VERSION 5.8 ;
BUSBITCHARS "[]" ;
DIVIDERCHAR "/" ;
UNITS
    DATABASE MICRONS 1000 ;
END UNITS

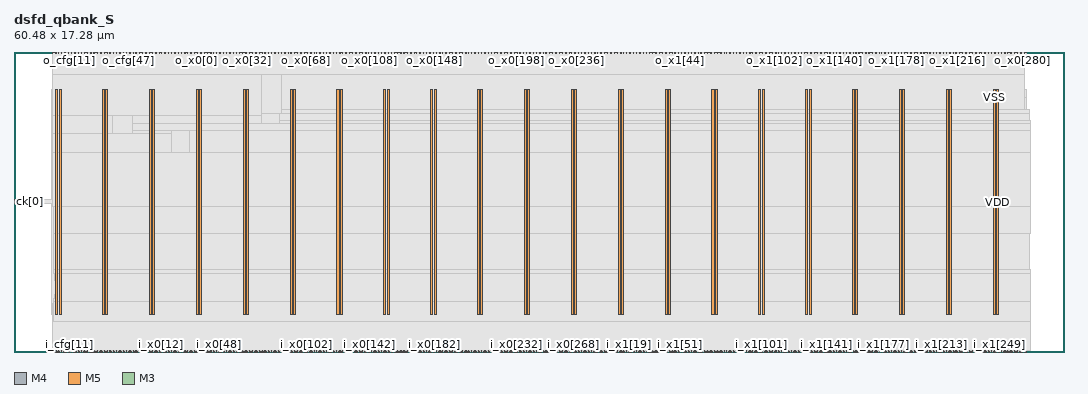
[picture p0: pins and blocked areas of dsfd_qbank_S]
MACRO dsfd_qbank_S
  FOREIGN dsfd_qbank_S 0 0 ;
  CLASS BLOCK ;
  SIZE 60.48 BY 17.28 ;
  PIN ck[0]
    DIRECTION INPUT ;
    USE SIGNAL ;
    PORT
      LAYER M4 ;
        RECT  0 8.64 0.084 8.664 ;
    END
  END ck[0]
  PIN i_cfg[0]
    DIRECTION INPUT ;
    USE SIGNAL ;
    PORT
      LAYER M5 ;
        RECT  2.208 0 2.232 0.084 ;
    END
  END i_cfg[0]
  PIN i_cfg[10]
    DIRECTION INPUT ;
    USE SIGNAL ;
    PORT
      LAYER M5 ;
        RECT  3.12 0 3.144 0.084 ;
    END
  END i_cfg[10]
  PIN i_cfg[11]
    DIRECTION INPUT ;
    USE SIGNAL ;
    PORT
      LAYER M3 ;
        RECT  3.204 0 3.222 0.038 ;
    END
  END i_cfg[11]
  PIN i_cfg[12]
    DIRECTION INPUT ;
    USE SIGNAL ;
    PORT
      LAYER M5 ;
        RECT  3.312 0 3.336 0.084 ;
    END
  END i_cfg[12]
  PIN i_cfg[13]
    DIRECTION INPUT ;
    USE SIGNAL ;
    PORT
      LAYER M3 ;
        RECT  3.42 0 3.438 0.038 ;
    END
  END i_cfg[13]
  PIN i_cfg[14]
    DIRECTION INPUT ;
    USE SIGNAL ;
    PORT
      LAYER M5 ;
        RECT  3.504 0 3.528 0.084 ;
    END
  END i_cfg[14]
  PIN i_cfg[15]
    DIRECTION INPUT ;
    USE SIGNAL ;
    PORT
      LAYER M3 ;
        RECT  3.6 0 3.618 0.038 ;
    END
  END i_cfg[15]
  PIN i_cfg[16]
    DIRECTION INPUT ;
    USE SIGNAL ;
    PORT
      LAYER M5 ;
        RECT  3.696 0 3.72 0.084 ;
    END
  END i_cfg[16]
  PIN i_cfg[17]
    DIRECTION INPUT ;
    USE SIGNAL ;
    PORT
      LAYER M3 ;
        RECT  3.78 0 3.798 0.038 ;
    END
  END i_cfg[17]
  PIN i_cfg[18]
    DIRECTION INPUT ;
    USE SIGNAL ;
    PORT
      LAYER M5 ;
        RECT  3.888 0 3.912 0.084 ;
    END
  END i_cfg[18]
  PIN i_cfg[19]
    DIRECTION INPUT ;
    USE SIGNAL ;
    PORT
      LAYER M3 ;
        RECT  3.996 0 4.014 0.038 ;
    END
  END i_cfg[19]
  PIN i_cfg[1]
    DIRECTION INPUT ;
    USE SIGNAL ;
    PORT
      LAYER M3 ;
        RECT  2.304 0 2.322 0.038 ;
    END
  END i_cfg[1]
  PIN i_cfg[20]
    DIRECTION INPUT ;
    USE SIGNAL ;
    PORT
      LAYER M5 ;
        RECT  4.032 0 4.056 0.084 ;
    END
  END i_cfg[20]
  PIN i_cfg[21]
    DIRECTION INPUT ;
    USE SIGNAL ;
    PORT
      LAYER M3 ;
        RECT  4.14 0 4.158 0.038 ;
    END
  END i_cfg[21]
  PIN i_cfg[22]
    DIRECTION INPUT ;
    USE SIGNAL ;
    PORT
      LAYER M5 ;
        RECT  4.224 0 4.248 0.084 ;
    END
  END i_cfg[22]
  PIN i_cfg[23]
    DIRECTION INPUT ;
    USE SIGNAL ;
    PORT
      LAYER M3 ;
        RECT  4.32 0 4.338 0.038 ;
    END
  END i_cfg[23]
  PIN i_cfg[24]
    DIRECTION INPUT ;
    USE SIGNAL ;
    PORT
      LAYER M5 ;
        RECT  4.416 0 4.44 0.084 ;
    END
  END i_cfg[24]
  PIN i_cfg[25]
    DIRECTION INPUT ;
    USE SIGNAL ;
    PORT
      LAYER M3 ;
        RECT  4.5 0 4.518 0.038 ;
    END
  END i_cfg[25]
  PIN i_cfg[26]
    DIRECTION INPUT ;
    USE SIGNAL ;
    PORT
      LAYER M5 ;
        RECT  4.608 0 4.632 0.084 ;
    END
  END i_cfg[26]
  PIN i_cfg[27]
    DIRECTION INPUT ;
    USE SIGNAL ;
    PORT
      LAYER M3 ;
        RECT  4.716 0 4.734 0.038 ;
    END
  END i_cfg[27]
  PIN i_cfg[28]
    DIRECTION INPUT ;
    USE SIGNAL ;
    PORT
      LAYER M5 ;
        RECT  4.8 0 4.824 0.084 ;
    END
  END i_cfg[28]
  PIN i_cfg[29]
    DIRECTION INPUT ;
    USE SIGNAL ;
    PORT
      LAYER M3 ;
        RECT  4.896 0 4.914 0.038 ;
    END
  END i_cfg[29]
  PIN i_cfg[2]
    DIRECTION INPUT ;
    USE SIGNAL ;
    PORT
      LAYER M5 ;
        RECT  2.4 0 2.424 0.084 ;
    END
  END i_cfg[2]
  PIN i_cfg[30]
    DIRECTION INPUT ;
    USE SIGNAL ;
    PORT
      LAYER M5 ;
        RECT  4.992 0 5.016 0.084 ;
    END
  END i_cfg[30]
  PIN i_cfg[31]
    DIRECTION INPUT ;
    USE SIGNAL ;
    PORT
      LAYER M3 ;
        RECT  5.076 0 5.094 0.038 ;
    END
  END i_cfg[31]
  PIN i_cfg[32]
    DIRECTION INPUT ;
    USE SIGNAL ;
    PORT
      LAYER M5 ;
        RECT  5.184 0 5.208 0.084 ;
    END
  END i_cfg[32]
  PIN i_cfg[33]
    DIRECTION INPUT ;
    USE SIGNAL ;
    PORT
      LAYER M3 ;
        RECT  5.292 0 5.31 0.038 ;
    END
  END i_cfg[33]
  PIN i_cfg[34]
    DIRECTION INPUT ;
    USE SIGNAL ;
    PORT
      LAYER M5 ;
        RECT  5.376 0 5.4 0.084 ;
    END
  END i_cfg[34]
  PIN i_cfg[35]
    DIRECTION INPUT ;
    USE SIGNAL ;
    PORT
      LAYER M3 ;
        RECT  5.472 0 5.49 0.038 ;
    END
  END i_cfg[35]
  PIN i_cfg[36]
    DIRECTION INPUT ;
    USE SIGNAL ;
    PORT
      LAYER M5 ;
        RECT  5.52 0 5.544 0.084 ;
    END
  END i_cfg[36]
  PIN i_cfg[37]
    DIRECTION INPUT ;
    USE SIGNAL ;
    PORT
      LAYER M3 ;
        RECT  5.616 0 5.634 0.038 ;
    END
  END i_cfg[37]
  PIN i_cfg[38]
    DIRECTION INPUT ;
    USE SIGNAL ;
    PORT
      LAYER M5 ;
        RECT  5.712 0 5.736 0.084 ;
    END
  END i_cfg[38]
  PIN i_cfg[39]
    DIRECTION INPUT ;
    USE SIGNAL ;
    PORT
      LAYER M3 ;
        RECT  5.796 0 5.814 0.038 ;
    END
  END i_cfg[39]
  PIN i_cfg[3]
    DIRECTION INPUT ;
    USE SIGNAL ;
    PORT
      LAYER M3 ;
        RECT  2.484 0 2.502 0.038 ;
    END
  END i_cfg[3]
  PIN i_cfg[40]
    DIRECTION INPUT ;
    USE SIGNAL ;
    PORT
      LAYER M5 ;
        RECT  5.904 0 5.928 0.084 ;
    END
  END i_cfg[40]
  PIN i_cfg[41]
    DIRECTION INPUT ;
    USE SIGNAL ;
    PORT
      LAYER M3 ;
        RECT  6.012 0 6.03 0.038 ;
    END
  END i_cfg[41]
  PIN i_cfg[42]
    DIRECTION INPUT ;
    USE SIGNAL ;
    PORT
      LAYER M5 ;
        RECT  6.096 0 6.12 0.084 ;
    END
  END i_cfg[42]
  PIN i_cfg[43]
    DIRECTION INPUT ;
    USE SIGNAL ;
    PORT
      LAYER M3 ;
        RECT  6.192 0 6.21 0.038 ;
    END
  END i_cfg[43]
  PIN i_cfg[44]
    DIRECTION INPUT ;
    USE SIGNAL ;
    PORT
      LAYER M5 ;
        RECT  6.288 0 6.312 0.084 ;
    END
  END i_cfg[44]
  PIN i_cfg[45]
    DIRECTION INPUT ;
    USE SIGNAL ;
    PORT
      LAYER M3 ;
        RECT  6.372 0 6.39 0.038 ;
    END
  END i_cfg[45]
  PIN i_cfg[46]
    DIRECTION INPUT ;
    USE SIGNAL ;
    PORT
      LAYER M5 ;
        RECT  6.48 0 6.504 0.084 ;
    END
  END i_cfg[46]
  PIN i_cfg[47]
    DIRECTION INPUT ;
    USE SIGNAL ;
    PORT
      LAYER M3 ;
        RECT  6.588 0 6.606 0.038 ;
    END
  END i_cfg[47]
  PIN i_cfg[48]
    DIRECTION INPUT ;
    USE SIGNAL ;
    PORT
      LAYER M5 ;
        RECT  6.672 0 6.696 0.084 ;
    END
  END i_cfg[48]
  PIN i_cfg[49]
    DIRECTION INPUT ;
    USE SIGNAL ;
    PORT
      LAYER M3 ;
        RECT  6.768 0 6.786 0.038 ;
    END
  END i_cfg[49]
  PIN i_cfg[4]
    DIRECTION INPUT ;
    USE SIGNAL ;
    PORT
      LAYER M5 ;
        RECT  2.544 0 2.568 0.084 ;
    END
  END i_cfg[4]
  PIN i_cfg[50]
    DIRECTION INPUT ;
    USE SIGNAL ;
    PORT
      LAYER M5 ;
        RECT  6.864 0 6.888 0.084 ;
    END
  END i_cfg[50]
  PIN i_cfg[51]
    DIRECTION INPUT ;
    USE SIGNAL ;
    PORT
      LAYER M3 ;
        RECT  6.948 0 6.966 0.038 ;
    END
  END i_cfg[51]
  PIN i_cfg[52]
    DIRECTION INPUT ;
    USE SIGNAL ;
    PORT
      LAYER M5 ;
        RECT  7.008 0 7.032 0.084 ;
    END
  END i_cfg[52]
  PIN i_cfg[53]
    DIRECTION INPUT ;
    USE SIGNAL ;
    PORT
      LAYER M3 ;
        RECT  7.092 0 7.11 0.038 ;
    END
  END i_cfg[53]
  PIN i_cfg[5]
    DIRECTION INPUT ;
    USE SIGNAL ;
    PORT
      LAYER M3 ;
        RECT  2.628 0 2.646 0.038 ;
    END
  END i_cfg[5]
  PIN i_cfg[6]
    DIRECTION INPUT ;
    USE SIGNAL ;
    PORT
      LAYER M5 ;
        RECT  2.736 0 2.76 0.084 ;
    END
  END i_cfg[6]
  PIN i_cfg[7]
    DIRECTION INPUT ;
    USE SIGNAL ;
    PORT
      LAYER M3 ;
        RECT  2.844 0 2.862 0.038 ;
    END
  END i_cfg[7]
  PIN i_cfg[8]
    DIRECTION INPUT ;
    USE SIGNAL ;
    PORT
      LAYER M5 ;
        RECT  2.928 0 2.952 0.084 ;
    END
  END i_cfg[8]
  PIN i_cfg[9]
    DIRECTION INPUT ;
    USE SIGNAL ;
    PORT
      LAYER M3 ;
        RECT  3.024 0 3.042 0.038 ;
    END
  END i_cfg[9]
  PIN i_go[0]
    DIRECTION INPUT ;
    USE SIGNAL ;
    PORT
      LAYER M5 ;
        RECT  7.2 0 7.224 0.084 ;
    END
  END i_go[0]
  PIN i_x0[0]
    DIRECTION INPUT ;
    USE SIGNAL ;
    PORT
      LAYER M3 ;
        RECT  7.308 0 7.326 0.038 ;
    END
  END i_x0[0]
  PIN i_x0[100]
    DIRECTION INPUT ;
    USE SIGNAL ;
    PORT
      LAYER M3 ;
        RECT  16.596 0 16.614 0.038 ;
    END
  END i_x0[100]
  PIN i_x0[101]
    DIRECTION INPUT ;
    USE SIGNAL ;
    PORT
      LAYER M5 ;
        RECT  16.704 0 16.728 0.084 ;
    END
  END i_x0[101]
  PIN i_x0[102]
    DIRECTION INPUT ;
    USE SIGNAL ;
    PORT
      LAYER M3 ;
        RECT  16.812 0 16.83 0.038 ;
    END
  END i_x0[102]
  PIN i_x0[103]
    DIRECTION INPUT ;
    USE SIGNAL ;
    PORT
      LAYER M5 ;
        RECT  16.896 0 16.92 0.084 ;
    END
  END i_x0[103]
  PIN i_x0[104]
    DIRECTION INPUT ;
    USE SIGNAL ;
    PORT
      LAYER M3 ;
        RECT  16.992 0 17.01 0.038 ;
    END
  END i_x0[104]
  PIN i_x0[105]
    DIRECTION INPUT ;
    USE SIGNAL ;
    PORT
      LAYER M5 ;
        RECT  17.088 0 17.112 0.084 ;
    END
  END i_x0[105]
  PIN i_x0[106]
    DIRECTION INPUT ;
    USE SIGNAL ;
    PORT
      LAYER M3 ;
        RECT  17.172 0 17.19 0.038 ;
    END
  END i_x0[106]
  PIN i_x0[107]
    DIRECTION INPUT ;
    USE SIGNAL ;
    PORT
      LAYER M5 ;
        RECT  17.28 0 17.304 0.084 ;
    END
  END i_x0[107]
  PIN i_x0[108]
    DIRECTION INPUT ;
    USE SIGNAL ;
    PORT
      LAYER M3 ;
        RECT  17.316 0 17.334 0.038 ;
    END
  END i_x0[108]
  PIN i_x0[109]
    DIRECTION INPUT ;
    USE SIGNAL ;
    PORT
      LAYER M5 ;
        RECT  17.424 0 17.448 0.084 ;
    END
  END i_x0[109]
  PIN i_x0[10]
    DIRECTION INPUT ;
    USE SIGNAL ;
    PORT
      LAYER M3 ;
        RECT  8.244 0 8.262 0.038 ;
    END
  END i_x0[10]
  PIN i_x0[110]
    DIRECTION INPUT ;
    USE SIGNAL ;
    PORT
      LAYER M3 ;
        RECT  17.532 0 17.55 0.038 ;
    END
  END i_x0[110]
  PIN i_x0[111]
    DIRECTION INPUT ;
    USE SIGNAL ;
    PORT
      LAYER M5 ;
        RECT  17.616 0 17.64 0.084 ;
    END
  END i_x0[111]
  PIN i_x0[112]
    DIRECTION INPUT ;
    USE SIGNAL ;
    PORT
      LAYER M3 ;
        RECT  17.712 0 17.73 0.038 ;
    END
  END i_x0[112]
  PIN i_x0[113]
    DIRECTION INPUT ;
    USE SIGNAL ;
    PORT
      LAYER M5 ;
        RECT  17.808 0 17.832 0.084 ;
    END
  END i_x0[113]
  PIN i_x0[114]
    DIRECTION INPUT ;
    USE SIGNAL ;
    PORT
      LAYER M3 ;
        RECT  17.892 0 17.91 0.038 ;
    END
  END i_x0[114]
  PIN i_x0[115]
    DIRECTION INPUT ;
    USE SIGNAL ;
    PORT
      LAYER M5 ;
        RECT  18 0 18.024 0.084 ;
    END
  END i_x0[115]
  PIN i_x0[116]
    DIRECTION INPUT ;
    USE SIGNAL ;
    PORT
      LAYER M3 ;
        RECT  18.108 0 18.126 0.038 ;
    END
  END i_x0[116]
  PIN i_x0[117]
    DIRECTION INPUT ;
    USE SIGNAL ;
    PORT
      LAYER M5 ;
        RECT  18.192 0 18.216 0.084 ;
    END
  END i_x0[117]
  PIN i_x0[118]
    DIRECTION INPUT ;
    USE SIGNAL ;
    PORT
      LAYER M3 ;
        RECT  18.288 0 18.306 0.038 ;
    END
  END i_x0[118]
  PIN i_x0[119]
    DIRECTION INPUT ;
    USE SIGNAL ;
    PORT
      LAYER M5 ;
        RECT  18.384 0 18.408 0.084 ;
    END
  END i_x0[119]
  PIN i_x0[11]
    DIRECTION INPUT ;
    USE SIGNAL ;
    PORT
      LAYER M5 ;
        RECT  8.352 0 8.376 0.084 ;
    END
  END i_x0[11]
  PIN i_x0[120]
    DIRECTION INPUT ;
    USE SIGNAL ;
    PORT
      LAYER M3 ;
        RECT  18.468 0 18.486 0.038 ;
    END
  END i_x0[120]
  PIN i_x0[121]
    DIRECTION INPUT ;
    USE SIGNAL ;
    PORT
      LAYER M5 ;
        RECT  18.576 0 18.6 0.084 ;
    END
  END i_x0[121]
  PIN i_x0[122]
    DIRECTION INPUT ;
    USE SIGNAL ;
    PORT
      LAYER M3 ;
        RECT  18.684 0 18.702 0.038 ;
    END
  END i_x0[122]
  PIN i_x0[123]
    DIRECTION INPUT ;
    USE SIGNAL ;
    PORT
      LAYER M5 ;
        RECT  18.768 0 18.792 0.084 ;
    END
  END i_x0[123]
  PIN i_x0[124]
    DIRECTION INPUT ;
    USE SIGNAL ;
    PORT
      LAYER M3 ;
        RECT  18.828 0 18.846 0.038 ;
    END
  END i_x0[124]
  PIN i_x0[125]
    DIRECTION INPUT ;
    USE SIGNAL ;
    PORT
      LAYER M5 ;
        RECT  18.912 0 18.936 0.084 ;
    END
  END i_x0[125]
  PIN i_x0[126]
    DIRECTION INPUT ;
    USE SIGNAL ;
    PORT
      LAYER M3 ;
        RECT  19.008 0 19.026 0.038 ;
    END
  END i_x0[126]
  PIN i_x0[127]
    DIRECTION INPUT ;
    USE SIGNAL ;
    PORT
      LAYER M5 ;
        RECT  19.104 0 19.128 0.084 ;
    END
  END i_x0[127]
  PIN i_x0[128]
    DIRECTION INPUT ;
    USE SIGNAL ;
    PORT
      LAYER M3 ;
        RECT  19.188 0 19.206 0.038 ;
    END
  END i_x0[128]
  PIN i_x0[129]
    DIRECTION INPUT ;
    USE SIGNAL ;
    PORT
      LAYER M5 ;
        RECT  19.296 0 19.32 0.084 ;
    END
  END i_x0[129]
  PIN i_x0[12]
    DIRECTION INPUT ;
    USE SIGNAL ;
    PORT
      LAYER M3 ;
        RECT  8.46 0 8.478 0.038 ;
    END
  END i_x0[12]
  PIN i_x0[130]
    DIRECTION INPUT ;
    USE SIGNAL ;
    PORT
      LAYER M3 ;
        RECT  19.404 0 19.422 0.038 ;
    END
  END i_x0[130]
  PIN i_x0[131]
    DIRECTION INPUT ;
    USE SIGNAL ;
    PORT
      LAYER M5 ;
        RECT  19.488 0 19.512 0.084 ;
    END
  END i_x0[131]
  PIN i_x0[132]
    DIRECTION INPUT ;
    USE SIGNAL ;
    PORT
      LAYER M3 ;
        RECT  19.584 0 19.602 0.038 ;
    END
  END i_x0[132]
  PIN i_x0[133]
    DIRECTION INPUT ;
    USE SIGNAL ;
    PORT
      LAYER M5 ;
        RECT  19.68 0 19.704 0.084 ;
    END
  END i_x0[133]
  PIN i_x0[134]
    DIRECTION INPUT ;
    USE SIGNAL ;
    PORT
      LAYER M3 ;
        RECT  19.764 0 19.782 0.038 ;
    END
  END i_x0[134]
  PIN i_x0[135]
    DIRECTION INPUT ;
    USE SIGNAL ;
    PORT
      LAYER M5 ;
        RECT  19.872 0 19.896 0.084 ;
    END
  END i_x0[135]
  PIN i_x0[136]
    DIRECTION INPUT ;
    USE SIGNAL ;
    PORT
      LAYER M3 ;
        RECT  19.98 0 19.998 0.038 ;
    END
  END i_x0[136]
  PIN i_x0[137]
    DIRECTION INPUT ;
    USE SIGNAL ;
    PORT
      LAYER M5 ;
        RECT  20.064 0 20.088 0.084 ;
    END
  END i_x0[137]
  PIN i_x0[138]
    DIRECTION INPUT ;
    USE SIGNAL ;
    PORT
      LAYER M3 ;
        RECT  20.16 0 20.178 0.038 ;
    END
  END i_x0[138]
  PIN i_x0[139]
    DIRECTION INPUT ;
    USE SIGNAL ;
    PORT
      LAYER M5 ;
        RECT  20.256 0 20.28 0.084 ;
    END
  END i_x0[139]
  PIN i_x0[13]
    DIRECTION INPUT ;
    USE SIGNAL ;
    PORT
      LAYER M5 ;
        RECT  8.496 0 8.52 0.084 ;
    END
  END i_x0[13]
  PIN i_x0[140]
    DIRECTION INPUT ;
    USE SIGNAL ;
    PORT
      LAYER M3 ;
        RECT  20.304 0 20.322 0.038 ;
    END
  END i_x0[140]
  PIN i_x0[141]
    DIRECTION INPUT ;
    USE SIGNAL ;
    PORT
      LAYER M5 ;
        RECT  20.4 0 20.424 0.084 ;
    END
  END i_x0[141]
  PIN i_x0[142]
    DIRECTION INPUT ;
    USE SIGNAL ;
    PORT
      LAYER M3 ;
        RECT  20.484 0 20.502 0.038 ;
    END
  END i_x0[142]
  PIN i_x0[143]
    DIRECTION INPUT ;
    USE SIGNAL ;
    PORT
      LAYER M5 ;
        RECT  20.592 0 20.616 0.084 ;
    END
  END i_x0[143]
  PIN i_x0[144]
    DIRECTION INPUT ;
    USE SIGNAL ;
    PORT
      LAYER M3 ;
        RECT  20.7 0 20.718 0.038 ;
    END
  END i_x0[144]
  PIN i_x0[145]
    DIRECTION INPUT ;
    USE SIGNAL ;
    PORT
      LAYER M5 ;
        RECT  20.784 0 20.808 0.084 ;
    END
  END i_x0[145]
  PIN i_x0[146]
    DIRECTION INPUT ;
    USE SIGNAL ;
    PORT
      LAYER M3 ;
        RECT  20.88 0 20.898 0.038 ;
    END
  END i_x0[146]
  PIN i_x0[147]
    DIRECTION INPUT ;
    USE SIGNAL ;
    PORT
      LAYER M5 ;
        RECT  20.976 0 21 0.084 ;
    END
  END i_x0[147]
  PIN i_x0[148]
    DIRECTION INPUT ;
    USE SIGNAL ;
    PORT
      LAYER M3 ;
        RECT  21.06 0 21.078 0.038 ;
    END
  END i_x0[148]
  PIN i_x0[149]
    DIRECTION INPUT ;
    USE SIGNAL ;
    PORT
      LAYER M5 ;
        RECT  21.168 0 21.192 0.084 ;
    END
  END i_x0[149]
  PIN i_x0[14]
    DIRECTION INPUT ;
    USE SIGNAL ;
    PORT
      LAYER M3 ;
        RECT  8.604 0 8.622 0.038 ;
    END
  END i_x0[14]
  PIN i_x0[150]
    DIRECTION INPUT ;
    USE SIGNAL ;
    PORT
      LAYER M3 ;
        RECT  21.276 0 21.294 0.038 ;
    END
  END i_x0[150]
  PIN i_x0[151]
    DIRECTION INPUT ;
    USE SIGNAL ;
    PORT
      LAYER M5 ;
        RECT  21.36 0 21.384 0.084 ;
    END
  END i_x0[151]
  PIN i_x0[152]
    DIRECTION INPUT ;
    USE SIGNAL ;
    PORT
      LAYER M3 ;
        RECT  21.456 0 21.474 0.038 ;
    END
  END i_x0[152]
  PIN i_x0[153]
    DIRECTION INPUT ;
    USE SIGNAL ;
    PORT
      LAYER M5 ;
        RECT  21.552 0 21.576 0.084 ;
    END
  END i_x0[153]
  PIN i_x0[154]
    DIRECTION INPUT ;
    USE SIGNAL ;
    PORT
      LAYER M3 ;
        RECT  21.636 0 21.654 0.038 ;
    END
  END i_x0[154]
  PIN i_x0[155]
    DIRECTION INPUT ;
    USE SIGNAL ;
    PORT
      LAYER M5 ;
        RECT  21.744 0 21.768 0.084 ;
    END
  END i_x0[155]
  PIN i_x0[156]
    DIRECTION INPUT ;
    USE SIGNAL ;
    PORT
      LAYER M3 ;
        RECT  21.78 0 21.798 0.038 ;
    END
  END i_x0[156]
  PIN i_x0[157]
    DIRECTION INPUT ;
    USE SIGNAL ;
    PORT
      LAYER M5 ;
        RECT  21.888 0 21.912 0.084 ;
    END
  END i_x0[157]
  PIN i_x0[158]
    DIRECTION INPUT ;
    USE SIGNAL ;
    PORT
      LAYER M3 ;
        RECT  21.996 0 22.014 0.038 ;
    END
  END i_x0[158]
  PIN i_x0[159]
    DIRECTION INPUT ;
    USE SIGNAL ;
    PORT
      LAYER M5 ;
        RECT  22.08 0 22.104 0.084 ;
    END
  END i_x0[159]
  PIN i_x0[15]
    DIRECTION INPUT ;
    USE SIGNAL ;
    PORT
      LAYER M5 ;
        RECT  8.688 0 8.712 0.084 ;
    END
  END i_x0[15]
  PIN i_x0[160]
    DIRECTION INPUT ;
    USE SIGNAL ;
    PORT
      LAYER M3 ;
        RECT  22.176 0 22.194 0.038 ;
    END
  END i_x0[160]
  PIN i_x0[161]
    DIRECTION INPUT ;
    USE SIGNAL ;
    PORT
      LAYER M5 ;
        RECT  22.272 0 22.296 0.084 ;
    END
  END i_x0[161]
  PIN i_x0[162]
    DIRECTION INPUT ;
    USE SIGNAL ;
    PORT
      LAYER M3 ;
        RECT  22.356 0 22.374 0.038 ;
    END
  END i_x0[162]
  PIN i_x0[163]
    DIRECTION INPUT ;
    USE SIGNAL ;
    PORT
      LAYER M5 ;
        RECT  22.464 0 22.488 0.084 ;
    END
  END i_x0[163]
  PIN i_x0[164]
    DIRECTION INPUT ;
    USE SIGNAL ;
    PORT
      LAYER M3 ;
        RECT  22.572 0 22.59 0.038 ;
    END
  END i_x0[164]
  PIN i_x0[165]
    DIRECTION INPUT ;
    USE SIGNAL ;
    PORT
      LAYER M5 ;
        RECT  22.656 0 22.68 0.084 ;
    END
  END i_x0[165]
  PIN i_x0[166]
    DIRECTION INPUT ;
    USE SIGNAL ;
    PORT
      LAYER M3 ;
        RECT  22.752 0 22.77 0.038 ;
    END
  END i_x0[166]
  PIN i_x0[167]
    DIRECTION INPUT ;
    USE SIGNAL ;
    PORT
      LAYER M5 ;
        RECT  22.848 0 22.872 0.084 ;
    END
  END i_x0[167]
  PIN i_x0[168]
    DIRECTION INPUT ;
    USE SIGNAL ;
    PORT
      LAYER M3 ;
        RECT  22.932 0 22.95 0.038 ;
    END
  END i_x0[168]
  PIN i_x0[169]
    DIRECTION INPUT ;
    USE SIGNAL ;
    PORT
      LAYER M5 ;
        RECT  23.04 0 23.064 0.084 ;
    END
  END i_x0[169]
  PIN i_x0[16]
    DIRECTION INPUT ;
    USE SIGNAL ;
    PORT
      LAYER M3 ;
        RECT  8.784 0 8.802 0.038 ;
    END
  END i_x0[16]
  PIN i_x0[170]
    DIRECTION INPUT ;
    USE SIGNAL ;
    PORT
      LAYER M3 ;
        RECT  23.148 0 23.166 0.038 ;
    END
  END i_x0[170]
  PIN i_x0[171]
    DIRECTION INPUT ;
    USE SIGNAL ;
    PORT
      LAYER M5 ;
        RECT  23.184 0 23.208 0.084 ;
    END
  END i_x0[171]
  PIN i_x0[172]
    DIRECTION INPUT ;
    USE SIGNAL ;
    PORT
      LAYER M3 ;
        RECT  23.292 0 23.31 0.038 ;
    END
  END i_x0[172]
  PIN i_x0[173]
    DIRECTION INPUT ;
    USE SIGNAL ;
    PORT
      LAYER M5 ;
        RECT  23.376 0 23.4 0.084 ;
    END
  END i_x0[173]
  PIN i_x0[174]
    DIRECTION INPUT ;
    USE SIGNAL ;
    PORT
      LAYER M3 ;
        RECT  23.472 0 23.49 0.038 ;
    END
  END i_x0[174]
  PIN i_x0[175]
    DIRECTION INPUT ;
    USE SIGNAL ;
    PORT
      LAYER M5 ;
        RECT  23.568 0 23.592 0.084 ;
    END
  END i_x0[175]
  PIN i_x0[176]
    DIRECTION INPUT ;
    USE SIGNAL ;
    PORT
      LAYER M3 ;
        RECT  23.652 0 23.67 0.038 ;
    END
  END i_x0[176]
  PIN i_x0[177]
    DIRECTION INPUT ;
    USE SIGNAL ;
    PORT
      LAYER M5 ;
        RECT  23.76 0 23.784 0.084 ;
    END
  END i_x0[177]
  PIN i_x0[178]
    DIRECTION INPUT ;
    USE SIGNAL ;
    PORT
      LAYER M3 ;
        RECT  23.868 0 23.886 0.038 ;
    END
  END i_x0[178]
  PIN i_x0[179]
    DIRECTION INPUT ;
    USE SIGNAL ;
    PORT
      LAYER M5 ;
        RECT  23.952 0 23.976 0.084 ;
    END
  END i_x0[179]
  PIN i_x0[17]
    DIRECTION INPUT ;
    USE SIGNAL ;
    PORT
      LAYER M5 ;
        RECT  8.88 0 8.904 0.084 ;
    END
  END i_x0[17]
  PIN i_x0[180]
    DIRECTION INPUT ;
    USE SIGNAL ;
    PORT
      LAYER M3 ;
        RECT  24.048 0 24.066 0.038 ;
    END
  END i_x0[180]
  PIN i_x0[181]
    DIRECTION INPUT ;
    USE SIGNAL ;
    PORT
      LAYER M5 ;
        RECT  24.144 0 24.168 0.084 ;
    END
  END i_x0[181]
  PIN i_x0[182]
    DIRECTION INPUT ;
    USE SIGNAL ;
    PORT
      LAYER M3 ;
        RECT  24.228 0 24.246 0.038 ;
    END
  END i_x0[182]
  PIN i_x0[183]
    DIRECTION INPUT ;
    USE SIGNAL ;
    PORT
      LAYER M5 ;
        RECT  24.336 0 24.36 0.084 ;
    END
  END i_x0[183]
  PIN i_x0[184]
    DIRECTION INPUT ;
    USE SIGNAL ;
    PORT
      LAYER M3 ;
        RECT  24.444 0 24.462 0.038 ;
    END
  END i_x0[184]
  PIN i_x0[185]
    DIRECTION INPUT ;
    USE SIGNAL ;
    PORT
      LAYER M5 ;
        RECT  24.528 0 24.552 0.084 ;
    END
  END i_x0[185]
  PIN i_x0[186]
    DIRECTION INPUT ;
    USE SIGNAL ;
    PORT
      LAYER M3 ;
        RECT  24.624 0 24.642 0.038 ;
    END
  END i_x0[186]
  PIN i_x0[187]
    DIRECTION INPUT ;
    USE SIGNAL ;
    PORT
      LAYER M5 ;
        RECT  24.672 0 24.696 0.084 ;
    END
  END i_x0[187]
  PIN i_x0[188]
    DIRECTION INPUT ;
    USE SIGNAL ;
    PORT
      LAYER M3 ;
        RECT  24.768 0 24.786 0.038 ;
    END
  END i_x0[188]
  PIN i_x0[189]
    DIRECTION INPUT ;
    USE SIGNAL ;
    PORT
      LAYER M5 ;
        RECT  24.864 0 24.888 0.084 ;
    END
  END i_x0[189]
  PIN i_x0[18]
    DIRECTION INPUT ;
    USE SIGNAL ;
    PORT
      LAYER M3 ;
        RECT  8.964 0 8.982 0.038 ;
    END
  END i_x0[18]
  PIN i_x0[190]
    DIRECTION INPUT ;
    USE SIGNAL ;
    PORT
      LAYER M3 ;
        RECT  24.948 0 24.966 0.038 ;
    END
  END i_x0[190]
  PIN i_x0[191]
    DIRECTION INPUT ;
    USE SIGNAL ;
    PORT
      LAYER M5 ;
        RECT  25.056 0 25.08 0.084 ;
    END
  END i_x0[191]
  PIN i_x0[192]
    DIRECTION INPUT ;
    USE SIGNAL ;
    PORT
      LAYER M3 ;
        RECT  25.164 0 25.182 0.038 ;
    END
  END i_x0[192]
  PIN i_x0[193]
    DIRECTION INPUT ;
    USE SIGNAL ;
    PORT
      LAYER M5 ;
        RECT  25.248 0 25.272 0.084 ;
    END
  END i_x0[193]
  PIN i_x0[194]
    DIRECTION INPUT ;
    USE SIGNAL ;
    PORT
      LAYER M3 ;
        RECT  25.344 0 25.362 0.038 ;
    END
  END i_x0[194]
  PIN i_x0[195]
    DIRECTION INPUT ;
    USE SIGNAL ;
    PORT
      LAYER M5 ;
        RECT  25.44 0 25.464 0.084 ;
    END
  END i_x0[195]
  PIN i_x0[196]
    DIRECTION INPUT ;
    USE SIGNAL ;
    PORT
      LAYER M3 ;
        RECT  25.524 0 25.542 0.038 ;
    END
  END i_x0[196]
  PIN i_x0[197]
    DIRECTION INPUT ;
    USE SIGNAL ;
    PORT
      LAYER M5 ;
        RECT  25.632 0 25.656 0.084 ;
    END
  END i_x0[197]
  PIN i_x0[198]
    DIRECTION INPUT ;
    USE SIGNAL ;
    PORT
      LAYER M3 ;
        RECT  25.74 0 25.758 0.038 ;
    END
  END i_x0[198]
  PIN i_x0[199]
    DIRECTION INPUT ;
    USE SIGNAL ;
    PORT
      LAYER M5 ;
        RECT  25.824 0 25.848 0.084 ;
    END
  END i_x0[199]
  PIN i_x0[19]
    DIRECTION INPUT ;
    USE SIGNAL ;
    PORT
      LAYER M5 ;
        RECT  9.072 0 9.096 0.084 ;
    END
  END i_x0[19]
  PIN i_x0[1]
    DIRECTION INPUT ;
    USE SIGNAL ;
    PORT
      LAYER M5 ;
        RECT  7.392 0 7.416 0.084 ;
    END
  END i_x0[1]
  PIN i_x0[200]
    DIRECTION INPUT ;
    USE SIGNAL ;
    PORT
      LAYER M3 ;
        RECT  25.92 0 25.938 0.038 ;
    END
  END i_x0[200]
  PIN i_x0[201]
    DIRECTION INPUT ;
    USE SIGNAL ;
    PORT
      LAYER M5 ;
        RECT  26.016 0 26.04 0.084 ;
    END
  END i_x0[201]
  PIN i_x0[202]
    DIRECTION INPUT ;
    USE SIGNAL ;
    PORT
      LAYER M3 ;
        RECT  26.1 0 26.118 0.038 ;
    END
  END i_x0[202]
  PIN i_x0[203]
    DIRECTION INPUT ;
    USE SIGNAL ;
    PORT
      LAYER M5 ;
        RECT  26.16 0 26.184 0.084 ;
    END
  END i_x0[203]
  PIN i_x0[204]
    DIRECTION INPUT ;
    USE SIGNAL ;
    PORT
      LAYER M3 ;
        RECT  26.244 0 26.262 0.038 ;
    END
  END i_x0[204]
  PIN i_x0[205]
    DIRECTION INPUT ;
    USE SIGNAL ;
    PORT
      LAYER M5 ;
        RECT  26.352 0 26.376 0.084 ;
    END
  END i_x0[205]
  PIN i_x0[206]
    DIRECTION INPUT ;
    USE SIGNAL ;
    PORT
      LAYER M3 ;
        RECT  26.46 0 26.478 0.038 ;
    END
  END i_x0[206]
  PIN i_x0[207]
    DIRECTION INPUT ;
    USE SIGNAL ;
    PORT
      LAYER M5 ;
        RECT  26.544 0 26.568 0.084 ;
    END
  END i_x0[207]
  PIN i_x0[208]
    DIRECTION INPUT ;
    USE SIGNAL ;
    PORT
      LAYER M3 ;
        RECT  26.64 0 26.658 0.038 ;
    END
  END i_x0[208]
  PIN i_x0[209]
    DIRECTION INPUT ;
    USE SIGNAL ;
    PORT
      LAYER M5 ;
        RECT  26.736 0 26.76 0.084 ;
    END
  END i_x0[209]
  PIN i_x0[20]
    DIRECTION INPUT ;
    USE SIGNAL ;
    PORT
      LAYER M3 ;
        RECT  9.18 0 9.198 0.038 ;
    END
  END i_x0[20]
  PIN i_x0[210]
    DIRECTION INPUT ;
    USE SIGNAL ;
    PORT
      LAYER M3 ;
        RECT  26.82 0 26.838 0.038 ;
    END
  END i_x0[210]
  PIN i_x0[211]
    DIRECTION INPUT ;
    USE SIGNAL ;
    PORT
      LAYER M5 ;
        RECT  26.928 0 26.952 0.084 ;
    END
  END i_x0[211]
  PIN i_x0[212]
    DIRECTION INPUT ;
    USE SIGNAL ;
    PORT
      LAYER M3 ;
        RECT  27.036 0 27.054 0.038 ;
    END
  END i_x0[212]
  PIN i_x0[213]
    DIRECTION INPUT ;
    USE SIGNAL ;
    PORT
      LAYER M5 ;
        RECT  27.12 0 27.144 0.084 ;
    END
  END i_x0[213]
  PIN i_x0[214]
    DIRECTION INPUT ;
    USE SIGNAL ;
    PORT
      LAYER M3 ;
        RECT  27.216 0 27.234 0.038 ;
    END
  END i_x0[214]
  PIN i_x0[215]
    DIRECTION INPUT ;
    USE SIGNAL ;
    PORT
      LAYER M5 ;
        RECT  27.312 0 27.336 0.084 ;
    END
  END i_x0[215]
  PIN i_x0[216]
    DIRECTION INPUT ;
    USE SIGNAL ;
    PORT
      LAYER M3 ;
        RECT  27.396 0 27.414 0.038 ;
    END
  END i_x0[216]
  PIN i_x0[217]
    DIRECTION INPUT ;
    USE SIGNAL ;
    PORT
      LAYER M5 ;
        RECT  27.504 0 27.528 0.084 ;
    END
  END i_x0[217]
  PIN i_x0[218]
    DIRECTION INPUT ;
    USE SIGNAL ;
    PORT
      LAYER M3 ;
        RECT  27.612 0 27.63 0.038 ;
    END
  END i_x0[218]
  PIN i_x0[219]
    DIRECTION INPUT ;
    USE SIGNAL ;
    PORT
      LAYER M5 ;
        RECT  27.648 0 27.672 0.084 ;
    END
  END i_x0[219]
  PIN i_x0[21]
    DIRECTION INPUT ;
    USE SIGNAL ;
    PORT
      LAYER M5 ;
        RECT  9.264 0 9.288 0.084 ;
    END
  END i_x0[21]
  PIN i_x0[220]
    DIRECTION INPUT ;
    USE SIGNAL ;
    PORT
      LAYER M3 ;
        RECT  27.756 0 27.774 0.038 ;
    END
  END i_x0[220]
  PIN i_x0[221]
    DIRECTION INPUT ;
    USE SIGNAL ;
    PORT
      LAYER M5 ;
        RECT  27.84 0 27.864 0.084 ;
    END
  END i_x0[221]
  PIN i_x0[222]
    DIRECTION INPUT ;
    USE SIGNAL ;
    PORT
      LAYER M3 ;
        RECT  27.936 0 27.954 0.038 ;
    END
  END i_x0[222]
  PIN i_x0[223]
    DIRECTION INPUT ;
    USE SIGNAL ;
    PORT
      LAYER M5 ;
        RECT  28.032 0 28.056 0.084 ;
    END
  END i_x0[223]
  PIN i_x0[224]
    DIRECTION INPUT ;
    USE SIGNAL ;
    PORT
      LAYER M3 ;
        RECT  28.116 0 28.134 0.038 ;
    END
  END i_x0[224]
  PIN i_x0[225]
    DIRECTION INPUT ;
    USE SIGNAL ;
    PORT
      LAYER M5 ;
        RECT  28.224 0 28.248 0.084 ;
    END
  END i_x0[225]
  PIN i_x0[226]
    DIRECTION INPUT ;
    USE SIGNAL ;
    PORT
      LAYER M3 ;
        RECT  28.332 0 28.35 0.038 ;
    END
  END i_x0[226]
  PIN i_x0[227]
    DIRECTION INPUT ;
    USE SIGNAL ;
    PORT
      LAYER M5 ;
        RECT  28.416 0 28.44 0.084 ;
    END
  END i_x0[227]
  PIN i_x0[228]
    DIRECTION INPUT ;
    USE SIGNAL ;
    PORT
      LAYER M3 ;
        RECT  28.512 0 28.53 0.038 ;
    END
  END i_x0[228]
  PIN i_x0[229]
    DIRECTION INPUT ;
    USE SIGNAL ;
    PORT
      LAYER M5 ;
        RECT  28.608 0 28.632 0.084 ;
    END
  END i_x0[229]
  PIN i_x0[22]
    DIRECTION INPUT ;
    USE SIGNAL ;
    PORT
      LAYER M3 ;
        RECT  9.36 0 9.378 0.038 ;
    END
  END i_x0[22]
  PIN i_x0[230]
    DIRECTION INPUT ;
    USE SIGNAL ;
    PORT
      LAYER M3 ;
        RECT  28.692 0 28.71 0.038 ;
    END
  END i_x0[230]
  PIN i_x0[231]
    DIRECTION INPUT ;
    USE SIGNAL ;
    PORT
      LAYER M5 ;
        RECT  28.8 0 28.824 0.084 ;
    END
  END i_x0[231]
  PIN i_x0[232]
    DIRECTION INPUT ;
    USE SIGNAL ;
    PORT
      LAYER M3 ;
        RECT  28.908 0 28.926 0.038 ;
    END
  END i_x0[232]
  PIN i_x0[233]
    DIRECTION INPUT ;
    USE SIGNAL ;
    PORT
      LAYER M5 ;
        RECT  28.992 0 29.016 0.084 ;
    END
  END i_x0[233]
  PIN i_x0[234]
    DIRECTION INPUT ;
    USE SIGNAL ;
    PORT
      LAYER M3 ;
        RECT  29.088 0 29.106 0.038 ;
    END
  END i_x0[234]
  PIN i_x0[235]
    DIRECTION INPUT ;
    USE SIGNAL ;
    PORT
      LAYER M5 ;
        RECT  29.136 0 29.16 0.084 ;
    END
  END i_x0[235]
  PIN i_x0[236]
    DIRECTION INPUT ;
    USE SIGNAL ;
    PORT
      LAYER M3 ;
        RECT  29.232 0 29.25 0.038 ;
    END
  END i_x0[236]
  PIN i_x0[237]
    DIRECTION INPUT ;
    USE SIGNAL ;
    PORT
      LAYER M5 ;
        RECT  29.328 0 29.352 0.084 ;
    END
  END i_x0[237]
  PIN i_x0[238]
    DIRECTION INPUT ;
    USE SIGNAL ;
    PORT
      LAYER M3 ;
        RECT  29.412 0 29.43 0.038 ;
    END
  END i_x0[238]
  PIN i_x0[239]
    DIRECTION INPUT ;
    USE SIGNAL ;
    PORT
      LAYER M5 ;
        RECT  29.52 0 29.544 0.084 ;
    END
  END i_x0[239]
  PIN i_x0[23]
    DIRECTION INPUT ;
    USE SIGNAL ;
    PORT
      LAYER M5 ;
        RECT  9.456 0 9.48 0.084 ;
    END
  END i_x0[23]
  PIN i_x0[240]
    DIRECTION INPUT ;
    USE SIGNAL ;
    PORT
      LAYER M3 ;
        RECT  29.628 0 29.646 0.038 ;
    END
  END i_x0[240]
  PIN i_x0[241]
    DIRECTION INPUT ;
    USE SIGNAL ;
    PORT
      LAYER M5 ;
        RECT  29.712 0 29.736 0.084 ;
    END
  END i_x0[241]
  PIN i_x0[242]
    DIRECTION INPUT ;
    USE SIGNAL ;
    PORT
      LAYER M3 ;
        RECT  29.808 0 29.826 0.038 ;
    END
  END i_x0[242]
  PIN i_x0[243]
    DIRECTION INPUT ;
    USE SIGNAL ;
    PORT
      LAYER M5 ;
        RECT  29.904 0 29.928 0.084 ;
    END
  END i_x0[243]
  PIN i_x0[244]
    DIRECTION INPUT ;
    USE SIGNAL ;
    PORT
      LAYER M3 ;
        RECT  29.988 0 30.006 0.038 ;
    END
  END i_x0[244]
  PIN i_x0[245]
    DIRECTION INPUT ;
    USE SIGNAL ;
    PORT
      LAYER M5 ;
        RECT  30.096 0 30.12 0.084 ;
    END
  END i_x0[245]
  PIN i_x0[246]
    DIRECTION INPUT ;
    USE SIGNAL ;
    PORT
      LAYER M3 ;
        RECT  30.204 0 30.222 0.038 ;
    END
  END i_x0[246]
  PIN i_x0[247]
    DIRECTION INPUT ;
    USE SIGNAL ;
    PORT
      LAYER M5 ;
        RECT  30.288 0 30.312 0.084 ;
    END
  END i_x0[247]
  PIN i_x0[248]
    DIRECTION INPUT ;
    USE SIGNAL ;
    PORT
      LAYER M3 ;
        RECT  30.384 0 30.402 0.038 ;
    END
  END i_x0[248]
  PIN i_x0[249]
    DIRECTION INPUT ;
    USE SIGNAL ;
    PORT
      LAYER M5 ;
        RECT  30.48 0 30.504 0.084 ;
    END
  END i_x0[249]
  PIN i_x0[24]
    DIRECTION INPUT ;
    USE SIGNAL ;
    PORT
      LAYER M3 ;
        RECT  9.54 0 9.558 0.038 ;
    END
  END i_x0[24]
  PIN i_x0[250]
    DIRECTION INPUT ;
    USE SIGNAL ;
    PORT
      LAYER M3 ;
        RECT  30.564 0 30.582 0.038 ;
    END
  END i_x0[250]
  PIN i_x0[251]
    DIRECTION INPUT ;
    USE SIGNAL ;
    PORT
      LAYER M5 ;
        RECT  30.624 0 30.648 0.084 ;
    END
  END i_x0[251]
  PIN i_x0[252]
    DIRECTION INPUT ;
    USE SIGNAL ;
    PORT
      LAYER M3 ;
        RECT  30.708 0 30.726 0.038 ;
    END
  END i_x0[252]
  PIN i_x0[253]
    DIRECTION INPUT ;
    USE SIGNAL ;
    PORT
      LAYER M5 ;
        RECT  30.816 0 30.84 0.084 ;
    END
  END i_x0[253]
  PIN i_x0[254]
    DIRECTION INPUT ;
    USE SIGNAL ;
    PORT
      LAYER M3 ;
        RECT  30.924 0 30.942 0.038 ;
    END
  END i_x0[254]
  PIN i_x0[255]
    DIRECTION INPUT ;
    USE SIGNAL ;
    PORT
      LAYER M5 ;
        RECT  31.008 0 31.032 0.084 ;
    END
  END i_x0[255]
  PIN i_x0[256]
    DIRECTION INPUT ;
    USE SIGNAL ;
    PORT
      LAYER M3 ;
        RECT  31.104 0 31.122 0.038 ;
    END
  END i_x0[256]
  PIN i_x0[257]
    DIRECTION INPUT ;
    USE SIGNAL ;
    PORT
      LAYER M5 ;
        RECT  31.2 0 31.224 0.084 ;
    END
  END i_x0[257]
  PIN i_x0[258]
    DIRECTION INPUT ;
    USE SIGNAL ;
    PORT
      LAYER M3 ;
        RECT  31.284 0 31.302 0.038 ;
    END
  END i_x0[258]
  PIN i_x0[259]
    DIRECTION INPUT ;
    USE SIGNAL ;
    PORT
      LAYER M5 ;
        RECT  31.392 0 31.416 0.084 ;
    END
  END i_x0[259]
  PIN i_x0[25]
    DIRECTION INPUT ;
    USE SIGNAL ;
    PORT
      LAYER M5 ;
        RECT  9.648 0 9.672 0.084 ;
    END
  END i_x0[25]
  PIN i_x0[260]
    DIRECTION INPUT ;
    USE SIGNAL ;
    PORT
      LAYER M3 ;
        RECT  31.5 0 31.518 0.038 ;
    END
  END i_x0[260]
  PIN i_x0[261]
    DIRECTION INPUT ;
    USE SIGNAL ;
    PORT
      LAYER M5 ;
        RECT  31.584 0 31.608 0.084 ;
    END
  END i_x0[261]
  PIN i_x0[262]
    DIRECTION INPUT ;
    USE SIGNAL ;
    PORT
      LAYER M3 ;
        RECT  31.68 0 31.698 0.038 ;
    END
  END i_x0[262]
  PIN i_x0[263]
    DIRECTION INPUT ;
    USE SIGNAL ;
    PORT
      LAYER M5 ;
        RECT  31.776 0 31.8 0.084 ;
    END
  END i_x0[263]
  PIN i_x0[264]
    DIRECTION INPUT ;
    USE SIGNAL ;
    PORT
      LAYER M3 ;
        RECT  31.86 0 31.878 0.038 ;
    END
  END i_x0[264]
  PIN i_x0[265]
    DIRECTION INPUT ;
    USE SIGNAL ;
    PORT
      LAYER M5 ;
        RECT  31.968 0 31.992 0.084 ;
    END
  END i_x0[265]
  PIN i_x0[266]
    DIRECTION INPUT ;
    USE SIGNAL ;
    PORT
      LAYER M3 ;
        RECT  32.076 0 32.094 0.038 ;
    END
  END i_x0[266]
  PIN i_x0[267]
    DIRECTION INPUT ;
    USE SIGNAL ;
    PORT
      LAYER M5 ;
        RECT  32.112 0 32.136 0.084 ;
    END
  END i_x0[267]
  PIN i_x0[268]
    DIRECTION INPUT ;
    USE SIGNAL ;
    PORT
      LAYER M3 ;
        RECT  32.22 0 32.238 0.038 ;
    END
  END i_x0[268]
  PIN i_x0[269]
    DIRECTION INPUT ;
    USE SIGNAL ;
    PORT
      LAYER M5 ;
        RECT  32.304 0 32.328 0.084 ;
    END
  END i_x0[269]
  PIN i_x0[26]
    DIRECTION INPUT ;
    USE SIGNAL ;
    PORT
      LAYER M3 ;
        RECT  9.756 0 9.774 0.038 ;
    END
  END i_x0[26]
  PIN i_x0[270]
    DIRECTION INPUT ;
    USE SIGNAL ;
    PORT
      LAYER M3 ;
        RECT  32.4 0 32.418 0.038 ;
    END
  END i_x0[270]
  PIN i_x0[271]
    DIRECTION INPUT ;
    USE SIGNAL ;
    PORT
      LAYER M5 ;
        RECT  32.496 0 32.52 0.084 ;
    END
  END i_x0[271]
  PIN i_x0[272]
    DIRECTION INPUT ;
    USE SIGNAL ;
    PORT
      LAYER M3 ;
        RECT  32.58 0 32.598 0.038 ;
    END
  END i_x0[272]
  PIN i_x0[273]
    DIRECTION INPUT ;
    USE SIGNAL ;
    PORT
      LAYER M5 ;
        RECT  32.688 0 32.712 0.084 ;
    END
  END i_x0[273]
  PIN i_x0[274]
    DIRECTION INPUT ;
    USE SIGNAL ;
    PORT
      LAYER M3 ;
        RECT  32.796 0 32.814 0.038 ;
    END
  END i_x0[274]
  PIN i_x0[275]
    DIRECTION INPUT ;
    USE SIGNAL ;
    PORT
      LAYER M5 ;
        RECT  32.88 0 32.904 0.084 ;
    END
  END i_x0[275]
  PIN i_x0[276]
    DIRECTION INPUT ;
    USE SIGNAL ;
    PORT
      LAYER M3 ;
        RECT  32.976 0 32.994 0.038 ;
    END
  END i_x0[276]
  PIN i_x0[277]
    DIRECTION INPUT ;
    USE SIGNAL ;
    PORT
      LAYER M5 ;
        RECT  33.072 0 33.096 0.084 ;
    END
  END i_x0[277]
  PIN i_x0[278]
    DIRECTION INPUT ;
    USE SIGNAL ;
    PORT
      LAYER M3 ;
        RECT  33.156 0 33.174 0.038 ;
    END
  END i_x0[278]
  PIN i_x0[279]
    DIRECTION INPUT ;
    USE SIGNAL ;
    PORT
      LAYER M5 ;
        RECT  33.264 0 33.288 0.084 ;
    END
  END i_x0[279]
  PIN i_x0[27]
    DIRECTION INPUT ;
    USE SIGNAL ;
    PORT
      LAYER M5 ;
        RECT  9.84 0 9.864 0.084 ;
    END
  END i_x0[27]
  PIN i_x0[280]
    DIRECTION INPUT ;
    USE SIGNAL ;
    PORT
      LAYER M3 ;
        RECT  33.372 0 33.39 0.038 ;
    END
  END i_x0[280]
  PIN i_x0[281]
    DIRECTION INPUT ;
    USE SIGNAL ;
    PORT
      LAYER M5 ;
        RECT  33.456 0 33.48 0.084 ;
    END
  END i_x0[281]
  PIN i_x0[282]
    DIRECTION INPUT ;
    USE SIGNAL ;
    PORT
      LAYER M3 ;
        RECT  33.552 0 33.57 0.038 ;
    END
  END i_x0[282]
  PIN i_x0[28]
    DIRECTION INPUT ;
    USE SIGNAL ;
    PORT
      LAYER M3 ;
        RECT  9.9 0 9.918 0.038 ;
    END
  END i_x0[28]
  PIN i_x0[29]
    DIRECTION INPUT ;
    USE SIGNAL ;
    PORT
      LAYER M5 ;
        RECT  9.984 0 10.008 0.084 ;
    END
  END i_x0[29]
  PIN i_x0[2]
    DIRECTION INPUT ;
    USE SIGNAL ;
    PORT
      LAYER M3 ;
        RECT  7.488 0 7.506 0.038 ;
    END
  END i_x0[2]
  PIN i_x0[30]
    DIRECTION INPUT ;
    USE SIGNAL ;
    PORT
      LAYER M3 ;
        RECT  10.08 0 10.098 0.038 ;
    END
  END i_x0[30]
  PIN i_x0[31]
    DIRECTION INPUT ;
    USE SIGNAL ;
    PORT
      LAYER M5 ;
        RECT  10.176 0 10.2 0.084 ;
    END
  END i_x0[31]
  PIN i_x0[32]
    DIRECTION INPUT ;
    USE SIGNAL ;
    PORT
      LAYER M3 ;
        RECT  10.26 0 10.278 0.038 ;
    END
  END i_x0[32]
  PIN i_x0[33]
    DIRECTION INPUT ;
    USE SIGNAL ;
    PORT
      LAYER M5 ;
        RECT  10.368 0 10.392 0.084 ;
    END
  END i_x0[33]
  PIN i_x0[34]
    DIRECTION INPUT ;
    USE SIGNAL ;
    PORT
      LAYER M3 ;
        RECT  10.476 0 10.494 0.038 ;
    END
  END i_x0[34]
  PIN i_x0[35]
    DIRECTION INPUT ;
    USE SIGNAL ;
    PORT
      LAYER M5 ;
        RECT  10.56 0 10.584 0.084 ;
    END
  END i_x0[35]
  PIN i_x0[36]
    DIRECTION INPUT ;
    USE SIGNAL ;
    PORT
      LAYER M3 ;
        RECT  10.656 0 10.674 0.038 ;
    END
  END i_x0[36]
  PIN i_x0[37]
    DIRECTION INPUT ;
    USE SIGNAL ;
    PORT
      LAYER M5 ;
        RECT  10.752 0 10.776 0.084 ;
    END
  END i_x0[37]
  PIN i_x0[38]
    DIRECTION INPUT ;
    USE SIGNAL ;
    PORT
      LAYER M3 ;
        RECT  10.836 0 10.854 0.038 ;
    END
  END i_x0[38]
  PIN i_x0[39]
    DIRECTION INPUT ;
    USE SIGNAL ;
    PORT
      LAYER M5 ;
        RECT  10.944 0 10.968 0.084 ;
    END
  END i_x0[39]
  PIN i_x0[3]
    DIRECTION INPUT ;
    USE SIGNAL ;
    PORT
      LAYER M5 ;
        RECT  7.584 0 7.608 0.084 ;
    END
  END i_x0[3]
  PIN i_x0[40]
    DIRECTION INPUT ;
    USE SIGNAL ;
    PORT
      LAYER M3 ;
        RECT  11.052 0 11.07 0.038 ;
    END
  END i_x0[40]
  PIN i_x0[41]
    DIRECTION INPUT ;
    USE SIGNAL ;
    PORT
      LAYER M5 ;
        RECT  11.136 0 11.16 0.084 ;
    END
  END i_x0[41]
  PIN i_x0[42]
    DIRECTION INPUT ;
    USE SIGNAL ;
    PORT
      LAYER M3 ;
        RECT  11.232 0 11.25 0.038 ;
    END
  END i_x0[42]
  PIN i_x0[43]
    DIRECTION INPUT ;
    USE SIGNAL ;
    PORT
      LAYER M5 ;
        RECT  11.328 0 11.352 0.084 ;
    END
  END i_x0[43]
  PIN i_x0[44]
    DIRECTION INPUT ;
    USE SIGNAL ;
    PORT
      LAYER M3 ;
        RECT  11.376 0 11.394 0.038 ;
    END
  END i_x0[44]
  PIN i_x0[45]
    DIRECTION INPUT ;
    USE SIGNAL ;
    PORT
      LAYER M5 ;
        RECT  11.472 0 11.496 0.084 ;
    END
  END i_x0[45]
  PIN i_x0[46]
    DIRECTION INPUT ;
    USE SIGNAL ;
    PORT
      LAYER M3 ;
        RECT  11.556 0 11.574 0.038 ;
    END
  END i_x0[46]
  PIN i_x0[47]
    DIRECTION INPUT ;
    USE SIGNAL ;
    PORT
      LAYER M5 ;
        RECT  11.664 0 11.688 0.084 ;
    END
  END i_x0[47]
  PIN i_x0[48]
    DIRECTION INPUT ;
    USE SIGNAL ;
    PORT
      LAYER M3 ;
        RECT  11.772 0 11.79 0.038 ;
    END
  END i_x0[48]
  PIN i_x0[49]
    DIRECTION INPUT ;
    USE SIGNAL ;
    PORT
      LAYER M5 ;
        RECT  11.856 0 11.88 0.084 ;
    END
  END i_x0[49]
  PIN i_x0[4]
    DIRECTION INPUT ;
    USE SIGNAL ;
    PORT
      LAYER M3 ;
        RECT  7.668 0 7.686 0.038 ;
    END
  END i_x0[4]
  PIN i_x0[50]
    DIRECTION INPUT ;
    USE SIGNAL ;
    PORT
      LAYER M3 ;
        RECT  11.952 0 11.97 0.038 ;
    END
  END i_x0[50]
  PIN i_x0[51]
    DIRECTION INPUT ;
    USE SIGNAL ;
    PORT
      LAYER M5 ;
        RECT  12.048 0 12.072 0.084 ;
    END
  END i_x0[51]
  PIN i_x0[52]
    DIRECTION INPUT ;
    USE SIGNAL ;
    PORT
      LAYER M3 ;
        RECT  12.132 0 12.15 0.038 ;
    END
  END i_x0[52]
  PIN i_x0[53]
    DIRECTION INPUT ;
    USE SIGNAL ;
    PORT
      LAYER M5 ;
        RECT  12.24 0 12.264 0.084 ;
    END
  END i_x0[53]
  PIN i_x0[54]
    DIRECTION INPUT ;
    USE SIGNAL ;
    PORT
      LAYER M3 ;
        RECT  12.348 0 12.366 0.038 ;
    END
  END i_x0[54]
  PIN i_x0[55]
    DIRECTION INPUT ;
    USE SIGNAL ;
    PORT
      LAYER M5 ;
        RECT  12.432 0 12.456 0.084 ;
    END
  END i_x0[55]
  PIN i_x0[56]
    DIRECTION INPUT ;
    USE SIGNAL ;
    PORT
      LAYER M3 ;
        RECT  12.528 0 12.546 0.038 ;
    END
  END i_x0[56]
  PIN i_x0[57]
    DIRECTION INPUT ;
    USE SIGNAL ;
    PORT
      LAYER M5 ;
        RECT  12.624 0 12.648 0.084 ;
    END
  END i_x0[57]
  PIN i_x0[58]
    DIRECTION INPUT ;
    USE SIGNAL ;
    PORT
      LAYER M3 ;
        RECT  12.708 0 12.726 0.038 ;
    END
  END i_x0[58]
  PIN i_x0[59]
    DIRECTION INPUT ;
    USE SIGNAL ;
    PORT
      LAYER M5 ;
        RECT  12.816 0 12.84 0.084 ;
    END
  END i_x0[59]
  PIN i_x0[5]
    DIRECTION INPUT ;
    USE SIGNAL ;
    PORT
      LAYER M5 ;
        RECT  7.776 0 7.8 0.084 ;
    END
  END i_x0[5]
  PIN i_x0[60]
    DIRECTION INPUT ;
    USE SIGNAL ;
    PORT
      LAYER M3 ;
        RECT  12.852 0 12.87 0.038 ;
    END
  END i_x0[60]
  PIN i_x0[61]
    DIRECTION INPUT ;
    USE SIGNAL ;
    PORT
      LAYER M5 ;
        RECT  12.96 0 12.984 0.084 ;
    END
  END i_x0[61]
  PIN i_x0[62]
    DIRECTION INPUT ;
    USE SIGNAL ;
    PORT
      LAYER M3 ;
        RECT  13.068 0 13.086 0.038 ;
    END
  END i_x0[62]
  PIN i_x0[63]
    DIRECTION INPUT ;
    USE SIGNAL ;
    PORT
      LAYER M5 ;
        RECT  13.152 0 13.176 0.084 ;
    END
  END i_x0[63]
  PIN i_x0[64]
    DIRECTION INPUT ;
    USE SIGNAL ;
    PORT
      LAYER M3 ;
        RECT  13.248 0 13.266 0.038 ;
    END
  END i_x0[64]
  PIN i_x0[65]
    DIRECTION INPUT ;
    USE SIGNAL ;
    PORT
      LAYER M5 ;
        RECT  13.344 0 13.368 0.084 ;
    END
  END i_x0[65]
  PIN i_x0[66]
    DIRECTION INPUT ;
    USE SIGNAL ;
    PORT
      LAYER M3 ;
        RECT  13.428 0 13.446 0.038 ;
    END
  END i_x0[66]
  PIN i_x0[67]
    DIRECTION INPUT ;
    USE SIGNAL ;
    PORT
      LAYER M5 ;
        RECT  13.536 0 13.56 0.084 ;
    END
  END i_x0[67]
  PIN i_x0[68]
    DIRECTION INPUT ;
    USE SIGNAL ;
    PORT
      LAYER M3 ;
        RECT  13.644 0 13.662 0.038 ;
    END
  END i_x0[68]
  PIN i_x0[69]
    DIRECTION INPUT ;
    USE SIGNAL ;
    PORT
      LAYER M5 ;
        RECT  13.728 0 13.752 0.084 ;
    END
  END i_x0[69]
  PIN i_x0[6]
    DIRECTION INPUT ;
    USE SIGNAL ;
    PORT
      LAYER M3 ;
        RECT  7.884 0 7.902 0.038 ;
    END
  END i_x0[6]
  PIN i_x0[70]
    DIRECTION INPUT ;
    USE SIGNAL ;
    PORT
      LAYER M3 ;
        RECT  13.824 0 13.842 0.038 ;
    END
  END i_x0[70]
  PIN i_x0[71]
    DIRECTION INPUT ;
    USE SIGNAL ;
    PORT
      LAYER M5 ;
        RECT  13.92 0 13.944 0.084 ;
    END
  END i_x0[71]
  PIN i_x0[72]
    DIRECTION INPUT ;
    USE SIGNAL ;
    PORT
      LAYER M3 ;
        RECT  14.004 0 14.022 0.038 ;
    END
  END i_x0[72]
  PIN i_x0[73]
    DIRECTION INPUT ;
    USE SIGNAL ;
    PORT
      LAYER M5 ;
        RECT  14.112 0 14.136 0.084 ;
    END
  END i_x0[73]
  PIN i_x0[74]
    DIRECTION INPUT ;
    USE SIGNAL ;
    PORT
      LAYER M3 ;
        RECT  14.22 0 14.238 0.038 ;
    END
  END i_x0[74]
  PIN i_x0[75]
    DIRECTION INPUT ;
    USE SIGNAL ;
    PORT
      LAYER M5 ;
        RECT  14.304 0 14.328 0.084 ;
    END
  END i_x0[75]
  PIN i_x0[76]
    DIRECTION INPUT ;
    USE SIGNAL ;
    PORT
      LAYER M3 ;
        RECT  14.364 0 14.382 0.038 ;
    END
  END i_x0[76]
  PIN i_x0[77]
    DIRECTION INPUT ;
    USE SIGNAL ;
    PORT
      LAYER M5 ;
        RECT  14.448 0 14.472 0.084 ;
    END
  END i_x0[77]
  PIN i_x0[78]
    DIRECTION INPUT ;
    USE SIGNAL ;
    PORT
      LAYER M3 ;
        RECT  14.544 0 14.562 0.038 ;
    END
  END i_x0[78]
  PIN i_x0[79]
    DIRECTION INPUT ;
    USE SIGNAL ;
    PORT
      LAYER M5 ;
        RECT  14.64 0 14.664 0.084 ;
    END
  END i_x0[79]
  PIN i_x0[7]
    DIRECTION INPUT ;
    USE SIGNAL ;
    PORT
      LAYER M5 ;
        RECT  7.968 0 7.992 0.084 ;
    END
  END i_x0[7]
  PIN i_x0[80]
    DIRECTION INPUT ;
    USE SIGNAL ;
    PORT
      LAYER M3 ;
        RECT  14.724 0 14.742 0.038 ;
    END
  END i_x0[80]
  PIN i_x0[81]
    DIRECTION INPUT ;
    USE SIGNAL ;
    PORT
      LAYER M5 ;
        RECT  14.832 0 14.856 0.084 ;
    END
  END i_x0[81]
  PIN i_x0[82]
    DIRECTION INPUT ;
    USE SIGNAL ;
    PORT
      LAYER M3 ;
        RECT  14.94 0 14.958 0.038 ;
    END
  END i_x0[82]
  PIN i_x0[83]
    DIRECTION INPUT ;
    USE SIGNAL ;
    PORT
      LAYER M5 ;
        RECT  15.024 0 15.048 0.084 ;
    END
  END i_x0[83]
  PIN i_x0[84]
    DIRECTION INPUT ;
    USE SIGNAL ;
    PORT
      LAYER M3 ;
        RECT  15.12 0 15.138 0.038 ;
    END
  END i_x0[84]
  PIN i_x0[85]
    DIRECTION INPUT ;
    USE SIGNAL ;
    PORT
      LAYER M5 ;
        RECT  15.216 0 15.24 0.084 ;
    END
  END i_x0[85]
  PIN i_x0[86]
    DIRECTION INPUT ;
    USE SIGNAL ;
    PORT
      LAYER M3 ;
        RECT  15.3 0 15.318 0.038 ;
    END
  END i_x0[86]
  PIN i_x0[87]
    DIRECTION INPUT ;
    USE SIGNAL ;
    PORT
      LAYER M5 ;
        RECT  15.408 0 15.432 0.084 ;
    END
  END i_x0[87]
  PIN i_x0[88]
    DIRECTION INPUT ;
    USE SIGNAL ;
    PORT
      LAYER M3 ;
        RECT  15.516 0 15.534 0.038 ;
    END
  END i_x0[88]
  PIN i_x0[89]
    DIRECTION INPUT ;
    USE SIGNAL ;
    PORT
      LAYER M5 ;
        RECT  15.6 0 15.624 0.084 ;
    END
  END i_x0[89]
  PIN i_x0[8]
    DIRECTION INPUT ;
    USE SIGNAL ;
    PORT
      LAYER M3 ;
        RECT  8.064 0 8.082 0.038 ;
    END
  END i_x0[8]
  PIN i_x0[90]
    DIRECTION INPUT ;
    USE SIGNAL ;
    PORT
      LAYER M3 ;
        RECT  15.696 0 15.714 0.038 ;
    END
  END i_x0[90]
  PIN i_x0[91]
    DIRECTION INPUT ;
    USE SIGNAL ;
    PORT
      LAYER M5 ;
        RECT  15.792 0 15.816 0.084 ;
    END
  END i_x0[91]
  PIN i_x0[92]
    DIRECTION INPUT ;
    USE SIGNAL ;
    PORT
      LAYER M3 ;
        RECT  15.84 0 15.858 0.038 ;
    END
  END i_x0[92]
  PIN i_x0[93]
    DIRECTION INPUT ;
    USE SIGNAL ;
    PORT
      LAYER M5 ;
        RECT  15.936 0 15.96 0.084 ;
    END
  END i_x0[93]
  PIN i_x0[94]
    DIRECTION INPUT ;
    USE SIGNAL ;
    PORT
      LAYER M3 ;
        RECT  16.02 0 16.038 0.038 ;
    END
  END i_x0[94]
  PIN i_x0[95]
    DIRECTION INPUT ;
    USE SIGNAL ;
    PORT
      LAYER M5 ;
        RECT  16.128 0 16.152 0.084 ;
    END
  END i_x0[95]
  PIN i_x0[96]
    DIRECTION INPUT ;
    USE SIGNAL ;
    PORT
      LAYER M3 ;
        RECT  16.236 0 16.254 0.038 ;
    END
  END i_x0[96]
  PIN i_x0[97]
    DIRECTION INPUT ;
    USE SIGNAL ;
    PORT
      LAYER M5 ;
        RECT  16.32 0 16.344 0.084 ;
    END
  END i_x0[97]
  PIN i_x0[98]
    DIRECTION INPUT ;
    USE SIGNAL ;
    PORT
      LAYER M3 ;
        RECT  16.416 0 16.434 0.038 ;
    END
  END i_x0[98]
  PIN i_x0[99]
    DIRECTION INPUT ;
    USE SIGNAL ;
    PORT
      LAYER M5 ;
        RECT  16.512 0 16.536 0.084 ;
    END
  END i_x0[99]
  PIN i_x0[9]
    DIRECTION INPUT ;
    USE SIGNAL ;
    PORT
      LAYER M5 ;
        RECT  8.16 0 8.184 0.084 ;
    END
  END i_x0[9]
  PIN i_x1[0]
    DIRECTION INPUT ;
    USE SIGNAL ;
    PORT
      LAYER M5 ;
        RECT  33.6 0 33.624 0.084 ;
    END
  END i_x1[0]
  PIN i_x1[100]
    DIRECTION INPUT ;
    USE SIGNAL ;
    PORT
      LAYER M5 ;
        RECT  42.912 0 42.936 0.084 ;
    END
  END i_x1[100]
  PIN i_x1[101]
    DIRECTION INPUT ;
    USE SIGNAL ;
    PORT
      LAYER M3 ;
        RECT  43.02 0 43.038 0.038 ;
    END
  END i_x1[101]
  PIN i_x1[102]
    DIRECTION INPUT ;
    USE SIGNAL ;
    PORT
      LAYER M5 ;
        RECT  43.104 0 43.128 0.084 ;
    END
  END i_x1[102]
  PIN i_x1[103]
    DIRECTION INPUT ;
    USE SIGNAL ;
    PORT
      LAYER M3 ;
        RECT  43.2 0 43.218 0.038 ;
    END
  END i_x1[103]
  PIN i_x1[104]
    DIRECTION INPUT ;
    USE SIGNAL ;
    PORT
      LAYER M5 ;
        RECT  43.296 0 43.32 0.084 ;
    END
  END i_x1[104]
  PIN i_x1[105]
    DIRECTION INPUT ;
    USE SIGNAL ;
    PORT
      LAYER M3 ;
        RECT  43.38 0 43.398 0.038 ;
    END
  END i_x1[105]
  PIN i_x1[106]
    DIRECTION INPUT ;
    USE SIGNAL ;
    PORT
      LAYER M5 ;
        RECT  43.488 0 43.512 0.084 ;
    END
  END i_x1[106]
  PIN i_x1[107]
    DIRECTION INPUT ;
    USE SIGNAL ;
    PORT
      LAYER M3 ;
        RECT  43.596 0 43.614 0.038 ;
    END
  END i_x1[107]
  PIN i_x1[108]
    DIRECTION INPUT ;
    USE SIGNAL ;
    PORT
      LAYER M5 ;
        RECT  43.68 0 43.704 0.084 ;
    END
  END i_x1[108]
  PIN i_x1[109]
    DIRECTION INPUT ;
    USE SIGNAL ;
    PORT
      LAYER M3 ;
        RECT  43.776 0 43.794 0.038 ;
    END
  END i_x1[109]
  PIN i_x1[10]
    DIRECTION INPUT ;
    USE SIGNAL ;
    PORT
      LAYER M5 ;
        RECT  34.56 0 34.584 0.084 ;
    END
  END i_x1[10]
  PIN i_x1[110]
    DIRECTION INPUT ;
    USE SIGNAL ;
    PORT
      LAYER M5 ;
        RECT  43.872 0 43.896 0.084 ;
    END
  END i_x1[110]
  PIN i_x1[111]
    DIRECTION INPUT ;
    USE SIGNAL ;
    PORT
      LAYER M3 ;
        RECT  43.92 0 43.938 0.038 ;
    END
  END i_x1[111]
  PIN i_x1[112]
    DIRECTION INPUT ;
    USE SIGNAL ;
    PORT
      LAYER M5 ;
        RECT  44.016 0 44.04 0.084 ;
    END
  END i_x1[112]
  PIN i_x1[113]
    DIRECTION INPUT ;
    USE SIGNAL ;
    PORT
      LAYER M3 ;
        RECT  44.1 0 44.118 0.038 ;
    END
  END i_x1[113]
  PIN i_x1[114]
    DIRECTION INPUT ;
    USE SIGNAL ;
    PORT
      LAYER M5 ;
        RECT  44.208 0 44.232 0.084 ;
    END
  END i_x1[114]
  PIN i_x1[115]
    DIRECTION INPUT ;
    USE SIGNAL ;
    PORT
      LAYER M3 ;
        RECT  44.316 0 44.334 0.038 ;
    END
  END i_x1[115]
  PIN i_x1[116]
    DIRECTION INPUT ;
    USE SIGNAL ;
    PORT
      LAYER M5 ;
        RECT  44.4 0 44.424 0.084 ;
    END
  END i_x1[116]
  PIN i_x1[117]
    DIRECTION INPUT ;
    USE SIGNAL ;
    PORT
      LAYER M3 ;
        RECT  44.496 0 44.514 0.038 ;
    END
  END i_x1[117]
  PIN i_x1[118]
    DIRECTION INPUT ;
    USE SIGNAL ;
    PORT
      LAYER M5 ;
        RECT  44.592 0 44.616 0.084 ;
    END
  END i_x1[118]
  PIN i_x1[119]
    DIRECTION INPUT ;
    USE SIGNAL ;
    PORT
      LAYER M3 ;
        RECT  44.676 0 44.694 0.038 ;
    END
  END i_x1[119]
  PIN i_x1[11]
    DIRECTION INPUT ;
    USE SIGNAL ;
    PORT
      LAYER M3 ;
        RECT  34.668 0 34.686 0.038 ;
    END
  END i_x1[11]
  PIN i_x1[120]
    DIRECTION INPUT ;
    USE SIGNAL ;
    PORT
      LAYER M5 ;
        RECT  44.784 0 44.808 0.084 ;
    END
  END i_x1[120]
  PIN i_x1[121]
    DIRECTION INPUT ;
    USE SIGNAL ;
    PORT
      LAYER M3 ;
        RECT  44.892 0 44.91 0.038 ;
    END
  END i_x1[121]
  PIN i_x1[122]
    DIRECTION INPUT ;
    USE SIGNAL ;
    PORT
      LAYER M5 ;
        RECT  44.976 0 45 0.084 ;
    END
  END i_x1[122]
  PIN i_x1[123]
    DIRECTION INPUT ;
    USE SIGNAL ;
    PORT
      LAYER M3 ;
        RECT  45.072 0 45.09 0.038 ;
    END
  END i_x1[123]
  PIN i_x1[124]
    DIRECTION INPUT ;
    USE SIGNAL ;
    PORT
      LAYER M5 ;
        RECT  45.168 0 45.192 0.084 ;
    END
  END i_x1[124]
  PIN i_x1[125]
    DIRECTION INPUT ;
    USE SIGNAL ;
    PORT
      LAYER M3 ;
        RECT  45.252 0 45.27 0.038 ;
    END
  END i_x1[125]
  PIN i_x1[126]
    DIRECTION INPUT ;
    USE SIGNAL ;
    PORT
      LAYER M5 ;
        RECT  45.36 0 45.384 0.084 ;
    END
  END i_x1[126]
  PIN i_x1[127]
    DIRECTION INPUT ;
    USE SIGNAL ;
    PORT
      LAYER M3 ;
        RECT  45.396 0 45.414 0.038 ;
    END
  END i_x1[127]
  PIN i_x1[128]
    DIRECTION INPUT ;
    USE SIGNAL ;
    PORT
      LAYER M5 ;
        RECT  45.504 0 45.528 0.084 ;
    END
  END i_x1[128]
  PIN i_x1[129]
    DIRECTION INPUT ;
    USE SIGNAL ;
    PORT
      LAYER M3 ;
        RECT  45.612 0 45.63 0.038 ;
    END
  END i_x1[129]
  PIN i_x1[12]
    DIRECTION INPUT ;
    USE SIGNAL ;
    PORT
      LAYER M5 ;
        RECT  34.752 0 34.776 0.084 ;
    END
  END i_x1[12]
  PIN i_x1[130]
    DIRECTION INPUT ;
    USE SIGNAL ;
    PORT
      LAYER M5 ;
        RECT  45.696 0 45.72 0.084 ;
    END
  END i_x1[130]
  PIN i_x1[131]
    DIRECTION INPUT ;
    USE SIGNAL ;
    PORT
      LAYER M3 ;
        RECT  45.792 0 45.81 0.038 ;
    END
  END i_x1[131]
  PIN i_x1[132]
    DIRECTION INPUT ;
    USE SIGNAL ;
    PORT
      LAYER M5 ;
        RECT  45.888 0 45.912 0.084 ;
    END
  END i_x1[132]
  PIN i_x1[133]
    DIRECTION INPUT ;
    USE SIGNAL ;
    PORT
      LAYER M3 ;
        RECT  45.972 0 45.99 0.038 ;
    END
  END i_x1[133]
  PIN i_x1[134]
    DIRECTION INPUT ;
    USE SIGNAL ;
    PORT
      LAYER M5 ;
        RECT  46.08 0 46.104 0.084 ;
    END
  END i_x1[134]
  PIN i_x1[135]
    DIRECTION INPUT ;
    USE SIGNAL ;
    PORT
      LAYER M3 ;
        RECT  46.188 0 46.206 0.038 ;
    END
  END i_x1[135]
  PIN i_x1[136]
    DIRECTION INPUT ;
    USE SIGNAL ;
    PORT
      LAYER M5 ;
        RECT  46.272 0 46.296 0.084 ;
    END
  END i_x1[136]
  PIN i_x1[137]
    DIRECTION INPUT ;
    USE SIGNAL ;
    PORT
      LAYER M3 ;
        RECT  46.368 0 46.386 0.038 ;
    END
  END i_x1[137]
  PIN i_x1[138]
    DIRECTION INPUT ;
    USE SIGNAL ;
    PORT
      LAYER M5 ;
        RECT  46.464 0 46.488 0.084 ;
    END
  END i_x1[138]
  PIN i_x1[139]
    DIRECTION INPUT ;
    USE SIGNAL ;
    PORT
      LAYER M3 ;
        RECT  46.548 0 46.566 0.038 ;
    END
  END i_x1[139]
  PIN i_x1[13]
    DIRECTION INPUT ;
    USE SIGNAL ;
    PORT
      LAYER M3 ;
        RECT  34.848 0 34.866 0.038 ;
    END
  END i_x1[13]
  PIN i_x1[140]
    DIRECTION INPUT ;
    USE SIGNAL ;
    PORT
      LAYER M5 ;
        RECT  46.656 0 46.68 0.084 ;
    END
  END i_x1[140]
  PIN i_x1[141]
    DIRECTION INPUT ;
    USE SIGNAL ;
    PORT
      LAYER M3 ;
        RECT  46.764 0 46.782 0.038 ;
    END
  END i_x1[141]
  PIN i_x1[142]
    DIRECTION INPUT ;
    USE SIGNAL ;
    PORT
      LAYER M5 ;
        RECT  46.848 0 46.872 0.084 ;
    END
  END i_x1[142]
  PIN i_x1[143]
    DIRECTION INPUT ;
    USE SIGNAL ;
    PORT
      LAYER M3 ;
        RECT  46.908 0 46.926 0.038 ;
    END
  END i_x1[143]
  PIN i_x1[144]
    DIRECTION INPUT ;
    USE SIGNAL ;
    PORT
      LAYER M5 ;
        RECT  46.992 0 47.016 0.084 ;
    END
  END i_x1[144]
  PIN i_x1[145]
    DIRECTION INPUT ;
    USE SIGNAL ;
    PORT
      LAYER M3 ;
        RECT  47.088 0 47.106 0.038 ;
    END
  END i_x1[145]
  PIN i_x1[146]
    DIRECTION INPUT ;
    USE SIGNAL ;
    PORT
      LAYER M5 ;
        RECT  47.184 0 47.208 0.084 ;
    END
  END i_x1[146]
  PIN i_x1[147]
    DIRECTION INPUT ;
    USE SIGNAL ;
    PORT
      LAYER M3 ;
        RECT  47.268 0 47.286 0.038 ;
    END
  END i_x1[147]
  PIN i_x1[148]
    DIRECTION INPUT ;
    USE SIGNAL ;
    PORT
      LAYER M5 ;
        RECT  47.376 0 47.4 0.084 ;
    END
  END i_x1[148]
  PIN i_x1[149]
    DIRECTION INPUT ;
    USE SIGNAL ;
    PORT
      LAYER M3 ;
        RECT  47.484 0 47.502 0.038 ;
    END
  END i_x1[149]
  PIN i_x1[14]
    DIRECTION INPUT ;
    USE SIGNAL ;
    PORT
      LAYER M5 ;
        RECT  34.944 0 34.968 0.084 ;
    END
  END i_x1[14]
  PIN i_x1[150]
    DIRECTION INPUT ;
    USE SIGNAL ;
    PORT
      LAYER M5 ;
        RECT  47.568 0 47.592 0.084 ;
    END
  END i_x1[150]
  PIN i_x1[151]
    DIRECTION INPUT ;
    USE SIGNAL ;
    PORT
      LAYER M3 ;
        RECT  47.664 0 47.682 0.038 ;
    END
  END i_x1[151]
  PIN i_x1[152]
    DIRECTION INPUT ;
    USE SIGNAL ;
    PORT
      LAYER M5 ;
        RECT  47.76 0 47.784 0.084 ;
    END
  END i_x1[152]
  PIN i_x1[153]
    DIRECTION INPUT ;
    USE SIGNAL ;
    PORT
      LAYER M3 ;
        RECT  47.844 0 47.862 0.038 ;
    END
  END i_x1[153]
  PIN i_x1[154]
    DIRECTION INPUT ;
    USE SIGNAL ;
    PORT
      LAYER M5 ;
        RECT  47.952 0 47.976 0.084 ;
    END
  END i_x1[154]
  PIN i_x1[155]
    DIRECTION INPUT ;
    USE SIGNAL ;
    PORT
      LAYER M3 ;
        RECT  48.06 0 48.078 0.038 ;
    END
  END i_x1[155]
  PIN i_x1[156]
    DIRECTION INPUT ;
    USE SIGNAL ;
    PORT
      LAYER M5 ;
        RECT  48.144 0 48.168 0.084 ;
    END
  END i_x1[156]
  PIN i_x1[157]
    DIRECTION INPUT ;
    USE SIGNAL ;
    PORT
      LAYER M3 ;
        RECT  48.24 0 48.258 0.038 ;
    END
  END i_x1[157]
  PIN i_x1[158]
    DIRECTION INPUT ;
    USE SIGNAL ;
    PORT
      LAYER M5 ;
        RECT  48.336 0 48.36 0.084 ;
    END
  END i_x1[158]
  PIN i_x1[159]
    DIRECTION INPUT ;
    USE SIGNAL ;
    PORT
      LAYER M3 ;
        RECT  48.384 0 48.402 0.038 ;
    END
  END i_x1[159]
  PIN i_x1[15]
    DIRECTION INPUT ;
    USE SIGNAL ;
    PORT
      LAYER M3 ;
        RECT  35.028 0 35.046 0.038 ;
    END
  END i_x1[15]
  PIN i_x1[160]
    DIRECTION INPUT ;
    USE SIGNAL ;
    PORT
      LAYER M5 ;
        RECT  48.48 0 48.504 0.084 ;
    END
  END i_x1[160]
  PIN i_x1[161]
    DIRECTION INPUT ;
    USE SIGNAL ;
    PORT
      LAYER M3 ;
        RECT  48.564 0 48.582 0.038 ;
    END
  END i_x1[161]
  PIN i_x1[162]
    DIRECTION INPUT ;
    USE SIGNAL ;
    PORT
      LAYER M5 ;
        RECT  48.672 0 48.696 0.084 ;
    END
  END i_x1[162]
  PIN i_x1[163]
    DIRECTION INPUT ;
    USE SIGNAL ;
    PORT
      LAYER M3 ;
        RECT  48.78 0 48.798 0.038 ;
    END
  END i_x1[163]
  PIN i_x1[164]
    DIRECTION INPUT ;
    USE SIGNAL ;
    PORT
      LAYER M5 ;
        RECT  48.864 0 48.888 0.084 ;
    END
  END i_x1[164]
  PIN i_x1[165]
    DIRECTION INPUT ;
    USE SIGNAL ;
    PORT
      LAYER M3 ;
        RECT  48.96 0 48.978 0.038 ;
    END
  END i_x1[165]
  PIN i_x1[166]
    DIRECTION INPUT ;
    USE SIGNAL ;
    PORT
      LAYER M5 ;
        RECT  49.056 0 49.08 0.084 ;
    END
  END i_x1[166]
  PIN i_x1[167]
    DIRECTION INPUT ;
    USE SIGNAL ;
    PORT
      LAYER M3 ;
        RECT  49.14 0 49.158 0.038 ;
    END
  END i_x1[167]
  PIN i_x1[168]
    DIRECTION INPUT ;
    USE SIGNAL ;
    PORT
      LAYER M5 ;
        RECT  49.248 0 49.272 0.084 ;
    END
  END i_x1[168]
  PIN i_x1[169]
    DIRECTION INPUT ;
    USE SIGNAL ;
    PORT
      LAYER M3 ;
        RECT  49.356 0 49.374 0.038 ;
    END
  END i_x1[169]
  PIN i_x1[16]
    DIRECTION INPUT ;
    USE SIGNAL ;
    PORT
      LAYER M5 ;
        RECT  35.088 0 35.112 0.084 ;
    END
  END i_x1[16]
  PIN i_x1[170]
    DIRECTION INPUT ;
    USE SIGNAL ;
    PORT
      LAYER M5 ;
        RECT  49.44 0 49.464 0.084 ;
    END
  END i_x1[170]
  PIN i_x1[171]
    DIRECTION INPUT ;
    USE SIGNAL ;
    PORT
      LAYER M3 ;
        RECT  49.536 0 49.554 0.038 ;
    END
  END i_x1[171]
  PIN i_x1[172]
    DIRECTION INPUT ;
    USE SIGNAL ;
    PORT
      LAYER M5 ;
        RECT  49.632 0 49.656 0.084 ;
    END
  END i_x1[172]
  PIN i_x1[173]
    DIRECTION INPUT ;
    USE SIGNAL ;
    PORT
      LAYER M3 ;
        RECT  49.716 0 49.734 0.038 ;
    END
  END i_x1[173]
  PIN i_x1[174]
    DIRECTION INPUT ;
    USE SIGNAL ;
    PORT
      LAYER M5 ;
        RECT  49.824 0 49.848 0.084 ;
    END
  END i_x1[174]
  PIN i_x1[175]
    DIRECTION INPUT ;
    USE SIGNAL ;
    PORT
      LAYER M3 ;
        RECT  49.86 0 49.878 0.038 ;
    END
  END i_x1[175]
  PIN i_x1[176]
    DIRECTION INPUT ;
    USE SIGNAL ;
    PORT
      LAYER M5 ;
        RECT  49.968 0 49.992 0.084 ;
    END
  END i_x1[176]
  PIN i_x1[177]
    DIRECTION INPUT ;
    USE SIGNAL ;
    PORT
      LAYER M3 ;
        RECT  50.076 0 50.094 0.038 ;
    END
  END i_x1[177]
  PIN i_x1[178]
    DIRECTION INPUT ;
    USE SIGNAL ;
    PORT
      LAYER M5 ;
        RECT  50.16 0 50.184 0.084 ;
    END
  END i_x1[178]
  PIN i_x1[179]
    DIRECTION INPUT ;
    USE SIGNAL ;
    PORT
      LAYER M3 ;
        RECT  50.256 0 50.274 0.038 ;
    END
  END i_x1[179]
  PIN i_x1[17]
    DIRECTION INPUT ;
    USE SIGNAL ;
    PORT
      LAYER M3 ;
        RECT  35.172 0 35.19 0.038 ;
    END
  END i_x1[17]
  PIN i_x1[180]
    DIRECTION INPUT ;
    USE SIGNAL ;
    PORT
      LAYER M5 ;
        RECT  50.352 0 50.376 0.084 ;
    END
  END i_x1[180]
  PIN i_x1[181]
    DIRECTION INPUT ;
    USE SIGNAL ;
    PORT
      LAYER M3 ;
        RECT  50.436 0 50.454 0.038 ;
    END
  END i_x1[181]
  PIN i_x1[182]
    DIRECTION INPUT ;
    USE SIGNAL ;
    PORT
      LAYER M5 ;
        RECT  50.544 0 50.568 0.084 ;
    END
  END i_x1[182]
  PIN i_x1[183]
    DIRECTION INPUT ;
    USE SIGNAL ;
    PORT
      LAYER M3 ;
        RECT  50.652 0 50.67 0.038 ;
    END
  END i_x1[183]
  PIN i_x1[184]
    DIRECTION INPUT ;
    USE SIGNAL ;
    PORT
      LAYER M5 ;
        RECT  50.736 0 50.76 0.084 ;
    END
  END i_x1[184]
  PIN i_x1[185]
    DIRECTION INPUT ;
    USE SIGNAL ;
    PORT
      LAYER M3 ;
        RECT  50.832 0 50.85 0.038 ;
    END
  END i_x1[185]
  PIN i_x1[186]
    DIRECTION INPUT ;
    USE SIGNAL ;
    PORT
      LAYER M5 ;
        RECT  50.928 0 50.952 0.084 ;
    END
  END i_x1[186]
  PIN i_x1[187]
    DIRECTION INPUT ;
    USE SIGNAL ;
    PORT
      LAYER M3 ;
        RECT  51.012 0 51.03 0.038 ;
    END
  END i_x1[187]
  PIN i_x1[188]
    DIRECTION INPUT ;
    USE SIGNAL ;
    PORT
      LAYER M5 ;
        RECT  51.12 0 51.144 0.084 ;
    END
  END i_x1[188]
  PIN i_x1[189]
    DIRECTION INPUT ;
    USE SIGNAL ;
    PORT
      LAYER M3 ;
        RECT  51.228 0 51.246 0.038 ;
    END
  END i_x1[189]
  PIN i_x1[18]
    DIRECTION INPUT ;
    USE SIGNAL ;
    PORT
      LAYER M5 ;
        RECT  35.28 0 35.304 0.084 ;
    END
  END i_x1[18]
  PIN i_x1[190]
    DIRECTION INPUT ;
    USE SIGNAL ;
    PORT
      LAYER M5 ;
        RECT  51.264 0 51.288 0.084 ;
    END
  END i_x1[190]
  PIN i_x1[191]
    DIRECTION INPUT ;
    USE SIGNAL ;
    PORT
      LAYER M3 ;
        RECT  51.372 0 51.39 0.038 ;
    END
  END i_x1[191]
  PIN i_x1[192]
    DIRECTION INPUT ;
    USE SIGNAL ;
    PORT
      LAYER M5 ;
        RECT  51.456 0 51.48 0.084 ;
    END
  END i_x1[192]
  PIN i_x1[193]
    DIRECTION INPUT ;
    USE SIGNAL ;
    PORT
      LAYER M3 ;
        RECT  51.552 0 51.57 0.038 ;
    END
  END i_x1[193]
  PIN i_x1[194]
    DIRECTION INPUT ;
    USE SIGNAL ;
    PORT
      LAYER M5 ;
        RECT  51.648 0 51.672 0.084 ;
    END
  END i_x1[194]
  PIN i_x1[195]
    DIRECTION INPUT ;
    USE SIGNAL ;
    PORT
      LAYER M3 ;
        RECT  51.732 0 51.75 0.038 ;
    END
  END i_x1[195]
  PIN i_x1[196]
    DIRECTION INPUT ;
    USE SIGNAL ;
    PORT
      LAYER M5 ;
        RECT  51.84 0 51.864 0.084 ;
    END
  END i_x1[196]
  PIN i_x1[197]
    DIRECTION INPUT ;
    USE SIGNAL ;
    PORT
      LAYER M3 ;
        RECT  51.948 0 51.966 0.038 ;
    END
  END i_x1[197]
  PIN i_x1[198]
    DIRECTION INPUT ;
    USE SIGNAL ;
    PORT
      LAYER M5 ;
        RECT  52.032 0 52.056 0.084 ;
    END
  END i_x1[198]
  PIN i_x1[199]
    DIRECTION INPUT ;
    USE SIGNAL ;
    PORT
      LAYER M3 ;
        RECT  52.128 0 52.146 0.038 ;
    END
  END i_x1[199]
  PIN i_x1[19]
    DIRECTION INPUT ;
    USE SIGNAL ;
    PORT
      LAYER M3 ;
        RECT  35.388 0 35.406 0.038 ;
    END
  END i_x1[19]
  PIN i_x1[1]
    DIRECTION INPUT ;
    USE SIGNAL ;
    PORT
      LAYER M3 ;
        RECT  33.696 0 33.714 0.038 ;
    END
  END i_x1[1]
  PIN i_x1[200]
    DIRECTION INPUT ;
    USE SIGNAL ;
    PORT
      LAYER M5 ;
        RECT  52.224 0 52.248 0.084 ;
    END
  END i_x1[200]
  PIN i_x1[201]
    DIRECTION INPUT ;
    USE SIGNAL ;
    PORT
      LAYER M3 ;
        RECT  52.308 0 52.326 0.038 ;
    END
  END i_x1[201]
  PIN i_x1[202]
    DIRECTION INPUT ;
    USE SIGNAL ;
    PORT
      LAYER M5 ;
        RECT  52.416 0 52.44 0.084 ;
    END
  END i_x1[202]
  PIN i_x1[203]
    DIRECTION INPUT ;
    USE SIGNAL ;
    PORT
      LAYER M3 ;
        RECT  52.524 0 52.542 0.038 ;
    END
  END i_x1[203]
  PIN i_x1[204]
    DIRECTION INPUT ;
    USE SIGNAL ;
    PORT
      LAYER M5 ;
        RECT  52.608 0 52.632 0.084 ;
    END
  END i_x1[204]
  PIN i_x1[205]
    DIRECTION INPUT ;
    USE SIGNAL ;
    PORT
      LAYER M3 ;
        RECT  52.704 0 52.722 0.038 ;
    END
  END i_x1[205]
  PIN i_x1[206]
    DIRECTION INPUT ;
    USE SIGNAL ;
    PORT
      LAYER M5 ;
        RECT  52.752 0 52.776 0.084 ;
    END
  END i_x1[206]
  PIN i_x1[207]
    DIRECTION INPUT ;
    USE SIGNAL ;
    PORT
      LAYER M3 ;
        RECT  52.848 0 52.866 0.038 ;
    END
  END i_x1[207]
  PIN i_x1[208]
    DIRECTION INPUT ;
    USE SIGNAL ;
    PORT
      LAYER M5 ;
        RECT  52.944 0 52.968 0.084 ;
    END
  END i_x1[208]
  PIN i_x1[209]
    DIRECTION INPUT ;
    USE SIGNAL ;
    PORT
      LAYER M3 ;
        RECT  53.028 0 53.046 0.038 ;
    END
  END i_x1[209]
  PIN i_x1[20]
    DIRECTION INPUT ;
    USE SIGNAL ;
    PORT
      LAYER M5 ;
        RECT  35.472 0 35.496 0.084 ;
    END
  END i_x1[20]
  PIN i_x1[210]
    DIRECTION INPUT ;
    USE SIGNAL ;
    PORT
      LAYER M5 ;
        RECT  53.136 0 53.16 0.084 ;
    END
  END i_x1[210]
  PIN i_x1[211]
    DIRECTION INPUT ;
    USE SIGNAL ;
    PORT
      LAYER M3 ;
        RECT  53.244 0 53.262 0.038 ;
    END
  END i_x1[211]
  PIN i_x1[212]
    DIRECTION INPUT ;
    USE SIGNAL ;
    PORT
      LAYER M5 ;
        RECT  53.328 0 53.352 0.084 ;
    END
  END i_x1[212]
  PIN i_x1[213]
    DIRECTION INPUT ;
    USE SIGNAL ;
    PORT
      LAYER M3 ;
        RECT  53.424 0 53.442 0.038 ;
    END
  END i_x1[213]
  PIN i_x1[214]
    DIRECTION INPUT ;
    USE SIGNAL ;
    PORT
      LAYER M5 ;
        RECT  53.52 0 53.544 0.084 ;
    END
  END i_x1[214]
  PIN i_x1[215]
    DIRECTION INPUT ;
    USE SIGNAL ;
    PORT
      LAYER M3 ;
        RECT  53.604 0 53.622 0.038 ;
    END
  END i_x1[215]
  PIN i_x1[216]
    DIRECTION INPUT ;
    USE SIGNAL ;
    PORT
      LAYER M5 ;
        RECT  53.712 0 53.736 0.084 ;
    END
  END i_x1[216]
  PIN i_x1[217]
    DIRECTION INPUT ;
    USE SIGNAL ;
    PORT
      LAYER M3 ;
        RECT  53.82 0 53.838 0.038 ;
    END
  END i_x1[217]
  PIN i_x1[218]
    DIRECTION INPUT ;
    USE SIGNAL ;
    PORT
      LAYER M5 ;
        RECT  53.904 0 53.928 0.084 ;
    END
  END i_x1[218]
  PIN i_x1[219]
    DIRECTION INPUT ;
    USE SIGNAL ;
    PORT
      LAYER M3 ;
        RECT  54 0 54.018 0.038 ;
    END
  END i_x1[219]
  PIN i_x1[21]
    DIRECTION INPUT ;
    USE SIGNAL ;
    PORT
      LAYER M3 ;
        RECT  35.568 0 35.586 0.038 ;
    END
  END i_x1[21]
  PIN i_x1[220]
    DIRECTION INPUT ;
    USE SIGNAL ;
    PORT
      LAYER M5 ;
        RECT  54.096 0 54.12 0.084 ;
    END
  END i_x1[220]
  PIN i_x1[221]
    DIRECTION INPUT ;
    USE SIGNAL ;
    PORT
      LAYER M3 ;
        RECT  54.18 0 54.198 0.038 ;
    END
  END i_x1[221]
  PIN i_x1[222]
    DIRECTION INPUT ;
    USE SIGNAL ;
    PORT
      LAYER M5 ;
        RECT  54.24 0 54.264 0.084 ;
    END
  END i_x1[222]
  PIN i_x1[223]
    DIRECTION INPUT ;
    USE SIGNAL ;
    PORT
      LAYER M3 ;
        RECT  54.324 0 54.342 0.038 ;
    END
  END i_x1[223]
  PIN i_x1[224]
    DIRECTION INPUT ;
    USE SIGNAL ;
    PORT
      LAYER M5 ;
        RECT  54.432 0 54.456 0.084 ;
    END
  END i_x1[224]
  PIN i_x1[225]
    DIRECTION INPUT ;
    USE SIGNAL ;
    PORT
      LAYER M3 ;
        RECT  54.54 0 54.558 0.038 ;
    END
  END i_x1[225]
  PIN i_x1[226]
    DIRECTION INPUT ;
    USE SIGNAL ;
    PORT
      LAYER M5 ;
        RECT  54.624 0 54.648 0.084 ;
    END
  END i_x1[226]
  PIN i_x1[227]
    DIRECTION INPUT ;
    USE SIGNAL ;
    PORT
      LAYER M3 ;
        RECT  54.72 0 54.738 0.038 ;
    END
  END i_x1[227]
  PIN i_x1[228]
    DIRECTION INPUT ;
    USE SIGNAL ;
    PORT
      LAYER M5 ;
        RECT  54.816 0 54.84 0.084 ;
    END
  END i_x1[228]
  PIN i_x1[229]
    DIRECTION INPUT ;
    USE SIGNAL ;
    PORT
      LAYER M3 ;
        RECT  54.9 0 54.918 0.038 ;
    END
  END i_x1[229]
  PIN i_x1[22]
    DIRECTION INPUT ;
    USE SIGNAL ;
    PORT
      LAYER M5 ;
        RECT  35.664 0 35.688 0.084 ;
    END
  END i_x1[22]
  PIN i_x1[230]
    DIRECTION INPUT ;
    USE SIGNAL ;
    PORT
      LAYER M5 ;
        RECT  55.008 0 55.032 0.084 ;
    END
  END i_x1[230]
  PIN i_x1[231]
    DIRECTION INPUT ;
    USE SIGNAL ;
    PORT
      LAYER M3 ;
        RECT  55.116 0 55.134 0.038 ;
    END
  END i_x1[231]
  PIN i_x1[232]
    DIRECTION INPUT ;
    USE SIGNAL ;
    PORT
      LAYER M5 ;
        RECT  55.2 0 55.224 0.084 ;
    END
  END i_x1[232]
  PIN i_x1[233]
    DIRECTION INPUT ;
    USE SIGNAL ;
    PORT
      LAYER M3 ;
        RECT  55.296 0 55.314 0.038 ;
    END
  END i_x1[233]
  PIN i_x1[234]
    DIRECTION INPUT ;
    USE SIGNAL ;
    PORT
      LAYER M5 ;
        RECT  55.392 0 55.416 0.084 ;
    END
  END i_x1[234]
  PIN i_x1[235]
    DIRECTION INPUT ;
    USE SIGNAL ;
    PORT
      LAYER M3 ;
        RECT  55.476 0 55.494 0.038 ;
    END
  END i_x1[235]
  PIN i_x1[236]
    DIRECTION INPUT ;
    USE SIGNAL ;
    PORT
      LAYER M5 ;
        RECT  55.584 0 55.608 0.084 ;
    END
  END i_x1[236]
  PIN i_x1[237]
    DIRECTION INPUT ;
    USE SIGNAL ;
    PORT
      LAYER M3 ;
        RECT  55.692 0 55.71 0.038 ;
    END
  END i_x1[237]
  PIN i_x1[238]
    DIRECTION INPUT ;
    USE SIGNAL ;
    PORT
      LAYER M5 ;
        RECT  55.728 0 55.752 0.084 ;
    END
  END i_x1[238]
  PIN i_x1[239]
    DIRECTION INPUT ;
    USE SIGNAL ;
    PORT
      LAYER M3 ;
        RECT  55.836 0 55.854 0.038 ;
    END
  END i_x1[239]
  PIN i_x1[23]
    DIRECTION INPUT ;
    USE SIGNAL ;
    PORT
      LAYER M3 ;
        RECT  35.748 0 35.766 0.038 ;
    END
  END i_x1[23]
  PIN i_x1[240]
    DIRECTION INPUT ;
    USE SIGNAL ;
    PORT
      LAYER M5 ;
        RECT  55.92 0 55.944 0.084 ;
    END
  END i_x1[240]
  PIN i_x1[241]
    DIRECTION INPUT ;
    USE SIGNAL ;
    PORT
      LAYER M3 ;
        RECT  56.016 0 56.034 0.038 ;
    END
  END i_x1[241]
  PIN i_x1[242]
    DIRECTION INPUT ;
    USE SIGNAL ;
    PORT
      LAYER M5 ;
        RECT  56.112 0 56.136 0.084 ;
    END
  END i_x1[242]
  PIN i_x1[243]
    DIRECTION INPUT ;
    USE SIGNAL ;
    PORT
      LAYER M3 ;
        RECT  56.196 0 56.214 0.038 ;
    END
  END i_x1[243]
  PIN i_x1[244]
    DIRECTION INPUT ;
    USE SIGNAL ;
    PORT
      LAYER M5 ;
        RECT  56.304 0 56.328 0.084 ;
    END
  END i_x1[244]
  PIN i_x1[245]
    DIRECTION INPUT ;
    USE SIGNAL ;
    PORT
      LAYER M3 ;
        RECT  56.412 0 56.43 0.038 ;
    END
  END i_x1[245]
  PIN i_x1[246]
    DIRECTION INPUT ;
    USE SIGNAL ;
    PORT
      LAYER M5 ;
        RECT  56.496 0 56.52 0.084 ;
    END
  END i_x1[246]
  PIN i_x1[247]
    DIRECTION INPUT ;
    USE SIGNAL ;
    PORT
      LAYER M3 ;
        RECT  56.592 0 56.61 0.038 ;
    END
  END i_x1[247]
  PIN i_x1[248]
    DIRECTION INPUT ;
    USE SIGNAL ;
    PORT
      LAYER M5 ;
        RECT  56.688 0 56.712 0.084 ;
    END
  END i_x1[248]
  PIN i_x1[249]
    DIRECTION INPUT ;
    USE SIGNAL ;
    PORT
      LAYER M3 ;
        RECT  56.772 0 56.79 0.038 ;
    END
  END i_x1[249]
  PIN i_x1[24]
    DIRECTION INPUT ;
    USE SIGNAL ;
    PORT
      LAYER M5 ;
        RECT  35.856 0 35.88 0.084 ;
    END
  END i_x1[24]
  PIN i_x1[250]
    DIRECTION INPUT ;
    USE SIGNAL ;
    PORT
      LAYER M5 ;
        RECT  56.88 0 56.904 0.084 ;
    END
  END i_x1[250]
  PIN i_x1[251]
    DIRECTION INPUT ;
    USE SIGNAL ;
    PORT
      LAYER M3 ;
        RECT  56.988 0 57.006 0.038 ;
    END
  END i_x1[251]
  PIN i_x1[252]
    DIRECTION INPUT ;
    USE SIGNAL ;
    PORT
      LAYER M5 ;
        RECT  57.072 0 57.096 0.084 ;
    END
  END i_x1[252]
  PIN i_x1[253]
    DIRECTION INPUT ;
    USE SIGNAL ;
    PORT
      LAYER M3 ;
        RECT  57.168 0 57.186 0.038 ;
    END
  END i_x1[253]
  PIN i_x1[254]
    DIRECTION INPUT ;
    USE SIGNAL ;
    PORT
      LAYER M5 ;
        RECT  57.216 0 57.24 0.084 ;
    END
  END i_x1[254]
  PIN i_x1[255]
    DIRECTION INPUT ;
    USE SIGNAL ;
    PORT
      LAYER M3 ;
        RECT  57.312 0 57.33 0.038 ;
    END
  END i_x1[255]
  PIN i_x1[256]
    DIRECTION INPUT ;
    USE SIGNAL ;
    PORT
      LAYER M5 ;
        RECT  57.408 0 57.432 0.084 ;
    END
  END i_x1[256]
  PIN i_x1[257]
    DIRECTION INPUT ;
    USE SIGNAL ;
    PORT
      LAYER M3 ;
        RECT  57.492 0 57.51 0.038 ;
    END
  END i_x1[257]
  PIN i_x1[258]
    DIRECTION INPUT ;
    USE SIGNAL ;
    PORT
      LAYER M5 ;
        RECT  57.6 0 57.624 0.084 ;
    END
  END i_x1[258]
  PIN i_x1[259]
    DIRECTION INPUT ;
    USE SIGNAL ;
    PORT
      LAYER M3 ;
        RECT  57.708 0 57.726 0.038 ;
    END
  END i_x1[259]
  PIN i_x1[25]
    DIRECTION INPUT ;
    USE SIGNAL ;
    PORT
      LAYER M3 ;
        RECT  35.964 0 35.982 0.038 ;
    END
  END i_x1[25]
  PIN i_x1[260]
    DIRECTION INPUT ;
    USE SIGNAL ;
    PORT
      LAYER M5 ;
        RECT  57.792 0 57.816 0.084 ;
    END
  END i_x1[260]
  PIN i_x1[261]
    DIRECTION INPUT ;
    USE SIGNAL ;
    PORT
      LAYER M3 ;
        RECT  57.888 0 57.906 0.038 ;
    END
  END i_x1[261]
  PIN i_x1[262]
    DIRECTION INPUT ;
    USE SIGNAL ;
    PORT
      LAYER M5 ;
        RECT  57.984 0 58.008 0.084 ;
    END
  END i_x1[262]
  PIN i_x1[263]
    DIRECTION INPUT ;
    USE SIGNAL ;
    PORT
      LAYER M3 ;
        RECT  58.068 0 58.086 0.038 ;
    END
  END i_x1[263]
  PIN i_x1[264]
    DIRECTION INPUT ;
    USE SIGNAL ;
    PORT
      LAYER M5 ;
        RECT  58.176 0 58.2 0.084 ;
    END
  END i_x1[264]
  PIN i_x1[265]
    DIRECTION INPUT ;
    USE SIGNAL ;
    PORT
      LAYER M3 ;
        RECT  58.284 0 58.302 0.038 ;
    END
  END i_x1[265]
  PIN i_x1[26]
    DIRECTION INPUT ;
    USE SIGNAL ;
    PORT
      LAYER M5 ;
        RECT  36.048 0 36.072 0.084 ;
    END
  END i_x1[26]
  PIN i_x1[27]
    DIRECTION INPUT ;
    USE SIGNAL ;
    PORT
      LAYER M3 ;
        RECT  36.144 0 36.162 0.038 ;
    END
  END i_x1[27]
  PIN i_x1[28]
    DIRECTION INPUT ;
    USE SIGNAL ;
    PORT
      LAYER M5 ;
        RECT  36.24 0 36.264 0.084 ;
    END
  END i_x1[28]
  PIN i_x1[29]
    DIRECTION INPUT ;
    USE SIGNAL ;
    PORT
      LAYER M3 ;
        RECT  36.324 0 36.342 0.038 ;
    END
  END i_x1[29]
  PIN i_x1[2]
    DIRECTION INPUT ;
    USE SIGNAL ;
    PORT
      LAYER M5 ;
        RECT  33.792 0 33.816 0.084 ;
    END
  END i_x1[2]
  PIN i_x1[30]
    DIRECTION INPUT ;
    USE SIGNAL ;
    PORT
      LAYER M5 ;
        RECT  36.432 0 36.456 0.084 ;
    END
  END i_x1[30]
  PIN i_x1[31]
    DIRECTION INPUT ;
    USE SIGNAL ;
    PORT
      LAYER M3 ;
        RECT  36.54 0 36.558 0.038 ;
    END
  END i_x1[31]
  PIN i_x1[32]
    DIRECTION INPUT ;
    USE SIGNAL ;
    PORT
      LAYER M5 ;
        RECT  36.576 0 36.6 0.084 ;
    END
  END i_x1[32]
  PIN i_x1[33]
    DIRECTION INPUT ;
    USE SIGNAL ;
    PORT
      LAYER M3 ;
        RECT  36.684 0 36.702 0.038 ;
    END
  END i_x1[33]
  PIN i_x1[34]
    DIRECTION INPUT ;
    USE SIGNAL ;
    PORT
      LAYER M5 ;
        RECT  36.768 0 36.792 0.084 ;
    END
  END i_x1[34]
  PIN i_x1[35]
    DIRECTION INPUT ;
    USE SIGNAL ;
    PORT
      LAYER M3 ;
        RECT  36.864 0 36.882 0.038 ;
    END
  END i_x1[35]
  PIN i_x1[36]
    DIRECTION INPUT ;
    USE SIGNAL ;
    PORT
      LAYER M5 ;
        RECT  36.96 0 36.984 0.084 ;
    END
  END i_x1[36]
  PIN i_x1[37]
    DIRECTION INPUT ;
    USE SIGNAL ;
    PORT
      LAYER M3 ;
        RECT  37.044 0 37.062 0.038 ;
    END
  END i_x1[37]
  PIN i_x1[38]
    DIRECTION INPUT ;
    USE SIGNAL ;
    PORT
      LAYER M5 ;
        RECT  37.152 0 37.176 0.084 ;
    END
  END i_x1[38]
  PIN i_x1[39]
    DIRECTION INPUT ;
    USE SIGNAL ;
    PORT
      LAYER M3 ;
        RECT  37.26 0 37.278 0.038 ;
    END
  END i_x1[39]
  PIN i_x1[3]
    DIRECTION INPUT ;
    USE SIGNAL ;
    PORT
      LAYER M3 ;
        RECT  33.876 0 33.894 0.038 ;
    END
  END i_x1[3]
  PIN i_x1[40]
    DIRECTION INPUT ;
    USE SIGNAL ;
    PORT
      LAYER M5 ;
        RECT  37.344 0 37.368 0.084 ;
    END
  END i_x1[40]
  PIN i_x1[41]
    DIRECTION INPUT ;
    USE SIGNAL ;
    PORT
      LAYER M3 ;
        RECT  37.44 0 37.458 0.038 ;
    END
  END i_x1[41]
  PIN i_x1[42]
    DIRECTION INPUT ;
    USE SIGNAL ;
    PORT
      LAYER M5 ;
        RECT  37.536 0 37.56 0.084 ;
    END
  END i_x1[42]
  PIN i_x1[43]
    DIRECTION INPUT ;
    USE SIGNAL ;
    PORT
      LAYER M3 ;
        RECT  37.62 0 37.638 0.038 ;
    END
  END i_x1[43]
  PIN i_x1[44]
    DIRECTION INPUT ;
    USE SIGNAL ;
    PORT
      LAYER M5 ;
        RECT  37.728 0 37.752 0.084 ;
    END
  END i_x1[44]
  PIN i_x1[45]
    DIRECTION INPUT ;
    USE SIGNAL ;
    PORT
      LAYER M3 ;
        RECT  37.836 0 37.854 0.038 ;
    END
  END i_x1[45]
  PIN i_x1[46]
    DIRECTION INPUT ;
    USE SIGNAL ;
    PORT
      LAYER M5 ;
        RECT  37.92 0 37.944 0.084 ;
    END
  END i_x1[46]
  PIN i_x1[47]
    DIRECTION INPUT ;
    USE SIGNAL ;
    PORT
      LAYER M3 ;
        RECT  37.98 0 37.998 0.038 ;
    END
  END i_x1[47]
  PIN i_x1[48]
    DIRECTION INPUT ;
    USE SIGNAL ;
    PORT
      LAYER M5 ;
        RECT  38.064 0 38.088 0.084 ;
    END
  END i_x1[48]
  PIN i_x1[49]
    DIRECTION INPUT ;
    USE SIGNAL ;
    PORT
      LAYER M3 ;
        RECT  38.16 0 38.178 0.038 ;
    END
  END i_x1[49]
  PIN i_x1[4]
    DIRECTION INPUT ;
    USE SIGNAL ;
    PORT
      LAYER M5 ;
        RECT  33.984 0 34.008 0.084 ;
    END
  END i_x1[4]
  PIN i_x1[50]
    DIRECTION INPUT ;
    USE SIGNAL ;
    PORT
      LAYER M5 ;
        RECT  38.256 0 38.28 0.084 ;
    END
  END i_x1[50]
  PIN i_x1[51]
    DIRECTION INPUT ;
    USE SIGNAL ;
    PORT
      LAYER M3 ;
        RECT  38.34 0 38.358 0.038 ;
    END
  END i_x1[51]
  PIN i_x1[52]
    DIRECTION INPUT ;
    USE SIGNAL ;
    PORT
      LAYER M5 ;
        RECT  38.448 0 38.472 0.084 ;
    END
  END i_x1[52]
  PIN i_x1[53]
    DIRECTION INPUT ;
    USE SIGNAL ;
    PORT
      LAYER M3 ;
        RECT  38.556 0 38.574 0.038 ;
    END
  END i_x1[53]
  PIN i_x1[54]
    DIRECTION INPUT ;
    USE SIGNAL ;
    PORT
      LAYER M5 ;
        RECT  38.64 0 38.664 0.084 ;
    END
  END i_x1[54]
  PIN i_x1[55]
    DIRECTION INPUT ;
    USE SIGNAL ;
    PORT
      LAYER M3 ;
        RECT  38.736 0 38.754 0.038 ;
    END
  END i_x1[55]
  PIN i_x1[56]
    DIRECTION INPUT ;
    USE SIGNAL ;
    PORT
      LAYER M5 ;
        RECT  38.832 0 38.856 0.084 ;
    END
  END i_x1[56]
  PIN i_x1[57]
    DIRECTION INPUT ;
    USE SIGNAL ;
    PORT
      LAYER M3 ;
        RECT  38.916 0 38.934 0.038 ;
    END
  END i_x1[57]
  PIN i_x1[58]
    DIRECTION INPUT ;
    USE SIGNAL ;
    PORT
      LAYER M5 ;
        RECT  39.024 0 39.048 0.084 ;
    END
  END i_x1[58]
  PIN i_x1[59]
    DIRECTION INPUT ;
    USE SIGNAL ;
    PORT
      LAYER M3 ;
        RECT  39.132 0 39.15 0.038 ;
    END
  END i_x1[59]
  PIN i_x1[5]
    DIRECTION INPUT ;
    USE SIGNAL ;
    PORT
      LAYER M3 ;
        RECT  34.092 0 34.11 0.038 ;
    END
  END i_x1[5]
  PIN i_x1[60]
    DIRECTION INPUT ;
    USE SIGNAL ;
    PORT
      LAYER M5 ;
        RECT  39.216 0 39.24 0.084 ;
    END
  END i_x1[60]
  PIN i_x1[61]
    DIRECTION INPUT ;
    USE SIGNAL ;
    PORT
      LAYER M3 ;
        RECT  39.312 0 39.33 0.038 ;
    END
  END i_x1[61]
  PIN i_x1[62]
    DIRECTION INPUT ;
    USE SIGNAL ;
    PORT
      LAYER M5 ;
        RECT  39.408 0 39.432 0.084 ;
    END
  END i_x1[62]
  PIN i_x1[63]
    DIRECTION INPUT ;
    USE SIGNAL ;
    PORT
      LAYER M3 ;
        RECT  39.456 0 39.474 0.038 ;
    END
  END i_x1[63]
  PIN i_x1[64]
    DIRECTION INPUT ;
    USE SIGNAL ;
    PORT
      LAYER M5 ;
        RECT  39.552 0 39.576 0.084 ;
    END
  END i_x1[64]
  PIN i_x1[65]
    DIRECTION INPUT ;
    USE SIGNAL ;
    PORT
      LAYER M3 ;
        RECT  39.636 0 39.654 0.038 ;
    END
  END i_x1[65]
  PIN i_x1[66]
    DIRECTION INPUT ;
    USE SIGNAL ;
    PORT
      LAYER M5 ;
        RECT  39.744 0 39.768 0.084 ;
    END
  END i_x1[66]
  PIN i_x1[67]
    DIRECTION INPUT ;
    USE SIGNAL ;
    PORT
      LAYER M3 ;
        RECT  39.852 0 39.87 0.038 ;
    END
  END i_x1[67]
  PIN i_x1[68]
    DIRECTION INPUT ;
    USE SIGNAL ;
    PORT
      LAYER M5 ;
        RECT  39.936 0 39.96 0.084 ;
    END
  END i_x1[68]
  PIN i_x1[69]
    DIRECTION INPUT ;
    USE SIGNAL ;
    PORT
      LAYER M3 ;
        RECT  40.032 0 40.05 0.038 ;
    END
  END i_x1[69]
  PIN i_x1[6]
    DIRECTION INPUT ;
    USE SIGNAL ;
    PORT
      LAYER M5 ;
        RECT  34.176 0 34.2 0.084 ;
    END
  END i_x1[6]
  PIN i_x1[70]
    DIRECTION INPUT ;
    USE SIGNAL ;
    PORT
      LAYER M5 ;
        RECT  40.128 0 40.152 0.084 ;
    END
  END i_x1[70]
  PIN i_x1[71]
    DIRECTION INPUT ;
    USE SIGNAL ;
    PORT
      LAYER M3 ;
        RECT  40.212 0 40.23 0.038 ;
    END
  END i_x1[71]
  PIN i_x1[72]
    DIRECTION INPUT ;
    USE SIGNAL ;
    PORT
      LAYER M5 ;
        RECT  40.32 0 40.344 0.084 ;
    END
  END i_x1[72]
  PIN i_x1[73]
    DIRECTION INPUT ;
    USE SIGNAL ;
    PORT
      LAYER M3 ;
        RECT  40.428 0 40.446 0.038 ;
    END
  END i_x1[73]
  PIN i_x1[74]
    DIRECTION INPUT ;
    USE SIGNAL ;
    PORT
      LAYER M5 ;
        RECT  40.512 0 40.536 0.084 ;
    END
  END i_x1[74]
  PIN i_x1[75]
    DIRECTION INPUT ;
    USE SIGNAL ;
    PORT
      LAYER M3 ;
        RECT  40.608 0 40.626 0.038 ;
    END
  END i_x1[75]
  PIN i_x1[76]
    DIRECTION INPUT ;
    USE SIGNAL ;
    PORT
      LAYER M5 ;
        RECT  40.704 0 40.728 0.084 ;
    END
  END i_x1[76]
  PIN i_x1[77]
    DIRECTION INPUT ;
    USE SIGNAL ;
    PORT
      LAYER M3 ;
        RECT  40.788 0 40.806 0.038 ;
    END
  END i_x1[77]
  PIN i_x1[78]
    DIRECTION INPUT ;
    USE SIGNAL ;
    PORT
      LAYER M5 ;
        RECT  40.896 0 40.92 0.084 ;
    END
  END i_x1[78]
  PIN i_x1[79]
    DIRECTION INPUT ;
    USE SIGNAL ;
    PORT
      LAYER M3 ;
        RECT  40.932 0 40.95 0.038 ;
    END
  END i_x1[79]
  PIN i_x1[7]
    DIRECTION INPUT ;
    USE SIGNAL ;
    PORT
      LAYER M3 ;
        RECT  34.272 0 34.29 0.038 ;
    END
  END i_x1[7]
  PIN i_x1[80]
    DIRECTION INPUT ;
    USE SIGNAL ;
    PORT
      LAYER M5 ;
        RECT  41.04 0 41.064 0.084 ;
    END
  END i_x1[80]
  PIN i_x1[81]
    DIRECTION INPUT ;
    USE SIGNAL ;
    PORT
      LAYER M3 ;
        RECT  41.148 0 41.166 0.038 ;
    END
  END i_x1[81]
  PIN i_x1[82]
    DIRECTION INPUT ;
    USE SIGNAL ;
    PORT
      LAYER M5 ;
        RECT  41.232 0 41.256 0.084 ;
    END
  END i_x1[82]
  PIN i_x1[83]
    DIRECTION INPUT ;
    USE SIGNAL ;
    PORT
      LAYER M3 ;
        RECT  41.328 0 41.346 0.038 ;
    END
  END i_x1[83]
  PIN i_x1[84]
    DIRECTION INPUT ;
    USE SIGNAL ;
    PORT
      LAYER M5 ;
        RECT  41.424 0 41.448 0.084 ;
    END
  END i_x1[84]
  PIN i_x1[85]
    DIRECTION INPUT ;
    USE SIGNAL ;
    PORT
      LAYER M3 ;
        RECT  41.508 0 41.526 0.038 ;
    END
  END i_x1[85]
  PIN i_x1[86]
    DIRECTION INPUT ;
    USE SIGNAL ;
    PORT
      LAYER M5 ;
        RECT  41.616 0 41.64 0.084 ;
    END
  END i_x1[86]
  PIN i_x1[87]
    DIRECTION INPUT ;
    USE SIGNAL ;
    PORT
      LAYER M3 ;
        RECT  41.724 0 41.742 0.038 ;
    END
  END i_x1[87]
  PIN i_x1[88]
    DIRECTION INPUT ;
    USE SIGNAL ;
    PORT
      LAYER M5 ;
        RECT  41.808 0 41.832 0.084 ;
    END
  END i_x1[88]
  PIN i_x1[89]
    DIRECTION INPUT ;
    USE SIGNAL ;
    PORT
      LAYER M3 ;
        RECT  41.904 0 41.922 0.038 ;
    END
  END i_x1[89]
  PIN i_x1[8]
    DIRECTION INPUT ;
    USE SIGNAL ;
    PORT
      LAYER M5 ;
        RECT  34.368 0 34.392 0.084 ;
    END
  END i_x1[8]
  PIN i_x1[90]
    DIRECTION INPUT ;
    USE SIGNAL ;
    PORT
      LAYER M5 ;
        RECT  42 0 42.024 0.084 ;
    END
  END i_x1[90]
  PIN i_x1[91]
    DIRECTION INPUT ;
    USE SIGNAL ;
    PORT
      LAYER M3 ;
        RECT  42.084 0 42.102 0.038 ;
    END
  END i_x1[91]
  PIN i_x1[92]
    DIRECTION INPUT ;
    USE SIGNAL ;
    PORT
      LAYER M5 ;
        RECT  42.192 0 42.216 0.084 ;
    END
  END i_x1[92]
  PIN i_x1[93]
    DIRECTION INPUT ;
    USE SIGNAL ;
    PORT
      LAYER M3 ;
        RECT  42.3 0 42.318 0.038 ;
    END
  END i_x1[93]
  PIN i_x1[94]
    DIRECTION INPUT ;
    USE SIGNAL ;
    PORT
      LAYER M5 ;
        RECT  42.384 0 42.408 0.084 ;
    END
  END i_x1[94]
  PIN i_x1[95]
    DIRECTION INPUT ;
    USE SIGNAL ;
    PORT
      LAYER M3 ;
        RECT  42.444 0 42.462 0.038 ;
    END
  END i_x1[95]
  PIN i_x1[96]
    DIRECTION INPUT ;
    USE SIGNAL ;
    PORT
      LAYER M5 ;
        RECT  42.528 0 42.552 0.084 ;
    END
  END i_x1[96]
  PIN i_x1[97]
    DIRECTION INPUT ;
    USE SIGNAL ;
    PORT
      LAYER M3 ;
        RECT  42.624 0 42.642 0.038 ;
    END
  END i_x1[97]
  PIN i_x1[98]
    DIRECTION INPUT ;
    USE SIGNAL ;
    PORT
      LAYER M5 ;
        RECT  42.72 0 42.744 0.084 ;
    END
  END i_x1[98]
  PIN i_x1[99]
    DIRECTION INPUT ;
    USE SIGNAL ;
    PORT
      LAYER M3 ;
        RECT  42.804 0 42.822 0.038 ;
    END
  END i_x1[99]
  PIN i_x1[9]
    DIRECTION INPUT ;
    USE SIGNAL ;
    PORT
      LAYER M3 ;
        RECT  34.452 0 34.47 0.038 ;
    END
  END i_x1[9]
  PIN o_cfg[0]
    DIRECTION OUTPUT ;
    USE SIGNAL ;
    PORT
      LAYER M5 ;
        RECT  2.208 17.196 2.232 17.28 ;
    END
  END o_cfg[0]
  PIN o_cfg[10]
    DIRECTION OUTPUT ;
    USE SIGNAL ;
    PORT
      LAYER M5 ;
        RECT  3.12 17.196 3.144 17.28 ;
    END
  END o_cfg[10]
  PIN o_cfg[11]
    DIRECTION OUTPUT ;
    USE SIGNAL ;
    PORT
      LAYER M3 ;
        RECT  3.204 17.242 3.222 17.28 ;
    END
  END o_cfg[11]
  PIN o_cfg[12]
    DIRECTION OUTPUT ;
    USE SIGNAL ;
    PORT
      LAYER M5 ;
        RECT  3.312 17.196 3.336 17.28 ;
    END
  END o_cfg[12]
  PIN o_cfg[13]
    DIRECTION OUTPUT ;
    USE SIGNAL ;
    PORT
      LAYER M3 ;
        RECT  3.42 17.242 3.438 17.28 ;
    END
  END o_cfg[13]
  PIN o_cfg[14]
    DIRECTION OUTPUT ;
    USE SIGNAL ;
    PORT
      LAYER M5 ;
        RECT  3.504 17.196 3.528 17.28 ;
    END
  END o_cfg[14]
  PIN o_cfg[15]
    DIRECTION OUTPUT ;
    USE SIGNAL ;
    PORT
      LAYER M3 ;
        RECT  3.6 17.242 3.618 17.28 ;
    END
  END o_cfg[15]
  PIN o_cfg[16]
    DIRECTION OUTPUT ;
    USE SIGNAL ;
    PORT
      LAYER M5 ;
        RECT  3.696 17.196 3.72 17.28 ;
    END
  END o_cfg[16]
  PIN o_cfg[17]
    DIRECTION OUTPUT ;
    USE SIGNAL ;
    PORT
      LAYER M3 ;
        RECT  3.78 17.242 3.798 17.28 ;
    END
  END o_cfg[17]
  PIN o_cfg[18]
    DIRECTION OUTPUT ;
    USE SIGNAL ;
    PORT
      LAYER M5 ;
        RECT  3.888 17.196 3.912 17.28 ;
    END
  END o_cfg[18]
  PIN o_cfg[19]
    DIRECTION OUTPUT ;
    USE SIGNAL ;
    PORT
      LAYER M3 ;
        RECT  3.996 17.242 4.014 17.28 ;
    END
  END o_cfg[19]
  PIN o_cfg[1]
    DIRECTION OUTPUT ;
    USE SIGNAL ;
    PORT
      LAYER M3 ;
        RECT  2.304 17.242 2.322 17.28 ;
    END
  END o_cfg[1]
  PIN o_cfg[20]
    DIRECTION OUTPUT ;
    USE SIGNAL ;
    PORT
      LAYER M5 ;
        RECT  4.032 17.196 4.056 17.28 ;
    END
  END o_cfg[20]
  PIN o_cfg[21]
    DIRECTION OUTPUT ;
    USE SIGNAL ;
    PORT
      LAYER M3 ;
        RECT  4.14 17.242 4.158 17.28 ;
    END
  END o_cfg[21]
  PIN o_cfg[22]
    DIRECTION OUTPUT ;
    USE SIGNAL ;
    PORT
      LAYER M5 ;
        RECT  4.224 17.196 4.248 17.28 ;
    END
  END o_cfg[22]
  PIN o_cfg[23]
    DIRECTION OUTPUT ;
    USE SIGNAL ;
    PORT
      LAYER M3 ;
        RECT  4.32 17.242 4.338 17.28 ;
    END
  END o_cfg[23]
  PIN o_cfg[24]
    DIRECTION OUTPUT ;
    USE SIGNAL ;
    PORT
      LAYER M5 ;
        RECT  4.416 17.196 4.44 17.28 ;
    END
  END o_cfg[24]
  PIN o_cfg[25]
    DIRECTION OUTPUT ;
    USE SIGNAL ;
    PORT
      LAYER M3 ;
        RECT  4.5 17.242 4.518 17.28 ;
    END
  END o_cfg[25]
  PIN o_cfg[26]
    DIRECTION OUTPUT ;
    USE SIGNAL ;
    PORT
      LAYER M5 ;
        RECT  4.608 17.196 4.632 17.28 ;
    END
  END o_cfg[26]
  PIN o_cfg[27]
    DIRECTION OUTPUT ;
    USE SIGNAL ;
    PORT
      LAYER M3 ;
        RECT  4.716 17.242 4.734 17.28 ;
    END
  END o_cfg[27]
  PIN o_cfg[28]
    DIRECTION OUTPUT ;
    USE SIGNAL ;
    PORT
      LAYER M5 ;
        RECT  4.8 17.196 4.824 17.28 ;
    END
  END o_cfg[28]
  PIN o_cfg[29]
    DIRECTION OUTPUT ;
    USE SIGNAL ;
    PORT
      LAYER M3 ;
        RECT  4.896 17.242 4.914 17.28 ;
    END
  END o_cfg[29]
  PIN o_cfg[2]
    DIRECTION OUTPUT ;
    USE SIGNAL ;
    PORT
      LAYER M5 ;
        RECT  2.4 17.196 2.424 17.28 ;
    END
  END o_cfg[2]
  PIN o_cfg[30]
    DIRECTION OUTPUT ;
    USE SIGNAL ;
    PORT
      LAYER M5 ;
        RECT  4.992 17.196 5.016 17.28 ;
    END
  END o_cfg[30]
  PIN o_cfg[31]
    DIRECTION OUTPUT ;
    USE SIGNAL ;
    PORT
      LAYER M3 ;
        RECT  5.076 17.242 5.094 17.28 ;
    END
  END o_cfg[31]
  PIN o_cfg[32]
    DIRECTION OUTPUT ;
    USE SIGNAL ;
    PORT
      LAYER M5 ;
        RECT  5.184 17.196 5.208 17.28 ;
    END
  END o_cfg[32]
  PIN o_cfg[33]
    DIRECTION OUTPUT ;
    USE SIGNAL ;
    PORT
      LAYER M3 ;
        RECT  5.292 17.242 5.31 17.28 ;
    END
  END o_cfg[33]
  PIN o_cfg[34]
    DIRECTION OUTPUT ;
    USE SIGNAL ;
    PORT
      LAYER M5 ;
        RECT  5.376 17.196 5.4 17.28 ;
    END
  END o_cfg[34]
  PIN o_cfg[35]
    DIRECTION OUTPUT ;
    USE SIGNAL ;
    PORT
      LAYER M3 ;
        RECT  5.472 17.242 5.49 17.28 ;
    END
  END o_cfg[35]
  PIN o_cfg[36]
    DIRECTION OUTPUT ;
    USE SIGNAL ;
    PORT
      LAYER M5 ;
        RECT  5.52 17.196 5.544 17.28 ;
    END
  END o_cfg[36]
  PIN o_cfg[37]
    DIRECTION OUTPUT ;
    USE SIGNAL ;
    PORT
      LAYER M3 ;
        RECT  5.616 17.242 5.634 17.28 ;
    END
  END o_cfg[37]
  PIN o_cfg[38]
    DIRECTION OUTPUT ;
    USE SIGNAL ;
    PORT
      LAYER M5 ;
        RECT  5.712 17.196 5.736 17.28 ;
    END
  END o_cfg[38]
  PIN o_cfg[39]
    DIRECTION OUTPUT ;
    USE SIGNAL ;
    PORT
      LAYER M3 ;
        RECT  5.796 17.242 5.814 17.28 ;
    END
  END o_cfg[39]
  PIN o_cfg[3]
    DIRECTION OUTPUT ;
    USE SIGNAL ;
    PORT
      LAYER M3 ;
        RECT  2.484 17.242 2.502 17.28 ;
    END
  END o_cfg[3]
  PIN o_cfg[40]
    DIRECTION OUTPUT ;
    USE SIGNAL ;
    PORT
      LAYER M5 ;
        RECT  5.904 17.196 5.928 17.28 ;
    END
  END o_cfg[40]
  PIN o_cfg[41]
    DIRECTION OUTPUT ;
    USE SIGNAL ;
    PORT
      LAYER M3 ;
        RECT  6.012 17.242 6.03 17.28 ;
    END
  END o_cfg[41]
  PIN o_cfg[42]
    DIRECTION OUTPUT ;
    USE SIGNAL ;
    PORT
      LAYER M5 ;
        RECT  6.096 17.196 6.12 17.28 ;
    END
  END o_cfg[42]
  PIN o_cfg[43]
    DIRECTION OUTPUT ;
    USE SIGNAL ;
    PORT
      LAYER M3 ;
        RECT  6.192 17.242 6.21 17.28 ;
    END
  END o_cfg[43]
  PIN o_cfg[44]
    DIRECTION OUTPUT ;
    USE SIGNAL ;
    PORT
      LAYER M5 ;
        RECT  6.288 17.196 6.312 17.28 ;
    END
  END o_cfg[44]
  PIN o_cfg[45]
    DIRECTION OUTPUT ;
    USE SIGNAL ;
    PORT
      LAYER M3 ;
        RECT  6.372 17.242 6.39 17.28 ;
    END
  END o_cfg[45]
  PIN o_cfg[46]
    DIRECTION OUTPUT ;
    USE SIGNAL ;
    PORT
      LAYER M5 ;
        RECT  6.48 17.196 6.504 17.28 ;
    END
  END o_cfg[46]
  PIN o_cfg[47]
    DIRECTION OUTPUT ;
    USE SIGNAL ;
    PORT
      LAYER M3 ;
        RECT  6.588 17.242 6.606 17.28 ;
    END
  END o_cfg[47]
  PIN o_cfg[48]
    DIRECTION OUTPUT ;
    USE SIGNAL ;
    PORT
      LAYER M5 ;
        RECT  6.672 17.196 6.696 17.28 ;
    END
  END o_cfg[48]
  PIN o_cfg[49]
    DIRECTION OUTPUT ;
    USE SIGNAL ;
    PORT
      LAYER M3 ;
        RECT  6.768 17.242 6.786 17.28 ;
    END
  END o_cfg[49]
  PIN o_cfg[4]
    DIRECTION OUTPUT ;
    USE SIGNAL ;
    PORT
      LAYER M5 ;
        RECT  2.544 17.196 2.568 17.28 ;
    END
  END o_cfg[4]
  PIN o_cfg[50]
    DIRECTION OUTPUT ;
    USE SIGNAL ;
    PORT
      LAYER M5 ;
        RECT  6.864 17.196 6.888 17.28 ;
    END
  END o_cfg[50]
  PIN o_cfg[51]
    DIRECTION OUTPUT ;
    USE SIGNAL ;
    PORT
      LAYER M3 ;
        RECT  6.948 17.242 6.966 17.28 ;
    END
  END o_cfg[51]
  PIN o_cfg[52]
    DIRECTION OUTPUT ;
    USE SIGNAL ;
    PORT
      LAYER M5 ;
        RECT  7.008 17.196 7.032 17.28 ;
    END
  END o_cfg[52]
  PIN o_cfg[53]
    DIRECTION OUTPUT ;
    USE SIGNAL ;
    PORT
      LAYER M3 ;
        RECT  7.092 17.242 7.11 17.28 ;
    END
  END o_cfg[53]
  PIN o_cfg[5]
    DIRECTION OUTPUT ;
    USE SIGNAL ;
    PORT
      LAYER M3 ;
        RECT  2.628 17.242 2.646 17.28 ;
    END
  END o_cfg[5]
  PIN o_cfg[6]
    DIRECTION OUTPUT ;
    USE SIGNAL ;
    PORT
      LAYER M5 ;
        RECT  2.736 17.196 2.76 17.28 ;
    END
  END o_cfg[6]
  PIN o_cfg[7]
    DIRECTION OUTPUT ;
    USE SIGNAL ;
    PORT
      LAYER M3 ;
        RECT  2.844 17.242 2.862 17.28 ;
    END
  END o_cfg[7]
  PIN o_cfg[8]
    DIRECTION OUTPUT ;
    USE SIGNAL ;
    PORT
      LAYER M5 ;
        RECT  2.928 17.196 2.952 17.28 ;
    END
  END o_cfg[8]
  PIN o_cfg[9]
    DIRECTION OUTPUT ;
    USE SIGNAL ;
    PORT
      LAYER M3 ;
        RECT  3.024 17.242 3.042 17.28 ;
    END
  END o_cfg[9]
  PIN o_go[0]
    DIRECTION OUTPUT ;
    USE SIGNAL ;
    PORT
      LAYER M5 ;
        RECT  7.2 17.196 7.224 17.28 ;
    END
  END o_go[0]
  PIN o_x0[0]
    DIRECTION OUTPUT ;
    USE SIGNAL ;
    PORT
      LAYER M3 ;
        RECT  10.476 17.242 10.494 17.28 ;
    END
  END o_x0[0]
  PIN o_x0[100]
    DIRECTION OUTPUT ;
    USE SIGNAL ;
    PORT
      LAYER M3 ;
        RECT  19.764 17.242 19.782 17.28 ;
    END
  END o_x0[100]
  PIN o_x0[101]
    DIRECTION OUTPUT ;
    USE SIGNAL ;
    PORT
      LAYER M5 ;
        RECT  19.872 17.196 19.896 17.28 ;
    END
  END o_x0[101]
  PIN o_x0[102]
    DIRECTION OUTPUT ;
    USE SIGNAL ;
    PORT
      LAYER M3 ;
        RECT  19.98 17.242 19.998 17.28 ;
    END
  END o_x0[102]
  PIN o_x0[103]
    DIRECTION OUTPUT ;
    USE SIGNAL ;
    PORT
      LAYER M5 ;
        RECT  20.064 17.196 20.088 17.28 ;
    END
  END o_x0[103]
  PIN o_x0[104]
    DIRECTION OUTPUT ;
    USE SIGNAL ;
    PORT
      LAYER M3 ;
        RECT  20.16 17.242 20.178 17.28 ;
    END
  END o_x0[104]
  PIN o_x0[105]
    DIRECTION OUTPUT ;
    USE SIGNAL ;
    PORT
      LAYER M5 ;
        RECT  20.256 17.196 20.28 17.28 ;
    END
  END o_x0[105]
  PIN o_x0[106]
    DIRECTION OUTPUT ;
    USE SIGNAL ;
    PORT
      LAYER M3 ;
        RECT  20.304 17.242 20.322 17.28 ;
    END
  END o_x0[106]
  PIN o_x0[107]
    DIRECTION OUTPUT ;
    USE SIGNAL ;
    PORT
      LAYER M5 ;
        RECT  20.4 17.196 20.424 17.28 ;
    END
  END o_x0[107]
  PIN o_x0[108]
    DIRECTION OUTPUT ;
    USE SIGNAL ;
    PORT
      LAYER M3 ;
        RECT  20.484 17.242 20.502 17.28 ;
    END
  END o_x0[108]
  PIN o_x0[109]
    DIRECTION OUTPUT ;
    USE SIGNAL ;
    PORT
      LAYER M5 ;
        RECT  20.592 17.196 20.616 17.28 ;
    END
  END o_x0[109]
  PIN o_x0[10]
    DIRECTION OUTPUT ;
    USE SIGNAL ;
    PORT
      LAYER M3 ;
        RECT  11.376 17.242 11.394 17.28 ;
    END
  END o_x0[10]
  PIN o_x0[110]
    DIRECTION OUTPUT ;
    USE SIGNAL ;
    PORT
      LAYER M3 ;
        RECT  20.7 17.242 20.718 17.28 ;
    END
  END o_x0[110]
  PIN o_x0[111]
    DIRECTION OUTPUT ;
    USE SIGNAL ;
    PORT
      LAYER M5 ;
        RECT  20.784 17.196 20.808 17.28 ;
    END
  END o_x0[111]
  PIN o_x0[112]
    DIRECTION OUTPUT ;
    USE SIGNAL ;
    PORT
      LAYER M3 ;
        RECT  20.88 17.242 20.898 17.28 ;
    END
  END o_x0[112]
  PIN o_x0[113]
    DIRECTION OUTPUT ;
    USE SIGNAL ;
    PORT
      LAYER M5 ;
        RECT  20.976 17.196 21 17.28 ;
    END
  END o_x0[113]
  PIN o_x0[114]
    DIRECTION OUTPUT ;
    USE SIGNAL ;
    PORT
      LAYER M3 ;
        RECT  21.06 17.242 21.078 17.28 ;
    END
  END o_x0[114]
  PIN o_x0[115]
    DIRECTION OUTPUT ;
    USE SIGNAL ;
    PORT
      LAYER M5 ;
        RECT  21.168 17.196 21.192 17.28 ;
    END
  END o_x0[115]
  PIN o_x0[116]
    DIRECTION OUTPUT ;
    USE SIGNAL ;
    PORT
      LAYER M3 ;
        RECT  21.276 17.242 21.294 17.28 ;
    END
  END o_x0[116]
  PIN o_x0[117]
    DIRECTION OUTPUT ;
    USE SIGNAL ;
    PORT
      LAYER M5 ;
        RECT  21.36 17.196 21.384 17.28 ;
    END
  END o_x0[117]
  PIN o_x0[118]
    DIRECTION OUTPUT ;
    USE SIGNAL ;
    PORT
      LAYER M3 ;
        RECT  21.456 17.242 21.474 17.28 ;
    END
  END o_x0[118]
  PIN o_x0[119]
    DIRECTION OUTPUT ;
    USE SIGNAL ;
    PORT
      LAYER M5 ;
        RECT  21.552 17.196 21.576 17.28 ;
    END
  END o_x0[119]
  PIN o_x0[11]
    DIRECTION OUTPUT ;
    USE SIGNAL ;
    PORT
      LAYER M5 ;
        RECT  11.472 17.196 11.496 17.28 ;
    END
  END o_x0[11]
  PIN o_x0[120]
    DIRECTION OUTPUT ;
    USE SIGNAL ;
    PORT
      LAYER M3 ;
        RECT  21.636 17.242 21.654 17.28 ;
    END
  END o_x0[120]
  PIN o_x0[121]
    DIRECTION OUTPUT ;
    USE SIGNAL ;
    PORT
      LAYER M5 ;
        RECT  21.744 17.196 21.768 17.28 ;
    END
  END o_x0[121]
  PIN o_x0[122]
    DIRECTION OUTPUT ;
    USE SIGNAL ;
    PORT
      LAYER M3 ;
        RECT  21.78 17.242 21.798 17.28 ;
    END
  END o_x0[122]
  PIN o_x0[123]
    DIRECTION OUTPUT ;
    USE SIGNAL ;
    PORT
      LAYER M5 ;
        RECT  21.888 17.196 21.912 17.28 ;
    END
  END o_x0[123]
  PIN o_x0[124]
    DIRECTION OUTPUT ;
    USE SIGNAL ;
    PORT
      LAYER M3 ;
        RECT  21.996 17.242 22.014 17.28 ;
    END
  END o_x0[124]
  PIN o_x0[125]
    DIRECTION OUTPUT ;
    USE SIGNAL ;
    PORT
      LAYER M5 ;
        RECT  22.08 17.196 22.104 17.28 ;
    END
  END o_x0[125]
  PIN o_x0[126]
    DIRECTION OUTPUT ;
    USE SIGNAL ;
    PORT
      LAYER M3 ;
        RECT  22.176 17.242 22.194 17.28 ;
    END
  END o_x0[126]
  PIN o_x0[127]
    DIRECTION OUTPUT ;
    USE SIGNAL ;
    PORT
      LAYER M5 ;
        RECT  22.272 17.196 22.296 17.28 ;
    END
  END o_x0[127]
  PIN o_x0[128]
    DIRECTION OUTPUT ;
    USE SIGNAL ;
    PORT
      LAYER M3 ;
        RECT  22.356 17.242 22.374 17.28 ;
    END
  END o_x0[128]
  PIN o_x0[129]
    DIRECTION OUTPUT ;
    USE SIGNAL ;
    PORT
      LAYER M5 ;
        RECT  22.464 17.196 22.488 17.28 ;
    END
  END o_x0[129]
  PIN o_x0[12]
    DIRECTION OUTPUT ;
    USE SIGNAL ;
    PORT
      LAYER M3 ;
        RECT  11.556 17.242 11.574 17.28 ;
    END
  END o_x0[12]
  PIN o_x0[130]
    DIRECTION OUTPUT ;
    USE SIGNAL ;
    PORT
      LAYER M3 ;
        RECT  22.572 17.242 22.59 17.28 ;
    END
  END o_x0[130]
  PIN o_x0[131]
    DIRECTION OUTPUT ;
    USE SIGNAL ;
    PORT
      LAYER M5 ;
        RECT  22.656 17.196 22.68 17.28 ;
    END
  END o_x0[131]
  PIN o_x0[132]
    DIRECTION OUTPUT ;
    USE SIGNAL ;
    PORT
      LAYER M3 ;
        RECT  22.752 17.242 22.77 17.28 ;
    END
  END o_x0[132]
  PIN o_x0[133]
    DIRECTION OUTPUT ;
    USE SIGNAL ;
    PORT
      LAYER M5 ;
        RECT  22.848 17.196 22.872 17.28 ;
    END
  END o_x0[133]
  PIN o_x0[134]
    DIRECTION OUTPUT ;
    USE SIGNAL ;
    PORT
      LAYER M3 ;
        RECT  22.932 17.242 22.95 17.28 ;
    END
  END o_x0[134]
  PIN o_x0[135]
    DIRECTION OUTPUT ;
    USE SIGNAL ;
    PORT
      LAYER M5 ;
        RECT  23.04 17.196 23.064 17.28 ;
    END
  END o_x0[135]
  PIN o_x0[136]
    DIRECTION OUTPUT ;
    USE SIGNAL ;
    PORT
      LAYER M3 ;
        RECT  23.148 17.242 23.166 17.28 ;
    END
  END o_x0[136]
  PIN o_x0[137]
    DIRECTION OUTPUT ;
    USE SIGNAL ;
    PORT
      LAYER M5 ;
        RECT  23.184 17.196 23.208 17.28 ;
    END
  END o_x0[137]
  PIN o_x0[138]
    DIRECTION OUTPUT ;
    USE SIGNAL ;
    PORT
      LAYER M3 ;
        RECT  23.292 17.242 23.31 17.28 ;
    END
  END o_x0[138]
  PIN o_x0[139]
    DIRECTION OUTPUT ;
    USE SIGNAL ;
    PORT
      LAYER M5 ;
        RECT  23.376 17.196 23.4 17.28 ;
    END
  END o_x0[139]
  PIN o_x0[13]
    DIRECTION OUTPUT ;
    USE SIGNAL ;
    PORT
      LAYER M5 ;
        RECT  11.664 17.196 11.688 17.28 ;
    END
  END o_x0[13]
  PIN o_x0[140]
    DIRECTION OUTPUT ;
    USE SIGNAL ;
    PORT
      LAYER M3 ;
        RECT  23.472 17.242 23.49 17.28 ;
    END
  END o_x0[140]
  PIN o_x0[141]
    DIRECTION OUTPUT ;
    USE SIGNAL ;
    PORT
      LAYER M5 ;
        RECT  23.568 17.196 23.592 17.28 ;
    END
  END o_x0[141]
  PIN o_x0[142]
    DIRECTION OUTPUT ;
    USE SIGNAL ;
    PORT
      LAYER M3 ;
        RECT  23.652 17.242 23.67 17.28 ;
    END
  END o_x0[142]
  PIN o_x0[143]
    DIRECTION OUTPUT ;
    USE SIGNAL ;
    PORT
      LAYER M5 ;
        RECT  23.76 17.196 23.784 17.28 ;
    END
  END o_x0[143]
  PIN o_x0[144]
    DIRECTION OUTPUT ;
    USE SIGNAL ;
    PORT
      LAYER M3 ;
        RECT  23.868 17.242 23.886 17.28 ;
    END
  END o_x0[144]
  PIN o_x0[145]
    DIRECTION OUTPUT ;
    USE SIGNAL ;
    PORT
      LAYER M5 ;
        RECT  23.952 17.196 23.976 17.28 ;
    END
  END o_x0[145]
  PIN o_x0[146]
    DIRECTION OUTPUT ;
    USE SIGNAL ;
    PORT
      LAYER M3 ;
        RECT  24.048 17.242 24.066 17.28 ;
    END
  END o_x0[146]
  PIN o_x0[147]
    DIRECTION OUTPUT ;
    USE SIGNAL ;
    PORT
      LAYER M5 ;
        RECT  24.144 17.196 24.168 17.28 ;
    END
  END o_x0[147]
  PIN o_x0[148]
    DIRECTION OUTPUT ;
    USE SIGNAL ;
    PORT
      LAYER M3 ;
        RECT  24.228 17.242 24.246 17.28 ;
    END
  END o_x0[148]
  PIN o_x0[149]
    DIRECTION OUTPUT ;
    USE SIGNAL ;
    PORT
      LAYER M5 ;
        RECT  24.336 17.196 24.36 17.28 ;
    END
  END o_x0[149]
  PIN o_x0[14]
    DIRECTION OUTPUT ;
    USE SIGNAL ;
    PORT
      LAYER M3 ;
        RECT  11.772 17.242 11.79 17.28 ;
    END
  END o_x0[14]
  PIN o_x0[150]
    DIRECTION OUTPUT ;
    USE SIGNAL ;
    PORT
      LAYER M3 ;
        RECT  24.444 17.242 24.462 17.28 ;
    END
  END o_x0[150]
  PIN o_x0[151]
    DIRECTION OUTPUT ;
    USE SIGNAL ;
    PORT
      LAYER M5 ;
        RECT  24.528 17.196 24.552 17.28 ;
    END
  END o_x0[151]
  PIN o_x0[152]
    DIRECTION OUTPUT ;
    USE SIGNAL ;
    PORT
      LAYER M3 ;
        RECT  24.624 17.242 24.642 17.28 ;
    END
  END o_x0[152]
  PIN o_x0[153]
    DIRECTION OUTPUT ;
    USE SIGNAL ;
    PORT
      LAYER M5 ;
        RECT  24.672 17.196 24.696 17.28 ;
    END
  END o_x0[153]
  PIN o_x0[154]
    DIRECTION OUTPUT ;
    USE SIGNAL ;
    PORT
      LAYER M3 ;
        RECT  24.768 17.242 24.786 17.28 ;
    END
  END o_x0[154]
  PIN o_x0[155]
    DIRECTION OUTPUT ;
    USE SIGNAL ;
    PORT
      LAYER M5 ;
        RECT  24.864 17.196 24.888 17.28 ;
    END
  END o_x0[155]
  PIN o_x0[156]
    DIRECTION OUTPUT ;
    USE SIGNAL ;
    PORT
      LAYER M3 ;
        RECT  24.948 17.242 24.966 17.28 ;
    END
  END o_x0[156]
  PIN o_x0[157]
    DIRECTION OUTPUT ;
    USE SIGNAL ;
    PORT
      LAYER M5 ;
        RECT  25.056 17.196 25.08 17.28 ;
    END
  END o_x0[157]
  PIN o_x0[158]
    DIRECTION OUTPUT ;
    USE SIGNAL ;
    PORT
      LAYER M3 ;
        RECT  25.164 17.242 25.182 17.28 ;
    END
  END o_x0[158]
  PIN o_x0[159]
    DIRECTION OUTPUT ;
    USE SIGNAL ;
    PORT
      LAYER M5 ;
        RECT  25.248 17.196 25.272 17.28 ;
    END
  END o_x0[159]
  PIN o_x0[15]
    DIRECTION OUTPUT ;
    USE SIGNAL ;
    PORT
      LAYER M5 ;
        RECT  11.856 17.196 11.88 17.28 ;
    END
  END o_x0[15]
  PIN o_x0[160]
    DIRECTION OUTPUT ;
    USE SIGNAL ;
    PORT
      LAYER M3 ;
        RECT  25.344 17.242 25.362 17.28 ;
    END
  END o_x0[160]
  PIN o_x0[161]
    DIRECTION OUTPUT ;
    USE SIGNAL ;
    PORT
      LAYER M5 ;
        RECT  25.44 17.196 25.464 17.28 ;
    END
  END o_x0[161]
  PIN o_x0[162]
    DIRECTION OUTPUT ;
    USE SIGNAL ;
    PORT
      LAYER M3 ;
        RECT  25.524 17.242 25.542 17.28 ;
    END
  END o_x0[162]
  PIN o_x0[163]
    DIRECTION OUTPUT ;
    USE SIGNAL ;
    PORT
      LAYER M5 ;
        RECT  25.632 17.196 25.656 17.28 ;
    END
  END o_x0[163]
  PIN o_x0[164]
    DIRECTION OUTPUT ;
    USE SIGNAL ;
    PORT
      LAYER M3 ;
        RECT  25.74 17.242 25.758 17.28 ;
    END
  END o_x0[164]
  PIN o_x0[165]
    DIRECTION OUTPUT ;
    USE SIGNAL ;
    PORT
      LAYER M5 ;
        RECT  25.824 17.196 25.848 17.28 ;
    END
  END o_x0[165]
  PIN o_x0[166]
    DIRECTION OUTPUT ;
    USE SIGNAL ;
    PORT
      LAYER M3 ;
        RECT  25.92 17.242 25.938 17.28 ;
    END
  END o_x0[166]
  PIN o_x0[167]
    DIRECTION OUTPUT ;
    USE SIGNAL ;
    PORT
      LAYER M5 ;
        RECT  26.016 17.196 26.04 17.28 ;
    END
  END o_x0[167]
  PIN o_x0[168]
    DIRECTION OUTPUT ;
    USE SIGNAL ;
    PORT
      LAYER M3 ;
        RECT  26.1 17.242 26.118 17.28 ;
    END
  END o_x0[168]
  PIN o_x0[169]
    DIRECTION OUTPUT ;
    USE SIGNAL ;
    PORT
      LAYER M5 ;
        RECT  26.16 17.196 26.184 17.28 ;
    END
  END o_x0[169]
  PIN o_x0[16]
    DIRECTION OUTPUT ;
    USE SIGNAL ;
    PORT
      LAYER M3 ;
        RECT  11.952 17.242 11.97 17.28 ;
    END
  END o_x0[16]
  PIN o_x0[170]
    DIRECTION OUTPUT ;
    USE SIGNAL ;
    PORT
      LAYER M3 ;
        RECT  26.244 17.242 26.262 17.28 ;
    END
  END o_x0[170]
  PIN o_x0[171]
    DIRECTION OUTPUT ;
    USE SIGNAL ;
    PORT
      LAYER M5 ;
        RECT  26.352 17.196 26.376 17.28 ;
    END
  END o_x0[171]
  PIN o_x0[172]
    DIRECTION OUTPUT ;
    USE SIGNAL ;
    PORT
      LAYER M3 ;
        RECT  26.46 17.242 26.478 17.28 ;
    END
  END o_x0[172]
  PIN o_x0[173]
    DIRECTION OUTPUT ;
    USE SIGNAL ;
    PORT
      LAYER M5 ;
        RECT  26.544 17.196 26.568 17.28 ;
    END
  END o_x0[173]
  PIN o_x0[174]
    DIRECTION OUTPUT ;
    USE SIGNAL ;
    PORT
      LAYER M3 ;
        RECT  26.64 17.242 26.658 17.28 ;
    END
  END o_x0[174]
  PIN o_x0[175]
    DIRECTION OUTPUT ;
    USE SIGNAL ;
    PORT
      LAYER M5 ;
        RECT  26.736 17.196 26.76 17.28 ;
    END
  END o_x0[175]
  PIN o_x0[176]
    DIRECTION OUTPUT ;
    USE SIGNAL ;
    PORT
      LAYER M3 ;
        RECT  26.82 17.242 26.838 17.28 ;
    END
  END o_x0[176]
  PIN o_x0[177]
    DIRECTION OUTPUT ;
    USE SIGNAL ;
    PORT
      LAYER M5 ;
        RECT  26.928 17.196 26.952 17.28 ;
    END
  END o_x0[177]
  PIN o_x0[178]
    DIRECTION OUTPUT ;
    USE SIGNAL ;
    PORT
      LAYER M3 ;
        RECT  27.036 17.242 27.054 17.28 ;
    END
  END o_x0[178]
  PIN o_x0[179]
    DIRECTION OUTPUT ;
    USE SIGNAL ;
    PORT
      LAYER M5 ;
        RECT  27.12 17.196 27.144 17.28 ;
    END
  END o_x0[179]
  PIN o_x0[17]
    DIRECTION OUTPUT ;
    USE SIGNAL ;
    PORT
      LAYER M5 ;
        RECT  12.048 17.196 12.072 17.28 ;
    END
  END o_x0[17]
  PIN o_x0[180]
    DIRECTION OUTPUT ;
    USE SIGNAL ;
    PORT
      LAYER M3 ;
        RECT  27.216 17.242 27.234 17.28 ;
    END
  END o_x0[180]
  PIN o_x0[181]
    DIRECTION OUTPUT ;
    USE SIGNAL ;
    PORT
      LAYER M5 ;
        RECT  27.312 17.196 27.336 17.28 ;
    END
  END o_x0[181]
  PIN o_x0[182]
    DIRECTION OUTPUT ;
    USE SIGNAL ;
    PORT
      LAYER M3 ;
        RECT  27.396 17.242 27.414 17.28 ;
    END
  END o_x0[182]
  PIN o_x0[183]
    DIRECTION OUTPUT ;
    USE SIGNAL ;
    PORT
      LAYER M5 ;
        RECT  27.504 17.196 27.528 17.28 ;
    END
  END o_x0[183]
  PIN o_x0[184]
    DIRECTION OUTPUT ;
    USE SIGNAL ;
    PORT
      LAYER M3 ;
        RECT  27.612 17.242 27.63 17.28 ;
    END
  END o_x0[184]
  PIN o_x0[185]
    DIRECTION OUTPUT ;
    USE SIGNAL ;
    PORT
      LAYER M5 ;
        RECT  27.648 17.196 27.672 17.28 ;
    END
  END o_x0[185]
  PIN o_x0[186]
    DIRECTION OUTPUT ;
    USE SIGNAL ;
    PORT
      LAYER M3 ;
        RECT  27.756 17.242 27.774 17.28 ;
    END
  END o_x0[186]
  PIN o_x0[187]
    DIRECTION OUTPUT ;
    USE SIGNAL ;
    PORT
      LAYER M5 ;
        RECT  27.84 17.196 27.864 17.28 ;
    END
  END o_x0[187]
  PIN o_x0[188]
    DIRECTION OUTPUT ;
    USE SIGNAL ;
    PORT
      LAYER M3 ;
        RECT  27.936 17.242 27.954 17.28 ;
    END
  END o_x0[188]
  PIN o_x0[189]
    DIRECTION OUTPUT ;
    USE SIGNAL ;
    PORT
      LAYER M5 ;
        RECT  28.032 17.196 28.056 17.28 ;
    END
  END o_x0[189]
  PIN o_x0[18]
    DIRECTION OUTPUT ;
    USE SIGNAL ;
    PORT
      LAYER M3 ;
        RECT  12.132 17.242 12.15 17.28 ;
    END
  END o_x0[18]
  PIN o_x0[190]
    DIRECTION OUTPUT ;
    USE SIGNAL ;
    PORT
      LAYER M3 ;
        RECT  28.116 17.242 28.134 17.28 ;
    END
  END o_x0[190]
  PIN o_x0[191]
    DIRECTION OUTPUT ;
    USE SIGNAL ;
    PORT
      LAYER M5 ;
        RECT  28.224 17.196 28.248 17.28 ;
    END
  END o_x0[191]
  PIN o_x0[192]
    DIRECTION OUTPUT ;
    USE SIGNAL ;
    PORT
      LAYER M3 ;
        RECT  28.332 17.242 28.35 17.28 ;
    END
  END o_x0[192]
  PIN o_x0[193]
    DIRECTION OUTPUT ;
    USE SIGNAL ;
    PORT
      LAYER M5 ;
        RECT  28.416 17.196 28.44 17.28 ;
    END
  END o_x0[193]
  PIN o_x0[194]
    DIRECTION OUTPUT ;
    USE SIGNAL ;
    PORT
      LAYER M3 ;
        RECT  28.512 17.242 28.53 17.28 ;
    END
  END o_x0[194]
  PIN o_x0[195]
    DIRECTION OUTPUT ;
    USE SIGNAL ;
    PORT
      LAYER M5 ;
        RECT  28.608 17.196 28.632 17.28 ;
    END
  END o_x0[195]
  PIN o_x0[196]
    DIRECTION OUTPUT ;
    USE SIGNAL ;
    PORT
      LAYER M3 ;
        RECT  28.692 17.242 28.71 17.28 ;
    END
  END o_x0[196]
  PIN o_x0[197]
    DIRECTION OUTPUT ;
    USE SIGNAL ;
    PORT
      LAYER M5 ;
        RECT  28.8 17.196 28.824 17.28 ;
    END
  END o_x0[197]
  PIN o_x0[198]
    DIRECTION OUTPUT ;
    USE SIGNAL ;
    PORT
      LAYER M3 ;
        RECT  28.908 17.242 28.926 17.28 ;
    END
  END o_x0[198]
  PIN o_x0[199]
    DIRECTION OUTPUT ;
    USE SIGNAL ;
    PORT
      LAYER M5 ;
        RECT  28.992 17.196 29.016 17.28 ;
    END
  END o_x0[199]
  PIN o_x0[19]
    DIRECTION OUTPUT ;
    USE SIGNAL ;
    PORT
      LAYER M5 ;
        RECT  12.24 17.196 12.264 17.28 ;
    END
  END o_x0[19]
  PIN o_x0[1]
    DIRECTION OUTPUT ;
    USE SIGNAL ;
    PORT
      LAYER M5 ;
        RECT  10.56 17.196 10.584 17.28 ;
    END
  END o_x0[1]
  PIN o_x0[200]
    DIRECTION OUTPUT ;
    USE SIGNAL ;
    PORT
      LAYER M3 ;
        RECT  29.088 17.242 29.106 17.28 ;
    END
  END o_x0[200]
  PIN o_x0[201]
    DIRECTION OUTPUT ;
    USE SIGNAL ;
    PORT
      LAYER M5 ;
        RECT  29.136 17.196 29.16 17.28 ;
    END
  END o_x0[201]
  PIN o_x0[202]
    DIRECTION OUTPUT ;
    USE SIGNAL ;
    PORT
      LAYER M3 ;
        RECT  29.232 17.242 29.25 17.28 ;
    END
  END o_x0[202]
  PIN o_x0[203]
    DIRECTION OUTPUT ;
    USE SIGNAL ;
    PORT
      LAYER M5 ;
        RECT  29.328 17.196 29.352 17.28 ;
    END
  END o_x0[203]
  PIN o_x0[204]
    DIRECTION OUTPUT ;
    USE SIGNAL ;
    PORT
      LAYER M3 ;
        RECT  29.412 17.242 29.43 17.28 ;
    END
  END o_x0[204]
  PIN o_x0[205]
    DIRECTION OUTPUT ;
    USE SIGNAL ;
    PORT
      LAYER M5 ;
        RECT  29.52 17.196 29.544 17.28 ;
    END
  END o_x0[205]
  PIN o_x0[206]
    DIRECTION OUTPUT ;
    USE SIGNAL ;
    PORT
      LAYER M3 ;
        RECT  29.628 17.242 29.646 17.28 ;
    END
  END o_x0[206]
  PIN o_x0[207]
    DIRECTION OUTPUT ;
    USE SIGNAL ;
    PORT
      LAYER M5 ;
        RECT  29.712 17.196 29.736 17.28 ;
    END
  END o_x0[207]
  PIN o_x0[208]
    DIRECTION OUTPUT ;
    USE SIGNAL ;
    PORT
      LAYER M3 ;
        RECT  29.808 17.242 29.826 17.28 ;
    END
  END o_x0[208]
  PIN o_x0[209]
    DIRECTION OUTPUT ;
    USE SIGNAL ;
    PORT
      LAYER M5 ;
        RECT  29.904 17.196 29.928 17.28 ;
    END
  END o_x0[209]
  PIN o_x0[20]
    DIRECTION OUTPUT ;
    USE SIGNAL ;
    PORT
      LAYER M3 ;
        RECT  12.348 17.242 12.366 17.28 ;
    END
  END o_x0[20]
  PIN o_x0[210]
    DIRECTION OUTPUT ;
    USE SIGNAL ;
    PORT
      LAYER M3 ;
        RECT  29.988 17.242 30.006 17.28 ;
    END
  END o_x0[210]
  PIN o_x0[211]
    DIRECTION OUTPUT ;
    USE SIGNAL ;
    PORT
      LAYER M5 ;
        RECT  30.096 17.196 30.12 17.28 ;
    END
  END o_x0[211]
  PIN o_x0[212]
    DIRECTION OUTPUT ;
    USE SIGNAL ;
    PORT
      LAYER M3 ;
        RECT  30.204 17.242 30.222 17.28 ;
    END
  END o_x0[212]
  PIN o_x0[213]
    DIRECTION OUTPUT ;
    USE SIGNAL ;
    PORT
      LAYER M5 ;
        RECT  30.288 17.196 30.312 17.28 ;
    END
  END o_x0[213]
  PIN o_x0[214]
    DIRECTION OUTPUT ;
    USE SIGNAL ;
    PORT
      LAYER M3 ;
        RECT  30.384 17.242 30.402 17.28 ;
    END
  END o_x0[214]
  PIN o_x0[215]
    DIRECTION OUTPUT ;
    USE SIGNAL ;
    PORT
      LAYER M5 ;
        RECT  30.48 17.196 30.504 17.28 ;
    END
  END o_x0[215]
  PIN o_x0[216]
    DIRECTION OUTPUT ;
    USE SIGNAL ;
    PORT
      LAYER M3 ;
        RECT  30.564 17.242 30.582 17.28 ;
    END
  END o_x0[216]
  PIN o_x0[217]
    DIRECTION OUTPUT ;
    USE SIGNAL ;
    PORT
      LAYER M5 ;
        RECT  30.624 17.196 30.648 17.28 ;
    END
  END o_x0[217]
  PIN o_x0[218]
    DIRECTION OUTPUT ;
    USE SIGNAL ;
    PORT
      LAYER M3 ;
        RECT  30.708 17.242 30.726 17.28 ;
    END
  END o_x0[218]
  PIN o_x0[219]
    DIRECTION OUTPUT ;
    USE SIGNAL ;
    PORT
      LAYER M5 ;
        RECT  30.816 17.196 30.84 17.28 ;
    END
  END o_x0[219]
  PIN o_x0[21]
    DIRECTION OUTPUT ;
    USE SIGNAL ;
    PORT
      LAYER M5 ;
        RECT  12.432 17.196 12.456 17.28 ;
    END
  END o_x0[21]
  PIN o_x0[220]
    DIRECTION OUTPUT ;
    USE SIGNAL ;
    PORT
      LAYER M3 ;
        RECT  30.924 17.242 30.942 17.28 ;
    END
  END o_x0[220]
  PIN o_x0[221]
    DIRECTION OUTPUT ;
    USE SIGNAL ;
    PORT
      LAYER M5 ;
        RECT  31.008 17.196 31.032 17.28 ;
    END
  END o_x0[221]
  PIN o_x0[222]
    DIRECTION OUTPUT ;
    USE SIGNAL ;
    PORT
      LAYER M3 ;
        RECT  31.104 17.242 31.122 17.28 ;
    END
  END o_x0[222]
  PIN o_x0[223]
    DIRECTION OUTPUT ;
    USE SIGNAL ;
    PORT
      LAYER M5 ;
        RECT  31.2 17.196 31.224 17.28 ;
    END
  END o_x0[223]
  PIN o_x0[224]
    DIRECTION OUTPUT ;
    USE SIGNAL ;
    PORT
      LAYER M3 ;
        RECT  31.284 17.242 31.302 17.28 ;
    END
  END o_x0[224]
  PIN o_x0[225]
    DIRECTION OUTPUT ;
    USE SIGNAL ;
    PORT
      LAYER M5 ;
        RECT  31.392 17.196 31.416 17.28 ;
    END
  END o_x0[225]
  PIN o_x0[226]
    DIRECTION OUTPUT ;
    USE SIGNAL ;
    PORT
      LAYER M3 ;
        RECT  31.5 17.242 31.518 17.28 ;
    END
  END o_x0[226]
  PIN o_x0[227]
    DIRECTION OUTPUT ;
    USE SIGNAL ;
    PORT
      LAYER M5 ;
        RECT  31.584 17.196 31.608 17.28 ;
    END
  END o_x0[227]
  PIN o_x0[228]
    DIRECTION OUTPUT ;
    USE SIGNAL ;
    PORT
      LAYER M3 ;
        RECT  31.68 17.242 31.698 17.28 ;
    END
  END o_x0[228]
  PIN o_x0[229]
    DIRECTION OUTPUT ;
    USE SIGNAL ;
    PORT
      LAYER M5 ;
        RECT  31.776 17.196 31.8 17.28 ;
    END
  END o_x0[229]
  PIN o_x0[22]
    DIRECTION OUTPUT ;
    USE SIGNAL ;
    PORT
      LAYER M3 ;
        RECT  12.528 17.242 12.546 17.28 ;
    END
  END o_x0[22]
  PIN o_x0[230]
    DIRECTION OUTPUT ;
    USE SIGNAL ;
    PORT
      LAYER M3 ;
        RECT  31.86 17.242 31.878 17.28 ;
    END
  END o_x0[230]
  PIN o_x0[231]
    DIRECTION OUTPUT ;
    USE SIGNAL ;
    PORT
      LAYER M5 ;
        RECT  31.968 17.196 31.992 17.28 ;
    END
  END o_x0[231]
  PIN o_x0[232]
    DIRECTION OUTPUT ;
    USE SIGNAL ;
    PORT
      LAYER M3 ;
        RECT  32.076 17.242 32.094 17.28 ;
    END
  END o_x0[232]
  PIN o_x0[233]
    DIRECTION OUTPUT ;
    USE SIGNAL ;
    PORT
      LAYER M5 ;
        RECT  32.112 17.196 32.136 17.28 ;
    END
  END o_x0[233]
  PIN o_x0[234]
    DIRECTION OUTPUT ;
    USE SIGNAL ;
    PORT
      LAYER M3 ;
        RECT  32.22 17.242 32.238 17.28 ;
    END
  END o_x0[234]
  PIN o_x0[235]
    DIRECTION OUTPUT ;
    USE SIGNAL ;
    PORT
      LAYER M5 ;
        RECT  32.304 17.196 32.328 17.28 ;
    END
  END o_x0[235]
  PIN o_x0[236]
    DIRECTION OUTPUT ;
    USE SIGNAL ;
    PORT
      LAYER M3 ;
        RECT  32.4 17.242 32.418 17.28 ;
    END
  END o_x0[236]
  PIN o_x0[237]
    DIRECTION OUTPUT ;
    USE SIGNAL ;
    PORT
      LAYER M5 ;
        RECT  32.496 17.196 32.52 17.28 ;
    END
  END o_x0[237]
  PIN o_x0[238]
    DIRECTION OUTPUT ;
    USE SIGNAL ;
    PORT
      LAYER M3 ;
        RECT  32.58 17.242 32.598 17.28 ;
    END
  END o_x0[238]
  PIN o_x0[239]
    DIRECTION OUTPUT ;
    USE SIGNAL ;
    PORT
      LAYER M5 ;
        RECT  32.688 17.196 32.712 17.28 ;
    END
  END o_x0[239]
  PIN o_x0[23]
    DIRECTION OUTPUT ;
    USE SIGNAL ;
    PORT
      LAYER M5 ;
        RECT  12.624 17.196 12.648 17.28 ;
    END
  END o_x0[23]
  PIN o_x0[240]
    DIRECTION OUTPUT ;
    USE SIGNAL ;
    PORT
      LAYER M3 ;
        RECT  32.796 17.242 32.814 17.28 ;
    END
  END o_x0[240]
  PIN o_x0[241]
    DIRECTION OUTPUT ;
    USE SIGNAL ;
    PORT
      LAYER M5 ;
        RECT  32.88 17.196 32.904 17.28 ;
    END
  END o_x0[241]
  PIN o_x0[242]
    DIRECTION OUTPUT ;
    USE SIGNAL ;
    PORT
      LAYER M3 ;
        RECT  32.976 17.242 32.994 17.28 ;
    END
  END o_x0[242]
  PIN o_x0[243]
    DIRECTION OUTPUT ;
    USE SIGNAL ;
    PORT
      LAYER M5 ;
        RECT  33.072 17.196 33.096 17.28 ;
    END
  END o_x0[243]
  PIN o_x0[244]
    DIRECTION OUTPUT ;
    USE SIGNAL ;
    PORT
      LAYER M3 ;
        RECT  33.156 17.242 33.174 17.28 ;
    END
  END o_x0[244]
  PIN o_x0[245]
    DIRECTION OUTPUT ;
    USE SIGNAL ;
    PORT
      LAYER M5 ;
        RECT  33.264 17.196 33.288 17.28 ;
    END
  END o_x0[245]
  PIN o_x0[246]
    DIRECTION OUTPUT ;
    USE SIGNAL ;
    PORT
      LAYER M3 ;
        RECT  33.372 17.242 33.39 17.28 ;
    END
  END o_x0[246]
  PIN o_x0[247]
    DIRECTION OUTPUT ;
    USE SIGNAL ;
    PORT
      LAYER M5 ;
        RECT  33.456 17.196 33.48 17.28 ;
    END
  END o_x0[247]
  PIN o_x0[248]
    DIRECTION OUTPUT ;
    USE SIGNAL ;
    PORT
      LAYER M3 ;
        RECT  33.552 17.242 33.57 17.28 ;
    END
  END o_x0[248]
  PIN o_x0[249]
    DIRECTION OUTPUT ;
    USE SIGNAL ;
    PORT
      LAYER M5 ;
        RECT  33.6 17.196 33.624 17.28 ;
    END
  END o_x0[249]
  PIN o_x0[24]
    DIRECTION OUTPUT ;
    USE SIGNAL ;
    PORT
      LAYER M3 ;
        RECT  12.708 17.242 12.726 17.28 ;
    END
  END o_x0[24]
  PIN o_x0[250]
    DIRECTION OUTPUT ;
    USE SIGNAL ;
    PORT
      LAYER M3 ;
        RECT  33.696 17.242 33.714 17.28 ;
    END
  END o_x0[250]
  PIN o_x0[251]
    DIRECTION OUTPUT ;
    USE SIGNAL ;
    PORT
      LAYER M5 ;
        RECT  33.792 17.196 33.816 17.28 ;
    END
  END o_x0[251]
  PIN o_x0[252]
    DIRECTION OUTPUT ;
    USE SIGNAL ;
    PORT
      LAYER M3 ;
        RECT  33.876 17.242 33.894 17.28 ;
    END
  END o_x0[252]
  PIN o_x0[253]
    DIRECTION OUTPUT ;
    USE SIGNAL ;
    PORT
      LAYER M5 ;
        RECT  33.984 17.196 34.008 17.28 ;
    END
  END o_x0[253]
  PIN o_x0[254]
    DIRECTION OUTPUT ;
    USE SIGNAL ;
    PORT
      LAYER M3 ;
        RECT  34.092 17.242 34.11 17.28 ;
    END
  END o_x0[254]
  PIN o_x0[255]
    DIRECTION OUTPUT ;
    USE SIGNAL ;
    PORT
      LAYER M5 ;
        RECT  34.176 17.196 34.2 17.28 ;
    END
  END o_x0[255]
  PIN o_x0[256]
    DIRECTION OUTPUT ;
    USE SIGNAL ;
    PORT
      LAYER M5 ;
        RECT  7.584 17.196 7.608 17.28 ;
    END
  END o_x0[256]
  PIN o_x0[257]
    DIRECTION OUTPUT ;
    USE SIGNAL ;
    PORT
      LAYER M3 ;
        RECT  7.668 17.242 7.686 17.28 ;
    END
  END o_x0[257]
  PIN o_x0[258]
    DIRECTION OUTPUT ;
    USE SIGNAL ;
    PORT
      LAYER M5 ;
        RECT  7.776 17.196 7.8 17.28 ;
    END
  END o_x0[258]
  PIN o_x0[259]
    DIRECTION OUTPUT ;
    USE SIGNAL ;
    PORT
      LAYER M3 ;
        RECT  7.884 17.242 7.902 17.28 ;
    END
  END o_x0[259]
  PIN o_x0[25]
    DIRECTION OUTPUT ;
    USE SIGNAL ;
    PORT
      LAYER M5 ;
        RECT  12.816 17.196 12.84 17.28 ;
    END
  END o_x0[25]
  PIN o_x0[260]
    DIRECTION OUTPUT ;
    USE SIGNAL ;
    PORT
      LAYER M5 ;
        RECT  7.968 17.196 7.992 17.28 ;
    END
  END o_x0[260]
  PIN o_x0[261]
    DIRECTION OUTPUT ;
    USE SIGNAL ;
    PORT
      LAYER M3 ;
        RECT  8.064 17.242 8.082 17.28 ;
    END
  END o_x0[261]
  PIN o_x0[262]
    DIRECTION OUTPUT ;
    USE SIGNAL ;
    PORT
      LAYER M5 ;
        RECT  8.16 17.196 8.184 17.28 ;
    END
  END o_x0[262]
  PIN o_x0[263]
    DIRECTION OUTPUT ;
    USE SIGNAL ;
    PORT
      LAYER M3 ;
        RECT  8.244 17.242 8.262 17.28 ;
    END
  END o_x0[263]
  PIN o_x0[264]
    DIRECTION OUTPUT ;
    USE SIGNAL ;
    PORT
      LAYER M5 ;
        RECT  8.352 17.196 8.376 17.28 ;
    END
  END o_x0[264]
  PIN o_x0[265]
    DIRECTION OUTPUT ;
    USE SIGNAL ;
    PORT
      LAYER M3 ;
        RECT  8.46 17.242 8.478 17.28 ;
    END
  END o_x0[265]
  PIN o_x0[266]
    DIRECTION OUTPUT ;
    USE SIGNAL ;
    PORT
      LAYER M3 ;
        RECT  7.308 17.242 7.326 17.28 ;
    END
  END o_x0[266]
  PIN o_x0[267]
    DIRECTION OUTPUT ;
    USE SIGNAL ;
    PORT
      LAYER M5 ;
        RECT  7.392 17.196 7.416 17.28 ;
    END
  END o_x0[267]
  PIN o_x0[268]
    DIRECTION OUTPUT ;
    USE SIGNAL ;
    PORT
      LAYER M3 ;
        RECT  7.488 17.242 7.506 17.28 ;
    END
  END o_x0[268]
  PIN o_x0[269]
    DIRECTION OUTPUT ;
    USE SIGNAL ;
    PORT
      LAYER M5 ;
        RECT  9.456 17.196 9.48 17.28 ;
    END
  END o_x0[269]
  PIN o_x0[26]
    DIRECTION OUTPUT ;
    USE SIGNAL ;
    PORT
      LAYER M3 ;
        RECT  12.852 17.242 12.87 17.28 ;
    END
  END o_x0[26]
  PIN o_x0[270]
    DIRECTION OUTPUT ;
    USE SIGNAL ;
    PORT
      LAYER M3 ;
        RECT  9.54 17.242 9.558 17.28 ;
    END
  END o_x0[270]
  PIN o_x0[271]
    DIRECTION OUTPUT ;
    USE SIGNAL ;
    PORT
      LAYER M5 ;
        RECT  9.648 17.196 9.672 17.28 ;
    END
  END o_x0[271]
  PIN o_x0[272]
    DIRECTION OUTPUT ;
    USE SIGNAL ;
    PORT
      LAYER M3 ;
        RECT  9.756 17.242 9.774 17.28 ;
    END
  END o_x0[272]
  PIN o_x0[273]
    DIRECTION OUTPUT ;
    USE SIGNAL ;
    PORT
      LAYER M5 ;
        RECT  9.84 17.196 9.864 17.28 ;
    END
  END o_x0[273]
  PIN o_x0[274]
    DIRECTION OUTPUT ;
    USE SIGNAL ;
    PORT
      LAYER M3 ;
        RECT  9.9 17.242 9.918 17.28 ;
    END
  END o_x0[274]
  PIN o_x0[275]
    DIRECTION OUTPUT ;
    USE SIGNAL ;
    PORT
      LAYER M5 ;
        RECT  9.984 17.196 10.008 17.28 ;
    END
  END o_x0[275]
  PIN o_x0[276]
    DIRECTION OUTPUT ;
    USE SIGNAL ;
    PORT
      LAYER M3 ;
        RECT  10.08 17.242 10.098 17.28 ;
    END
  END o_x0[276]
  PIN o_x0[277]
    DIRECTION OUTPUT ;
    USE SIGNAL ;
    PORT
      LAYER M5 ;
        RECT  10.176 17.196 10.2 17.28 ;
    END
  END o_x0[277]
  PIN o_x0[278]
    DIRECTION OUTPUT ;
    USE SIGNAL ;
    PORT
      LAYER M3 ;
        RECT  10.26 17.242 10.278 17.28 ;
    END
  END o_x0[278]
  PIN o_x0[279]
    DIRECTION OUTPUT ;
    USE SIGNAL ;
    PORT
      LAYER M5 ;
        RECT  10.368 17.196 10.392 17.28 ;
    END
  END o_x0[279]
  PIN o_x0[27]
    DIRECTION OUTPUT ;
    USE SIGNAL ;
    PORT
      LAYER M5 ;
        RECT  12.96 17.196 12.984 17.28 ;
    END
  END o_x0[27]
  PIN o_x0[280]
    DIRECTION OUTPUT ;
    USE SIGNAL ;
    PORT
      LAYER M3 ;
        RECT  58.068 17.242 58.086 17.28 ;
    END
  END o_x0[280]
  PIN o_x0[281]
    DIRECTION OUTPUT ;
    USE SIGNAL ;
    PORT
      LAYER M5 ;
        RECT  58.176 17.196 58.2 17.28 ;
    END
  END o_x0[281]
  PIN o_x0[282]
    DIRECTION OUTPUT ;
    USE SIGNAL ;
    PORT
      LAYER M3 ;
        RECT  58.284 17.242 58.302 17.28 ;
    END
  END o_x0[282]
  PIN o_x0[28]
    DIRECTION OUTPUT ;
    USE SIGNAL ;
    PORT
      LAYER M3 ;
        RECT  13.068 17.242 13.086 17.28 ;
    END
  END o_x0[28]
  PIN o_x0[29]
    DIRECTION OUTPUT ;
    USE SIGNAL ;
    PORT
      LAYER M5 ;
        RECT  13.152 17.196 13.176 17.28 ;
    END
  END o_x0[29]
  PIN o_x0[2]
    DIRECTION OUTPUT ;
    USE SIGNAL ;
    PORT
      LAYER M3 ;
        RECT  10.656 17.242 10.674 17.28 ;
    END
  END o_x0[2]
  PIN o_x0[30]
    DIRECTION OUTPUT ;
    USE SIGNAL ;
    PORT
      LAYER M3 ;
        RECT  13.248 17.242 13.266 17.28 ;
    END
  END o_x0[30]
  PIN o_x0[31]
    DIRECTION OUTPUT ;
    USE SIGNAL ;
    PORT
      LAYER M5 ;
        RECT  13.344 17.196 13.368 17.28 ;
    END
  END o_x0[31]
  PIN o_x0[32]
    DIRECTION OUTPUT ;
    USE SIGNAL ;
    PORT
      LAYER M3 ;
        RECT  13.428 17.242 13.446 17.28 ;
    END
  END o_x0[32]
  PIN o_x0[33]
    DIRECTION OUTPUT ;
    USE SIGNAL ;
    PORT
      LAYER M5 ;
        RECT  13.536 17.196 13.56 17.28 ;
    END
  END o_x0[33]
  PIN o_x0[34]
    DIRECTION OUTPUT ;
    USE SIGNAL ;
    PORT
      LAYER M3 ;
        RECT  13.644 17.242 13.662 17.28 ;
    END
  END o_x0[34]
  PIN o_x0[35]
    DIRECTION OUTPUT ;
    USE SIGNAL ;
    PORT
      LAYER M5 ;
        RECT  13.728 17.196 13.752 17.28 ;
    END
  END o_x0[35]
  PIN o_x0[36]
    DIRECTION OUTPUT ;
    USE SIGNAL ;
    PORT
      LAYER M3 ;
        RECT  13.824 17.242 13.842 17.28 ;
    END
  END o_x0[36]
  PIN o_x0[37]
    DIRECTION OUTPUT ;
    USE SIGNAL ;
    PORT
      LAYER M5 ;
        RECT  13.92 17.196 13.944 17.28 ;
    END
  END o_x0[37]
  PIN o_x0[38]
    DIRECTION OUTPUT ;
    USE SIGNAL ;
    PORT
      LAYER M3 ;
        RECT  14.004 17.242 14.022 17.28 ;
    END
  END o_x0[38]
  PIN o_x0[39]
    DIRECTION OUTPUT ;
    USE SIGNAL ;
    PORT
      LAYER M5 ;
        RECT  14.112 17.196 14.136 17.28 ;
    END
  END o_x0[39]
  PIN o_x0[3]
    DIRECTION OUTPUT ;
    USE SIGNAL ;
    PORT
      LAYER M5 ;
        RECT  10.752 17.196 10.776 17.28 ;
    END
  END o_x0[3]
  PIN o_x0[40]
    DIRECTION OUTPUT ;
    USE SIGNAL ;
    PORT
      LAYER M3 ;
        RECT  14.22 17.242 14.238 17.28 ;
    END
  END o_x0[40]
  PIN o_x0[41]
    DIRECTION OUTPUT ;
    USE SIGNAL ;
    PORT
      LAYER M5 ;
        RECT  14.304 17.196 14.328 17.28 ;
    END
  END o_x0[41]
  PIN o_x0[42]
    DIRECTION OUTPUT ;
    USE SIGNAL ;
    PORT
      LAYER M3 ;
        RECT  14.364 17.242 14.382 17.28 ;
    END
  END o_x0[42]
  PIN o_x0[43]
    DIRECTION OUTPUT ;
    USE SIGNAL ;
    PORT
      LAYER M5 ;
        RECT  14.448 17.196 14.472 17.28 ;
    END
  END o_x0[43]
  PIN o_x0[44]
    DIRECTION OUTPUT ;
    USE SIGNAL ;
    PORT
      LAYER M3 ;
        RECT  14.544 17.242 14.562 17.28 ;
    END
  END o_x0[44]
  PIN o_x0[45]
    DIRECTION OUTPUT ;
    USE SIGNAL ;
    PORT
      LAYER M5 ;
        RECT  14.64 17.196 14.664 17.28 ;
    END
  END o_x0[45]
  PIN o_x0[46]
    DIRECTION OUTPUT ;
    USE SIGNAL ;
    PORT
      LAYER M3 ;
        RECT  14.724 17.242 14.742 17.28 ;
    END
  END o_x0[46]
  PIN o_x0[47]
    DIRECTION OUTPUT ;
    USE SIGNAL ;
    PORT
      LAYER M5 ;
        RECT  14.832 17.196 14.856 17.28 ;
    END
  END o_x0[47]
  PIN o_x0[48]
    DIRECTION OUTPUT ;
    USE SIGNAL ;
    PORT
      LAYER M3 ;
        RECT  14.94 17.242 14.958 17.28 ;
    END
  END o_x0[48]
  PIN o_x0[49]
    DIRECTION OUTPUT ;
    USE SIGNAL ;
    PORT
      LAYER M5 ;
        RECT  15.024 17.196 15.048 17.28 ;
    END
  END o_x0[49]
  PIN o_x0[4]
    DIRECTION OUTPUT ;
    USE SIGNAL ;
    PORT
      LAYER M3 ;
        RECT  10.836 17.242 10.854 17.28 ;
    END
  END o_x0[4]
  PIN o_x0[50]
    DIRECTION OUTPUT ;
    USE SIGNAL ;
    PORT
      LAYER M3 ;
        RECT  15.12 17.242 15.138 17.28 ;
    END
  END o_x0[50]
  PIN o_x0[51]
    DIRECTION OUTPUT ;
    USE SIGNAL ;
    PORT
      LAYER M5 ;
        RECT  15.216 17.196 15.24 17.28 ;
    END
  END o_x0[51]
  PIN o_x0[52]
    DIRECTION OUTPUT ;
    USE SIGNAL ;
    PORT
      LAYER M3 ;
        RECT  15.3 17.242 15.318 17.28 ;
    END
  END o_x0[52]
  PIN o_x0[53]
    DIRECTION OUTPUT ;
    USE SIGNAL ;
    PORT
      LAYER M5 ;
        RECT  15.408 17.196 15.432 17.28 ;
    END
  END o_x0[53]
  PIN o_x0[54]
    DIRECTION OUTPUT ;
    USE SIGNAL ;
    PORT
      LAYER M3 ;
        RECT  15.516 17.242 15.534 17.28 ;
    END
  END o_x0[54]
  PIN o_x0[55]
    DIRECTION OUTPUT ;
    USE SIGNAL ;
    PORT
      LAYER M5 ;
        RECT  15.6 17.196 15.624 17.28 ;
    END
  END o_x0[55]
  PIN o_x0[56]
    DIRECTION OUTPUT ;
    USE SIGNAL ;
    PORT
      LAYER M3 ;
        RECT  15.696 17.242 15.714 17.28 ;
    END
  END o_x0[56]
  PIN o_x0[57]
    DIRECTION OUTPUT ;
    USE SIGNAL ;
    PORT
      LAYER M5 ;
        RECT  15.792 17.196 15.816 17.28 ;
    END
  END o_x0[57]
  PIN o_x0[58]
    DIRECTION OUTPUT ;
    USE SIGNAL ;
    PORT
      LAYER M3 ;
        RECT  15.84 17.242 15.858 17.28 ;
    END
  END o_x0[58]
  PIN o_x0[59]
    DIRECTION OUTPUT ;
    USE SIGNAL ;
    PORT
      LAYER M5 ;
        RECT  15.936 17.196 15.96 17.28 ;
    END
  END o_x0[59]
  PIN o_x0[5]
    DIRECTION OUTPUT ;
    USE SIGNAL ;
    PORT
      LAYER M5 ;
        RECT  10.944 17.196 10.968 17.28 ;
    END
  END o_x0[5]
  PIN o_x0[60]
    DIRECTION OUTPUT ;
    USE SIGNAL ;
    PORT
      LAYER M3 ;
        RECT  16.02 17.242 16.038 17.28 ;
    END
  END o_x0[60]
  PIN o_x0[61]
    DIRECTION OUTPUT ;
    USE SIGNAL ;
    PORT
      LAYER M5 ;
        RECT  16.128 17.196 16.152 17.28 ;
    END
  END o_x0[61]
  PIN o_x0[62]
    DIRECTION OUTPUT ;
    USE SIGNAL ;
    PORT
      LAYER M3 ;
        RECT  16.236 17.242 16.254 17.28 ;
    END
  END o_x0[62]
  PIN o_x0[63]
    DIRECTION OUTPUT ;
    USE SIGNAL ;
    PORT
      LAYER M5 ;
        RECT  16.32 17.196 16.344 17.28 ;
    END
  END o_x0[63]
  PIN o_x0[64]
    DIRECTION OUTPUT ;
    USE SIGNAL ;
    PORT
      LAYER M3 ;
        RECT  16.416 17.242 16.434 17.28 ;
    END
  END o_x0[64]
  PIN o_x0[65]
    DIRECTION OUTPUT ;
    USE SIGNAL ;
    PORT
      LAYER M5 ;
        RECT  16.512 17.196 16.536 17.28 ;
    END
  END o_x0[65]
  PIN o_x0[66]
    DIRECTION OUTPUT ;
    USE SIGNAL ;
    PORT
      LAYER M3 ;
        RECT  16.596 17.242 16.614 17.28 ;
    END
  END o_x0[66]
  PIN o_x0[67]
    DIRECTION OUTPUT ;
    USE SIGNAL ;
    PORT
      LAYER M5 ;
        RECT  16.704 17.196 16.728 17.28 ;
    END
  END o_x0[67]
  PIN o_x0[68]
    DIRECTION OUTPUT ;
    USE SIGNAL ;
    PORT
      LAYER M3 ;
        RECT  16.812 17.242 16.83 17.28 ;
    END
  END o_x0[68]
  PIN o_x0[69]
    DIRECTION OUTPUT ;
    USE SIGNAL ;
    PORT
      LAYER M5 ;
        RECT  16.896 17.196 16.92 17.28 ;
    END
  END o_x0[69]
  PIN o_x0[6]
    DIRECTION OUTPUT ;
    USE SIGNAL ;
    PORT
      LAYER M3 ;
        RECT  11.052 17.242 11.07 17.28 ;
    END
  END o_x0[6]
  PIN o_x0[70]
    DIRECTION OUTPUT ;
    USE SIGNAL ;
    PORT
      LAYER M3 ;
        RECT  16.992 17.242 17.01 17.28 ;
    END
  END o_x0[70]
  PIN o_x0[71]
    DIRECTION OUTPUT ;
    USE SIGNAL ;
    PORT
      LAYER M5 ;
        RECT  17.088 17.196 17.112 17.28 ;
    END
  END o_x0[71]
  PIN o_x0[72]
    DIRECTION OUTPUT ;
    USE SIGNAL ;
    PORT
      LAYER M3 ;
        RECT  17.172 17.242 17.19 17.28 ;
    END
  END o_x0[72]
  PIN o_x0[73]
    DIRECTION OUTPUT ;
    USE SIGNAL ;
    PORT
      LAYER M5 ;
        RECT  17.28 17.196 17.304 17.28 ;
    END
  END o_x0[73]
  PIN o_x0[74]
    DIRECTION OUTPUT ;
    USE SIGNAL ;
    PORT
      LAYER M3 ;
        RECT  17.316 17.242 17.334 17.28 ;
    END
  END o_x0[74]
  PIN o_x0[75]
    DIRECTION OUTPUT ;
    USE SIGNAL ;
    PORT
      LAYER M5 ;
        RECT  17.424 17.196 17.448 17.28 ;
    END
  END o_x0[75]
  PIN o_x0[76]
    DIRECTION OUTPUT ;
    USE SIGNAL ;
    PORT
      LAYER M3 ;
        RECT  17.532 17.242 17.55 17.28 ;
    END
  END o_x0[76]
  PIN o_x0[77]
    DIRECTION OUTPUT ;
    USE SIGNAL ;
    PORT
      LAYER M5 ;
        RECT  17.616 17.196 17.64 17.28 ;
    END
  END o_x0[77]
  PIN o_x0[78]
    DIRECTION OUTPUT ;
    USE SIGNAL ;
    PORT
      LAYER M3 ;
        RECT  17.712 17.242 17.73 17.28 ;
    END
  END o_x0[78]
  PIN o_x0[79]
    DIRECTION OUTPUT ;
    USE SIGNAL ;
    PORT
      LAYER M5 ;
        RECT  17.808 17.196 17.832 17.28 ;
    END
  END o_x0[79]
  PIN o_x0[7]
    DIRECTION OUTPUT ;
    USE SIGNAL ;
    PORT
      LAYER M5 ;
        RECT  11.136 17.196 11.16 17.28 ;
    END
  END o_x0[7]
  PIN o_x0[80]
    DIRECTION OUTPUT ;
    USE SIGNAL ;
    PORT
      LAYER M3 ;
        RECT  17.892 17.242 17.91 17.28 ;
    END
  END o_x0[80]
  PIN o_x0[81]
    DIRECTION OUTPUT ;
    USE SIGNAL ;
    PORT
      LAYER M5 ;
        RECT  18 17.196 18.024 17.28 ;
    END
  END o_x0[81]
  PIN o_x0[82]
    DIRECTION OUTPUT ;
    USE SIGNAL ;
    PORT
      LAYER M3 ;
        RECT  18.108 17.242 18.126 17.28 ;
    END
  END o_x0[82]
  PIN o_x0[83]
    DIRECTION OUTPUT ;
    USE SIGNAL ;
    PORT
      LAYER M5 ;
        RECT  18.192 17.196 18.216 17.28 ;
    END
  END o_x0[83]
  PIN o_x0[84]
    DIRECTION OUTPUT ;
    USE SIGNAL ;
    PORT
      LAYER M3 ;
        RECT  18.288 17.242 18.306 17.28 ;
    END
  END o_x0[84]
  PIN o_x0[85]
    DIRECTION OUTPUT ;
    USE SIGNAL ;
    PORT
      LAYER M5 ;
        RECT  18.384 17.196 18.408 17.28 ;
    END
  END o_x0[85]
  PIN o_x0[86]
    DIRECTION OUTPUT ;
    USE SIGNAL ;
    PORT
      LAYER M3 ;
        RECT  18.468 17.242 18.486 17.28 ;
    END
  END o_x0[86]
  PIN o_x0[87]
    DIRECTION OUTPUT ;
    USE SIGNAL ;
    PORT
      LAYER M5 ;
        RECT  18.576 17.196 18.6 17.28 ;
    END
  END o_x0[87]
  PIN o_x0[88]
    DIRECTION OUTPUT ;
    USE SIGNAL ;
    PORT
      LAYER M3 ;
        RECT  18.684 17.242 18.702 17.28 ;
    END
  END o_x0[88]
  PIN o_x0[89]
    DIRECTION OUTPUT ;
    USE SIGNAL ;
    PORT
      LAYER M5 ;
        RECT  18.768 17.196 18.792 17.28 ;
    END
  END o_x0[89]
  PIN o_x0[8]
    DIRECTION OUTPUT ;
    USE SIGNAL ;
    PORT
      LAYER M3 ;
        RECT  11.232 17.242 11.25 17.28 ;
    END
  END o_x0[8]
  PIN o_x0[90]
    DIRECTION OUTPUT ;
    USE SIGNAL ;
    PORT
      LAYER M3 ;
        RECT  18.828 17.242 18.846 17.28 ;
    END
  END o_x0[90]
  PIN o_x0[91]
    DIRECTION OUTPUT ;
    USE SIGNAL ;
    PORT
      LAYER M5 ;
        RECT  18.912 17.196 18.936 17.28 ;
    END
  END o_x0[91]
  PIN o_x0[92]
    DIRECTION OUTPUT ;
    USE SIGNAL ;
    PORT
      LAYER M3 ;
        RECT  19.008 17.242 19.026 17.28 ;
    END
  END o_x0[92]
  PIN o_x0[93]
    DIRECTION OUTPUT ;
    USE SIGNAL ;
    PORT
      LAYER M5 ;
        RECT  19.104 17.196 19.128 17.28 ;
    END
  END o_x0[93]
  PIN o_x0[94]
    DIRECTION OUTPUT ;
    USE SIGNAL ;
    PORT
      LAYER M3 ;
        RECT  19.188 17.242 19.206 17.28 ;
    END
  END o_x0[94]
  PIN o_x0[95]
    DIRECTION OUTPUT ;
    USE SIGNAL ;
    PORT
      LAYER M5 ;
        RECT  19.296 17.196 19.32 17.28 ;
    END
  END o_x0[95]
  PIN o_x0[96]
    DIRECTION OUTPUT ;
    USE SIGNAL ;
    PORT
      LAYER M3 ;
        RECT  19.404 17.242 19.422 17.28 ;
    END
  END o_x0[96]
  PIN o_x0[97]
    DIRECTION OUTPUT ;
    USE SIGNAL ;
    PORT
      LAYER M5 ;
        RECT  19.488 17.196 19.512 17.28 ;
    END
  END o_x0[97]
  PIN o_x0[98]
    DIRECTION OUTPUT ;
    USE SIGNAL ;
    PORT
      LAYER M3 ;
        RECT  19.584 17.242 19.602 17.28 ;
    END
  END o_x0[98]
  PIN o_x0[99]
    DIRECTION OUTPUT ;
    USE SIGNAL ;
    PORT
      LAYER M5 ;
        RECT  19.68 17.196 19.704 17.28 ;
    END
  END o_x0[99]
  PIN o_x0[9]
    DIRECTION OUTPUT ;
    USE SIGNAL ;
    PORT
      LAYER M5 ;
        RECT  11.328 17.196 11.352 17.28 ;
    END
  END o_x0[9]
  PIN o_x1[0]
    DIRECTION OUTPUT ;
    USE SIGNAL ;
    PORT
      LAYER M3 ;
        RECT  34.272 17.242 34.29 17.28 ;
    END
  END o_x1[0]
  PIN o_x1[100]
    DIRECTION OUTPUT ;
    USE SIGNAL ;
    PORT
      LAYER M3 ;
        RECT  43.596 17.242 43.614 17.28 ;
    END
  END o_x1[100]
  PIN o_x1[101]
    DIRECTION OUTPUT ;
    USE SIGNAL ;
    PORT
      LAYER M5 ;
        RECT  43.68 17.196 43.704 17.28 ;
    END
  END o_x1[101]
  PIN o_x1[102]
    DIRECTION OUTPUT ;
    USE SIGNAL ;
    PORT
      LAYER M3 ;
        RECT  43.776 17.242 43.794 17.28 ;
    END
  END o_x1[102]
  PIN o_x1[103]
    DIRECTION OUTPUT ;
    USE SIGNAL ;
    PORT
      LAYER M5 ;
        RECT  43.872 17.196 43.896 17.28 ;
    END
  END o_x1[103]
  PIN o_x1[104]
    DIRECTION OUTPUT ;
    USE SIGNAL ;
    PORT
      LAYER M3 ;
        RECT  43.92 17.242 43.938 17.28 ;
    END
  END o_x1[104]
  PIN o_x1[105]
    DIRECTION OUTPUT ;
    USE SIGNAL ;
    PORT
      LAYER M5 ;
        RECT  44.016 17.196 44.04 17.28 ;
    END
  END o_x1[105]
  PIN o_x1[106]
    DIRECTION OUTPUT ;
    USE SIGNAL ;
    PORT
      LAYER M3 ;
        RECT  44.1 17.242 44.118 17.28 ;
    END
  END o_x1[106]
  PIN o_x1[107]
    DIRECTION OUTPUT ;
    USE SIGNAL ;
    PORT
      LAYER M5 ;
        RECT  44.208 17.196 44.232 17.28 ;
    END
  END o_x1[107]
  PIN o_x1[108]
    DIRECTION OUTPUT ;
    USE SIGNAL ;
    PORT
      LAYER M3 ;
        RECT  44.316 17.242 44.334 17.28 ;
    END
  END o_x1[108]
  PIN o_x1[109]
    DIRECTION OUTPUT ;
    USE SIGNAL ;
    PORT
      LAYER M5 ;
        RECT  44.4 17.196 44.424 17.28 ;
    END
  END o_x1[109]
  PIN o_x1[10]
    DIRECTION OUTPUT ;
    USE SIGNAL ;
    PORT
      LAYER M3 ;
        RECT  35.172 17.242 35.19 17.28 ;
    END
  END o_x1[10]
  PIN o_x1[110]
    DIRECTION OUTPUT ;
    USE SIGNAL ;
    PORT
      LAYER M3 ;
        RECT  44.496 17.242 44.514 17.28 ;
    END
  END o_x1[110]
  PIN o_x1[111]
    DIRECTION OUTPUT ;
    USE SIGNAL ;
    PORT
      LAYER M5 ;
        RECT  44.592 17.196 44.616 17.28 ;
    END
  END o_x1[111]
  PIN o_x1[112]
    DIRECTION OUTPUT ;
    USE SIGNAL ;
    PORT
      LAYER M3 ;
        RECT  44.676 17.242 44.694 17.28 ;
    END
  END o_x1[112]
  PIN o_x1[113]
    DIRECTION OUTPUT ;
    USE SIGNAL ;
    PORT
      LAYER M5 ;
        RECT  44.784 17.196 44.808 17.28 ;
    END
  END o_x1[113]
  PIN o_x1[114]
    DIRECTION OUTPUT ;
    USE SIGNAL ;
    PORT
      LAYER M3 ;
        RECT  44.892 17.242 44.91 17.28 ;
    END
  END o_x1[114]
  PIN o_x1[115]
    DIRECTION OUTPUT ;
    USE SIGNAL ;
    PORT
      LAYER M5 ;
        RECT  44.976 17.196 45 17.28 ;
    END
  END o_x1[115]
  PIN o_x1[116]
    DIRECTION OUTPUT ;
    USE SIGNAL ;
    PORT
      LAYER M3 ;
        RECT  45.072 17.242 45.09 17.28 ;
    END
  END o_x1[116]
  PIN o_x1[117]
    DIRECTION OUTPUT ;
    USE SIGNAL ;
    PORT
      LAYER M5 ;
        RECT  45.168 17.196 45.192 17.28 ;
    END
  END o_x1[117]
  PIN o_x1[118]
    DIRECTION OUTPUT ;
    USE SIGNAL ;
    PORT
      LAYER M3 ;
        RECT  45.252 17.242 45.27 17.28 ;
    END
  END o_x1[118]
  PIN o_x1[119]
    DIRECTION OUTPUT ;
    USE SIGNAL ;
    PORT
      LAYER M5 ;
        RECT  45.36 17.196 45.384 17.28 ;
    END
  END o_x1[119]
  PIN o_x1[11]
    DIRECTION OUTPUT ;
    USE SIGNAL ;
    PORT
      LAYER M5 ;
        RECT  35.28 17.196 35.304 17.28 ;
    END
  END o_x1[11]
  PIN o_x1[120]
    DIRECTION OUTPUT ;
    USE SIGNAL ;
    PORT
      LAYER M3 ;
        RECT  45.396 17.242 45.414 17.28 ;
    END
  END o_x1[120]
  PIN o_x1[121]
    DIRECTION OUTPUT ;
    USE SIGNAL ;
    PORT
      LAYER M5 ;
        RECT  45.504 17.196 45.528 17.28 ;
    END
  END o_x1[121]
  PIN o_x1[122]
    DIRECTION OUTPUT ;
    USE SIGNAL ;
    PORT
      LAYER M3 ;
        RECT  45.612 17.242 45.63 17.28 ;
    END
  END o_x1[122]
  PIN o_x1[123]
    DIRECTION OUTPUT ;
    USE SIGNAL ;
    PORT
      LAYER M5 ;
        RECT  45.696 17.196 45.72 17.28 ;
    END
  END o_x1[123]
  PIN o_x1[124]
    DIRECTION OUTPUT ;
    USE SIGNAL ;
    PORT
      LAYER M3 ;
        RECT  45.792 17.242 45.81 17.28 ;
    END
  END o_x1[124]
  PIN o_x1[125]
    DIRECTION OUTPUT ;
    USE SIGNAL ;
    PORT
      LAYER M5 ;
        RECT  45.888 17.196 45.912 17.28 ;
    END
  END o_x1[125]
  PIN o_x1[126]
    DIRECTION OUTPUT ;
    USE SIGNAL ;
    PORT
      LAYER M3 ;
        RECT  45.972 17.242 45.99 17.28 ;
    END
  END o_x1[126]
  PIN o_x1[127]
    DIRECTION OUTPUT ;
    USE SIGNAL ;
    PORT
      LAYER M5 ;
        RECT  46.08 17.196 46.104 17.28 ;
    END
  END o_x1[127]
  PIN o_x1[128]
    DIRECTION OUTPUT ;
    USE SIGNAL ;
    PORT
      LAYER M3 ;
        RECT  46.188 17.242 46.206 17.28 ;
    END
  END o_x1[128]
  PIN o_x1[129]
    DIRECTION OUTPUT ;
    USE SIGNAL ;
    PORT
      LAYER M5 ;
        RECT  46.272 17.196 46.296 17.28 ;
    END
  END o_x1[129]
  PIN o_x1[12]
    DIRECTION OUTPUT ;
    USE SIGNAL ;
    PORT
      LAYER M3 ;
        RECT  35.388 17.242 35.406 17.28 ;
    END
  END o_x1[12]
  PIN o_x1[130]
    DIRECTION OUTPUT ;
    USE SIGNAL ;
    PORT
      LAYER M3 ;
        RECT  46.368 17.242 46.386 17.28 ;
    END
  END o_x1[130]
  PIN o_x1[131]
    DIRECTION OUTPUT ;
    USE SIGNAL ;
    PORT
      LAYER M5 ;
        RECT  46.464 17.196 46.488 17.28 ;
    END
  END o_x1[131]
  PIN o_x1[132]
    DIRECTION OUTPUT ;
    USE SIGNAL ;
    PORT
      LAYER M3 ;
        RECT  46.548 17.242 46.566 17.28 ;
    END
  END o_x1[132]
  PIN o_x1[133]
    DIRECTION OUTPUT ;
    USE SIGNAL ;
    PORT
      LAYER M5 ;
        RECT  46.656 17.196 46.68 17.28 ;
    END
  END o_x1[133]
  PIN o_x1[134]
    DIRECTION OUTPUT ;
    USE SIGNAL ;
    PORT
      LAYER M3 ;
        RECT  46.764 17.242 46.782 17.28 ;
    END
  END o_x1[134]
  PIN o_x1[135]
    DIRECTION OUTPUT ;
    USE SIGNAL ;
    PORT
      LAYER M5 ;
        RECT  46.848 17.196 46.872 17.28 ;
    END
  END o_x1[135]
  PIN o_x1[136]
    DIRECTION OUTPUT ;
    USE SIGNAL ;
    PORT
      LAYER M3 ;
        RECT  46.908 17.242 46.926 17.28 ;
    END
  END o_x1[136]
  PIN o_x1[137]
    DIRECTION OUTPUT ;
    USE SIGNAL ;
    PORT
      LAYER M5 ;
        RECT  46.992 17.196 47.016 17.28 ;
    END
  END o_x1[137]
  PIN o_x1[138]
    DIRECTION OUTPUT ;
    USE SIGNAL ;
    PORT
      LAYER M3 ;
        RECT  47.088 17.242 47.106 17.28 ;
    END
  END o_x1[138]
  PIN o_x1[139]
    DIRECTION OUTPUT ;
    USE SIGNAL ;
    PORT
      LAYER M5 ;
        RECT  47.184 17.196 47.208 17.28 ;
    END
  END o_x1[139]
  PIN o_x1[13]
    DIRECTION OUTPUT ;
    USE SIGNAL ;
    PORT
      LAYER M5 ;
        RECT  35.472 17.196 35.496 17.28 ;
    END
  END o_x1[13]
  PIN o_x1[140]
    DIRECTION OUTPUT ;
    USE SIGNAL ;
    PORT
      LAYER M3 ;
        RECT  47.268 17.242 47.286 17.28 ;
    END
  END o_x1[140]
  PIN o_x1[141]
    DIRECTION OUTPUT ;
    USE SIGNAL ;
    PORT
      LAYER M5 ;
        RECT  47.376 17.196 47.4 17.28 ;
    END
  END o_x1[141]
  PIN o_x1[142]
    DIRECTION OUTPUT ;
    USE SIGNAL ;
    PORT
      LAYER M3 ;
        RECT  47.484 17.242 47.502 17.28 ;
    END
  END o_x1[142]
  PIN o_x1[143]
    DIRECTION OUTPUT ;
    USE SIGNAL ;
    PORT
      LAYER M5 ;
        RECT  47.568 17.196 47.592 17.28 ;
    END
  END o_x1[143]
  PIN o_x1[144]
    DIRECTION OUTPUT ;
    USE SIGNAL ;
    PORT
      LAYER M3 ;
        RECT  47.664 17.242 47.682 17.28 ;
    END
  END o_x1[144]
  PIN o_x1[145]
    DIRECTION OUTPUT ;
    USE SIGNAL ;
    PORT
      LAYER M5 ;
        RECT  47.76 17.196 47.784 17.28 ;
    END
  END o_x1[145]
  PIN o_x1[146]
    DIRECTION OUTPUT ;
    USE SIGNAL ;
    PORT
      LAYER M3 ;
        RECT  47.844 17.242 47.862 17.28 ;
    END
  END o_x1[146]
  PIN o_x1[147]
    DIRECTION OUTPUT ;
    USE SIGNAL ;
    PORT
      LAYER M5 ;
        RECT  47.952 17.196 47.976 17.28 ;
    END
  END o_x1[147]
  PIN o_x1[148]
    DIRECTION OUTPUT ;
    USE SIGNAL ;
    PORT
      LAYER M3 ;
        RECT  48.06 17.242 48.078 17.28 ;
    END
  END o_x1[148]
  PIN o_x1[149]
    DIRECTION OUTPUT ;
    USE SIGNAL ;
    PORT
      LAYER M5 ;
        RECT  48.144 17.196 48.168 17.28 ;
    END
  END o_x1[149]
  PIN o_x1[14]
    DIRECTION OUTPUT ;
    USE SIGNAL ;
    PORT
      LAYER M3 ;
        RECT  35.568 17.242 35.586 17.28 ;
    END
  END o_x1[14]
  PIN o_x1[150]
    DIRECTION OUTPUT ;
    USE SIGNAL ;
    PORT
      LAYER M3 ;
        RECT  48.24 17.242 48.258 17.28 ;
    END
  END o_x1[150]
  PIN o_x1[151]
    DIRECTION OUTPUT ;
    USE SIGNAL ;
    PORT
      LAYER M5 ;
        RECT  48.336 17.196 48.36 17.28 ;
    END
  END o_x1[151]
  PIN o_x1[152]
    DIRECTION OUTPUT ;
    USE SIGNAL ;
    PORT
      LAYER M3 ;
        RECT  48.384 17.242 48.402 17.28 ;
    END
  END o_x1[152]
  PIN o_x1[153]
    DIRECTION OUTPUT ;
    USE SIGNAL ;
    PORT
      LAYER M5 ;
        RECT  48.48 17.196 48.504 17.28 ;
    END
  END o_x1[153]
  PIN o_x1[154]
    DIRECTION OUTPUT ;
    USE SIGNAL ;
    PORT
      LAYER M3 ;
        RECT  48.564 17.242 48.582 17.28 ;
    END
  END o_x1[154]
  PIN o_x1[155]
    DIRECTION OUTPUT ;
    USE SIGNAL ;
    PORT
      LAYER M5 ;
        RECT  48.672 17.196 48.696 17.28 ;
    END
  END o_x1[155]
  PIN o_x1[156]
    DIRECTION OUTPUT ;
    USE SIGNAL ;
    PORT
      LAYER M3 ;
        RECT  48.78 17.242 48.798 17.28 ;
    END
  END o_x1[156]
  PIN o_x1[157]
    DIRECTION OUTPUT ;
    USE SIGNAL ;
    PORT
      LAYER M5 ;
        RECT  48.864 17.196 48.888 17.28 ;
    END
  END o_x1[157]
  PIN o_x1[158]
    DIRECTION OUTPUT ;
    USE SIGNAL ;
    PORT
      LAYER M3 ;
        RECT  48.96 17.242 48.978 17.28 ;
    END
  END o_x1[158]
  PIN o_x1[159]
    DIRECTION OUTPUT ;
    USE SIGNAL ;
    PORT
      LAYER M5 ;
        RECT  49.056 17.196 49.08 17.28 ;
    END
  END o_x1[159]
  PIN o_x1[15]
    DIRECTION OUTPUT ;
    USE SIGNAL ;
    PORT
      LAYER M5 ;
        RECT  35.664 17.196 35.688 17.28 ;
    END
  END o_x1[15]
  PIN o_x1[160]
    DIRECTION OUTPUT ;
    USE SIGNAL ;
    PORT
      LAYER M3 ;
        RECT  49.14 17.242 49.158 17.28 ;
    END
  END o_x1[160]
  PIN o_x1[161]
    DIRECTION OUTPUT ;
    USE SIGNAL ;
    PORT
      LAYER M5 ;
        RECT  49.248 17.196 49.272 17.28 ;
    END
  END o_x1[161]
  PIN o_x1[162]
    DIRECTION OUTPUT ;
    USE SIGNAL ;
    PORT
      LAYER M3 ;
        RECT  49.356 17.242 49.374 17.28 ;
    END
  END o_x1[162]
  PIN o_x1[163]
    DIRECTION OUTPUT ;
    USE SIGNAL ;
    PORT
      LAYER M5 ;
        RECT  49.44 17.196 49.464 17.28 ;
    END
  END o_x1[163]
  PIN o_x1[164]
    DIRECTION OUTPUT ;
    USE SIGNAL ;
    PORT
      LAYER M3 ;
        RECT  49.536 17.242 49.554 17.28 ;
    END
  END o_x1[164]
  PIN o_x1[165]
    DIRECTION OUTPUT ;
    USE SIGNAL ;
    PORT
      LAYER M5 ;
        RECT  49.632 17.196 49.656 17.28 ;
    END
  END o_x1[165]
  PIN o_x1[166]
    DIRECTION OUTPUT ;
    USE SIGNAL ;
    PORT
      LAYER M3 ;
        RECT  49.716 17.242 49.734 17.28 ;
    END
  END o_x1[166]
  PIN o_x1[167]
    DIRECTION OUTPUT ;
    USE SIGNAL ;
    PORT
      LAYER M5 ;
        RECT  49.824 17.196 49.848 17.28 ;
    END
  END o_x1[167]
  PIN o_x1[168]
    DIRECTION OUTPUT ;
    USE SIGNAL ;
    PORT
      LAYER M3 ;
        RECT  49.86 17.242 49.878 17.28 ;
    END
  END o_x1[168]
  PIN o_x1[169]
    DIRECTION OUTPUT ;
    USE SIGNAL ;
    PORT
      LAYER M5 ;
        RECT  49.968 17.196 49.992 17.28 ;
    END
  END o_x1[169]
  PIN o_x1[16]
    DIRECTION OUTPUT ;
    USE SIGNAL ;
    PORT
      LAYER M3 ;
        RECT  35.748 17.242 35.766 17.28 ;
    END
  END o_x1[16]
  PIN o_x1[170]
    DIRECTION OUTPUT ;
    USE SIGNAL ;
    PORT
      LAYER M3 ;
        RECT  50.076 17.242 50.094 17.28 ;
    END
  END o_x1[170]
  PIN o_x1[171]
    DIRECTION OUTPUT ;
    USE SIGNAL ;
    PORT
      LAYER M5 ;
        RECT  50.16 17.196 50.184 17.28 ;
    END
  END o_x1[171]
  PIN o_x1[172]
    DIRECTION OUTPUT ;
    USE SIGNAL ;
    PORT
      LAYER M3 ;
        RECT  50.256 17.242 50.274 17.28 ;
    END
  END o_x1[172]
  PIN o_x1[173]
    DIRECTION OUTPUT ;
    USE SIGNAL ;
    PORT
      LAYER M5 ;
        RECT  50.352 17.196 50.376 17.28 ;
    END
  END o_x1[173]
  PIN o_x1[174]
    DIRECTION OUTPUT ;
    USE SIGNAL ;
    PORT
      LAYER M3 ;
        RECT  50.436 17.242 50.454 17.28 ;
    END
  END o_x1[174]
  PIN o_x1[175]
    DIRECTION OUTPUT ;
    USE SIGNAL ;
    PORT
      LAYER M5 ;
        RECT  50.544 17.196 50.568 17.28 ;
    END
  END o_x1[175]
  PIN o_x1[176]
    DIRECTION OUTPUT ;
    USE SIGNAL ;
    PORT
      LAYER M3 ;
        RECT  50.652 17.242 50.67 17.28 ;
    END
  END o_x1[176]
  PIN o_x1[177]
    DIRECTION OUTPUT ;
    USE SIGNAL ;
    PORT
      LAYER M5 ;
        RECT  50.736 17.196 50.76 17.28 ;
    END
  END o_x1[177]
  PIN o_x1[178]
    DIRECTION OUTPUT ;
    USE SIGNAL ;
    PORT
      LAYER M3 ;
        RECT  50.832 17.242 50.85 17.28 ;
    END
  END o_x1[178]
  PIN o_x1[179]
    DIRECTION OUTPUT ;
    USE SIGNAL ;
    PORT
      LAYER M5 ;
        RECT  50.928 17.196 50.952 17.28 ;
    END
  END o_x1[179]
  PIN o_x1[17]
    DIRECTION OUTPUT ;
    USE SIGNAL ;
    PORT
      LAYER M5 ;
        RECT  35.856 17.196 35.88 17.28 ;
    END
  END o_x1[17]
  PIN o_x1[180]
    DIRECTION OUTPUT ;
    USE SIGNAL ;
    PORT
      LAYER M3 ;
        RECT  51.012 17.242 51.03 17.28 ;
    END
  END o_x1[180]
  PIN o_x1[181]
    DIRECTION OUTPUT ;
    USE SIGNAL ;
    PORT
      LAYER M5 ;
        RECT  51.12 17.196 51.144 17.28 ;
    END
  END o_x1[181]
  PIN o_x1[182]
    DIRECTION OUTPUT ;
    USE SIGNAL ;
    PORT
      LAYER M3 ;
        RECT  51.228 17.242 51.246 17.28 ;
    END
  END o_x1[182]
  PIN o_x1[183]
    DIRECTION OUTPUT ;
    USE SIGNAL ;
    PORT
      LAYER M5 ;
        RECT  51.264 17.196 51.288 17.28 ;
    END
  END o_x1[183]
  PIN o_x1[184]
    DIRECTION OUTPUT ;
    USE SIGNAL ;
    PORT
      LAYER M3 ;
        RECT  51.372 17.242 51.39 17.28 ;
    END
  END o_x1[184]
  PIN o_x1[185]
    DIRECTION OUTPUT ;
    USE SIGNAL ;
    PORT
      LAYER M5 ;
        RECT  51.456 17.196 51.48 17.28 ;
    END
  END o_x1[185]
  PIN o_x1[186]
    DIRECTION OUTPUT ;
    USE SIGNAL ;
    PORT
      LAYER M3 ;
        RECT  51.552 17.242 51.57 17.28 ;
    END
  END o_x1[186]
  PIN o_x1[187]
    DIRECTION OUTPUT ;
    USE SIGNAL ;
    PORT
      LAYER M5 ;
        RECT  51.648 17.196 51.672 17.28 ;
    END
  END o_x1[187]
  PIN o_x1[188]
    DIRECTION OUTPUT ;
    USE SIGNAL ;
    PORT
      LAYER M3 ;
        RECT  51.732 17.242 51.75 17.28 ;
    END
  END o_x1[188]
  PIN o_x1[189]
    DIRECTION OUTPUT ;
    USE SIGNAL ;
    PORT
      LAYER M5 ;
        RECT  51.84 17.196 51.864 17.28 ;
    END
  END o_x1[189]
  PIN o_x1[18]
    DIRECTION OUTPUT ;
    USE SIGNAL ;
    PORT
      LAYER M3 ;
        RECT  35.964 17.242 35.982 17.28 ;
    END
  END o_x1[18]
  PIN o_x1[190]
    DIRECTION OUTPUT ;
    USE SIGNAL ;
    PORT
      LAYER M3 ;
        RECT  51.948 17.242 51.966 17.28 ;
    END
  END o_x1[190]
  PIN o_x1[191]
    DIRECTION OUTPUT ;
    USE SIGNAL ;
    PORT
      LAYER M5 ;
        RECT  52.032 17.196 52.056 17.28 ;
    END
  END o_x1[191]
  PIN o_x1[192]
    DIRECTION OUTPUT ;
    USE SIGNAL ;
    PORT
      LAYER M3 ;
        RECT  52.128 17.242 52.146 17.28 ;
    END
  END o_x1[192]
  PIN o_x1[193]
    DIRECTION OUTPUT ;
    USE SIGNAL ;
    PORT
      LAYER M5 ;
        RECT  52.224 17.196 52.248 17.28 ;
    END
  END o_x1[193]
  PIN o_x1[194]
    DIRECTION OUTPUT ;
    USE SIGNAL ;
    PORT
      LAYER M3 ;
        RECT  52.308 17.242 52.326 17.28 ;
    END
  END o_x1[194]
  PIN o_x1[195]
    DIRECTION OUTPUT ;
    USE SIGNAL ;
    PORT
      LAYER M5 ;
        RECT  52.416 17.196 52.44 17.28 ;
    END
  END o_x1[195]
  PIN o_x1[196]
    DIRECTION OUTPUT ;
    USE SIGNAL ;
    PORT
      LAYER M3 ;
        RECT  52.524 17.242 52.542 17.28 ;
    END
  END o_x1[196]
  PIN o_x1[197]
    DIRECTION OUTPUT ;
    USE SIGNAL ;
    PORT
      LAYER M5 ;
        RECT  52.608 17.196 52.632 17.28 ;
    END
  END o_x1[197]
  PIN o_x1[198]
    DIRECTION OUTPUT ;
    USE SIGNAL ;
    PORT
      LAYER M3 ;
        RECT  52.704 17.242 52.722 17.28 ;
    END
  END o_x1[198]
  PIN o_x1[199]
    DIRECTION OUTPUT ;
    USE SIGNAL ;
    PORT
      LAYER M5 ;
        RECT  52.752 17.196 52.776 17.28 ;
    END
  END o_x1[199]
  PIN o_x1[19]
    DIRECTION OUTPUT ;
    USE SIGNAL ;
    PORT
      LAYER M5 ;
        RECT  36.048 17.196 36.072 17.28 ;
    END
  END o_x1[19]
  PIN o_x1[1]
    DIRECTION OUTPUT ;
    USE SIGNAL ;
    PORT
      LAYER M5 ;
        RECT  34.368 17.196 34.392 17.28 ;
    END
  END o_x1[1]
  PIN o_x1[200]
    DIRECTION OUTPUT ;
    USE SIGNAL ;
    PORT
      LAYER M3 ;
        RECT  52.848 17.242 52.866 17.28 ;
    END
  END o_x1[200]
  PIN o_x1[201]
    DIRECTION OUTPUT ;
    USE SIGNAL ;
    PORT
      LAYER M5 ;
        RECT  52.944 17.196 52.968 17.28 ;
    END
  END o_x1[201]
  PIN o_x1[202]
    DIRECTION OUTPUT ;
    USE SIGNAL ;
    PORT
      LAYER M3 ;
        RECT  53.028 17.242 53.046 17.28 ;
    END
  END o_x1[202]
  PIN o_x1[203]
    DIRECTION OUTPUT ;
    USE SIGNAL ;
    PORT
      LAYER M5 ;
        RECT  53.136 17.196 53.16 17.28 ;
    END
  END o_x1[203]
  PIN o_x1[204]
    DIRECTION OUTPUT ;
    USE SIGNAL ;
    PORT
      LAYER M3 ;
        RECT  53.244 17.242 53.262 17.28 ;
    END
  END o_x1[204]
  PIN o_x1[205]
    DIRECTION OUTPUT ;
    USE SIGNAL ;
    PORT
      LAYER M5 ;
        RECT  53.328 17.196 53.352 17.28 ;
    END
  END o_x1[205]
  PIN o_x1[206]
    DIRECTION OUTPUT ;
    USE SIGNAL ;
    PORT
      LAYER M3 ;
        RECT  53.424 17.242 53.442 17.28 ;
    END
  END o_x1[206]
  PIN o_x1[207]
    DIRECTION OUTPUT ;
    USE SIGNAL ;
    PORT
      LAYER M5 ;
        RECT  53.52 17.196 53.544 17.28 ;
    END
  END o_x1[207]
  PIN o_x1[208]
    DIRECTION OUTPUT ;
    USE SIGNAL ;
    PORT
      LAYER M3 ;
        RECT  53.604 17.242 53.622 17.28 ;
    END
  END o_x1[208]
  PIN o_x1[209]
    DIRECTION OUTPUT ;
    USE SIGNAL ;
    PORT
      LAYER M5 ;
        RECT  53.712 17.196 53.736 17.28 ;
    END
  END o_x1[209]
  PIN o_x1[20]
    DIRECTION OUTPUT ;
    USE SIGNAL ;
    PORT
      LAYER M3 ;
        RECT  36.144 17.242 36.162 17.28 ;
    END
  END o_x1[20]
  PIN o_x1[210]
    DIRECTION OUTPUT ;
    USE SIGNAL ;
    PORT
      LAYER M3 ;
        RECT  53.82 17.242 53.838 17.28 ;
    END
  END o_x1[210]
  PIN o_x1[211]
    DIRECTION OUTPUT ;
    USE SIGNAL ;
    PORT
      LAYER M5 ;
        RECT  53.904 17.196 53.928 17.28 ;
    END
  END o_x1[211]
  PIN o_x1[212]
    DIRECTION OUTPUT ;
    USE SIGNAL ;
    PORT
      LAYER M3 ;
        RECT  54 17.242 54.018 17.28 ;
    END
  END o_x1[212]
  PIN o_x1[213]
    DIRECTION OUTPUT ;
    USE SIGNAL ;
    PORT
      LAYER M5 ;
        RECT  54.096 17.196 54.12 17.28 ;
    END
  END o_x1[213]
  PIN o_x1[214]
    DIRECTION OUTPUT ;
    USE SIGNAL ;
    PORT
      LAYER M3 ;
        RECT  54.18 17.242 54.198 17.28 ;
    END
  END o_x1[214]
  PIN o_x1[215]
    DIRECTION OUTPUT ;
    USE SIGNAL ;
    PORT
      LAYER M5 ;
        RECT  54.24 17.196 54.264 17.28 ;
    END
  END o_x1[215]
  PIN o_x1[216]
    DIRECTION OUTPUT ;
    USE SIGNAL ;
    PORT
      LAYER M3 ;
        RECT  54.324 17.242 54.342 17.28 ;
    END
  END o_x1[216]
  PIN o_x1[217]
    DIRECTION OUTPUT ;
    USE SIGNAL ;
    PORT
      LAYER M5 ;
        RECT  54.432 17.196 54.456 17.28 ;
    END
  END o_x1[217]
  PIN o_x1[218]
    DIRECTION OUTPUT ;
    USE SIGNAL ;
    PORT
      LAYER M3 ;
        RECT  54.54 17.242 54.558 17.28 ;
    END
  END o_x1[218]
  PIN o_x1[219]
    DIRECTION OUTPUT ;
    USE SIGNAL ;
    PORT
      LAYER M5 ;
        RECT  54.624 17.196 54.648 17.28 ;
    END
  END o_x1[219]
  PIN o_x1[21]
    DIRECTION OUTPUT ;
    USE SIGNAL ;
    PORT
      LAYER M5 ;
        RECT  36.24 17.196 36.264 17.28 ;
    END
  END o_x1[21]
  PIN o_x1[220]
    DIRECTION OUTPUT ;
    USE SIGNAL ;
    PORT
      LAYER M3 ;
        RECT  54.72 17.242 54.738 17.28 ;
    END
  END o_x1[220]
  PIN o_x1[221]
    DIRECTION OUTPUT ;
    USE SIGNAL ;
    PORT
      LAYER M5 ;
        RECT  54.816 17.196 54.84 17.28 ;
    END
  END o_x1[221]
  PIN o_x1[222]
    DIRECTION OUTPUT ;
    USE SIGNAL ;
    PORT
      LAYER M3 ;
        RECT  54.9 17.242 54.918 17.28 ;
    END
  END o_x1[222]
  PIN o_x1[223]
    DIRECTION OUTPUT ;
    USE SIGNAL ;
    PORT
      LAYER M5 ;
        RECT  55.008 17.196 55.032 17.28 ;
    END
  END o_x1[223]
  PIN o_x1[224]
    DIRECTION OUTPUT ;
    USE SIGNAL ;
    PORT
      LAYER M3 ;
        RECT  55.116 17.242 55.134 17.28 ;
    END
  END o_x1[224]
  PIN o_x1[225]
    DIRECTION OUTPUT ;
    USE SIGNAL ;
    PORT
      LAYER M5 ;
        RECT  55.2 17.196 55.224 17.28 ;
    END
  END o_x1[225]
  PIN o_x1[226]
    DIRECTION OUTPUT ;
    USE SIGNAL ;
    PORT
      LAYER M3 ;
        RECT  55.296 17.242 55.314 17.28 ;
    END
  END o_x1[226]
  PIN o_x1[227]
    DIRECTION OUTPUT ;
    USE SIGNAL ;
    PORT
      LAYER M5 ;
        RECT  55.392 17.196 55.416 17.28 ;
    END
  END o_x1[227]
  PIN o_x1[228]
    DIRECTION OUTPUT ;
    USE SIGNAL ;
    PORT
      LAYER M3 ;
        RECT  55.476 17.242 55.494 17.28 ;
    END
  END o_x1[228]
  PIN o_x1[229]
    DIRECTION OUTPUT ;
    USE SIGNAL ;
    PORT
      LAYER M5 ;
        RECT  55.584 17.196 55.608 17.28 ;
    END
  END o_x1[229]
  PIN o_x1[22]
    DIRECTION OUTPUT ;
    USE SIGNAL ;
    PORT
      LAYER M3 ;
        RECT  36.324 17.242 36.342 17.28 ;
    END
  END o_x1[22]
  PIN o_x1[230]
    DIRECTION OUTPUT ;
    USE SIGNAL ;
    PORT
      LAYER M3 ;
        RECT  55.692 17.242 55.71 17.28 ;
    END
  END o_x1[230]
  PIN o_x1[231]
    DIRECTION OUTPUT ;
    USE SIGNAL ;
    PORT
      LAYER M5 ;
        RECT  55.728 17.196 55.752 17.28 ;
    END
  END o_x1[231]
  PIN o_x1[232]
    DIRECTION OUTPUT ;
    USE SIGNAL ;
    PORT
      LAYER M3 ;
        RECT  55.836 17.242 55.854 17.28 ;
    END
  END o_x1[232]
  PIN o_x1[233]
    DIRECTION OUTPUT ;
    USE SIGNAL ;
    PORT
      LAYER M5 ;
        RECT  55.92 17.196 55.944 17.28 ;
    END
  END o_x1[233]
  PIN o_x1[234]
    DIRECTION OUTPUT ;
    USE SIGNAL ;
    PORT
      LAYER M3 ;
        RECT  56.016 17.242 56.034 17.28 ;
    END
  END o_x1[234]
  PIN o_x1[235]
    DIRECTION OUTPUT ;
    USE SIGNAL ;
    PORT
      LAYER M5 ;
        RECT  56.112 17.196 56.136 17.28 ;
    END
  END o_x1[235]
  PIN o_x1[236]
    DIRECTION OUTPUT ;
    USE SIGNAL ;
    PORT
      LAYER M3 ;
        RECT  56.196 17.242 56.214 17.28 ;
    END
  END o_x1[236]
  PIN o_x1[237]
    DIRECTION OUTPUT ;
    USE SIGNAL ;
    PORT
      LAYER M5 ;
        RECT  56.304 17.196 56.328 17.28 ;
    END
  END o_x1[237]
  PIN o_x1[238]
    DIRECTION OUTPUT ;
    USE SIGNAL ;
    PORT
      LAYER M3 ;
        RECT  56.412 17.242 56.43 17.28 ;
    END
  END o_x1[238]
  PIN o_x1[239]
    DIRECTION OUTPUT ;
    USE SIGNAL ;
    PORT
      LAYER M5 ;
        RECT  56.496 17.196 56.52 17.28 ;
    END
  END o_x1[239]
  PIN o_x1[23]
    DIRECTION OUTPUT ;
    USE SIGNAL ;
    PORT
      LAYER M5 ;
        RECT  36.432 17.196 36.456 17.28 ;
    END
  END o_x1[23]
  PIN o_x1[240]
    DIRECTION OUTPUT ;
    USE SIGNAL ;
    PORT
      LAYER M3 ;
        RECT  56.592 17.242 56.61 17.28 ;
    END
  END o_x1[240]
  PIN o_x1[241]
    DIRECTION OUTPUT ;
    USE SIGNAL ;
    PORT
      LAYER M5 ;
        RECT  56.688 17.196 56.712 17.28 ;
    END
  END o_x1[241]
  PIN o_x1[242]
    DIRECTION OUTPUT ;
    USE SIGNAL ;
    PORT
      LAYER M3 ;
        RECT  56.772 17.242 56.79 17.28 ;
    END
  END o_x1[242]
  PIN o_x1[243]
    DIRECTION OUTPUT ;
    USE SIGNAL ;
    PORT
      LAYER M5 ;
        RECT  56.88 17.196 56.904 17.28 ;
    END
  END o_x1[243]
  PIN o_x1[244]
    DIRECTION OUTPUT ;
    USE SIGNAL ;
    PORT
      LAYER M3 ;
        RECT  56.988 17.242 57.006 17.28 ;
    END
  END o_x1[244]
  PIN o_x1[245]
    DIRECTION OUTPUT ;
    USE SIGNAL ;
    PORT
      LAYER M5 ;
        RECT  57.072 17.196 57.096 17.28 ;
    END
  END o_x1[245]
  PIN o_x1[246]
    DIRECTION OUTPUT ;
    USE SIGNAL ;
    PORT
      LAYER M3 ;
        RECT  57.168 17.242 57.186 17.28 ;
    END
  END o_x1[246]
  PIN o_x1[247]
    DIRECTION OUTPUT ;
    USE SIGNAL ;
    PORT
      LAYER M5 ;
        RECT  57.216 17.196 57.24 17.28 ;
    END
  END o_x1[247]
  PIN o_x1[248]
    DIRECTION OUTPUT ;
    USE SIGNAL ;
    PORT
      LAYER M3 ;
        RECT  57.312 17.242 57.33 17.28 ;
    END
  END o_x1[248]
  PIN o_x1[249]
    DIRECTION OUTPUT ;
    USE SIGNAL ;
    PORT
      LAYER M5 ;
        RECT  57.408 17.196 57.432 17.28 ;
    END
  END o_x1[249]
  PIN o_x1[24]
    DIRECTION OUTPUT ;
    USE SIGNAL ;
    PORT
      LAYER M3 ;
        RECT  36.54 17.242 36.558 17.28 ;
    END
  END o_x1[24]
  PIN o_x1[250]
    DIRECTION OUTPUT ;
    USE SIGNAL ;
    PORT
      LAYER M3 ;
        RECT  57.492 17.242 57.51 17.28 ;
    END
  END o_x1[250]
  PIN o_x1[251]
    DIRECTION OUTPUT ;
    USE SIGNAL ;
    PORT
      LAYER M5 ;
        RECT  57.6 17.196 57.624 17.28 ;
    END
  END o_x1[251]
  PIN o_x1[252]
    DIRECTION OUTPUT ;
    USE SIGNAL ;
    PORT
      LAYER M3 ;
        RECT  57.708 17.242 57.726 17.28 ;
    END
  END o_x1[252]
  PIN o_x1[253]
    DIRECTION OUTPUT ;
    USE SIGNAL ;
    PORT
      LAYER M5 ;
        RECT  57.792 17.196 57.816 17.28 ;
    END
  END o_x1[253]
  PIN o_x1[254]
    DIRECTION OUTPUT ;
    USE SIGNAL ;
    PORT
      LAYER M3 ;
        RECT  57.888 17.242 57.906 17.28 ;
    END
  END o_x1[254]
  PIN o_x1[255]
    DIRECTION OUTPUT ;
    USE SIGNAL ;
    PORT
      LAYER M5 ;
        RECT  57.984 17.196 58.008 17.28 ;
    END
  END o_x1[255]
  PIN o_x1[256]
    DIRECTION OUTPUT ;
    USE SIGNAL ;
    PORT
      LAYER M5 ;
        RECT  8.496 17.196 8.52 17.28 ;
    END
  END o_x1[256]
  PIN o_x1[257]
    DIRECTION OUTPUT ;
    USE SIGNAL ;
    PORT
      LAYER M3 ;
        RECT  8.604 17.242 8.622 17.28 ;
    END
  END o_x1[257]
  PIN o_x1[258]
    DIRECTION OUTPUT ;
    USE SIGNAL ;
    PORT
      LAYER M5 ;
        RECT  8.688 17.196 8.712 17.28 ;
    END
  END o_x1[258]
  PIN o_x1[259]
    DIRECTION OUTPUT ;
    USE SIGNAL ;
    PORT
      LAYER M3 ;
        RECT  8.784 17.242 8.802 17.28 ;
    END
  END o_x1[259]
  PIN o_x1[25]
    DIRECTION OUTPUT ;
    USE SIGNAL ;
    PORT
      LAYER M5 ;
        RECT  36.576 17.196 36.6 17.28 ;
    END
  END o_x1[25]
  PIN o_x1[260]
    DIRECTION OUTPUT ;
    USE SIGNAL ;
    PORT
      LAYER M5 ;
        RECT  8.88 17.196 8.904 17.28 ;
    END
  END o_x1[260]
  PIN o_x1[261]
    DIRECTION OUTPUT ;
    USE SIGNAL ;
    PORT
      LAYER M3 ;
        RECT  8.964 17.242 8.982 17.28 ;
    END
  END o_x1[261]
  PIN o_x1[262]
    DIRECTION OUTPUT ;
    USE SIGNAL ;
    PORT
      LAYER M5 ;
        RECT  9.072 17.196 9.096 17.28 ;
    END
  END o_x1[262]
  PIN o_x1[263]
    DIRECTION OUTPUT ;
    USE SIGNAL ;
    PORT
      LAYER M3 ;
        RECT  9.18 17.242 9.198 17.28 ;
    END
  END o_x1[263]
  PIN o_x1[264]
    DIRECTION OUTPUT ;
    USE SIGNAL ;
    PORT
      LAYER M5 ;
        RECT  9.264 17.196 9.288 17.28 ;
    END
  END o_x1[264]
  PIN o_x1[265]
    DIRECTION OUTPUT ;
    USE SIGNAL ;
    PORT
      LAYER M3 ;
        RECT  9.36 17.242 9.378 17.28 ;
    END
  END o_x1[265]
  PIN o_x1[26]
    DIRECTION OUTPUT ;
    USE SIGNAL ;
    PORT
      LAYER M3 ;
        RECT  36.684 17.242 36.702 17.28 ;
    END
  END o_x1[26]
  PIN o_x1[27]
    DIRECTION OUTPUT ;
    USE SIGNAL ;
    PORT
      LAYER M5 ;
        RECT  36.768 17.196 36.792 17.28 ;
    END
  END o_x1[27]
  PIN o_x1[28]
    DIRECTION OUTPUT ;
    USE SIGNAL ;
    PORT
      LAYER M3 ;
        RECT  36.864 17.242 36.882 17.28 ;
    END
  END o_x1[28]
  PIN o_x1[29]
    DIRECTION OUTPUT ;
    USE SIGNAL ;
    PORT
      LAYER M5 ;
        RECT  36.96 17.196 36.984 17.28 ;
    END
  END o_x1[29]
  PIN o_x1[2]
    DIRECTION OUTPUT ;
    USE SIGNAL ;
    PORT
      LAYER M3 ;
        RECT  34.452 17.242 34.47 17.28 ;
    END
  END o_x1[2]
  PIN o_x1[30]
    DIRECTION OUTPUT ;
    USE SIGNAL ;
    PORT
      LAYER M3 ;
        RECT  37.044 17.242 37.062 17.28 ;
    END
  END o_x1[30]
  PIN o_x1[31]
    DIRECTION OUTPUT ;
    USE SIGNAL ;
    PORT
      LAYER M5 ;
        RECT  37.152 17.196 37.176 17.28 ;
    END
  END o_x1[31]
  PIN o_x1[32]
    DIRECTION OUTPUT ;
    USE SIGNAL ;
    PORT
      LAYER M3 ;
        RECT  37.26 17.242 37.278 17.28 ;
    END
  END o_x1[32]
  PIN o_x1[33]
    DIRECTION OUTPUT ;
    USE SIGNAL ;
    PORT
      LAYER M5 ;
        RECT  37.344 17.196 37.368 17.28 ;
    END
  END o_x1[33]
  PIN o_x1[34]
    DIRECTION OUTPUT ;
    USE SIGNAL ;
    PORT
      LAYER M3 ;
        RECT  37.44 17.242 37.458 17.28 ;
    END
  END o_x1[34]
  PIN o_x1[35]
    DIRECTION OUTPUT ;
    USE SIGNAL ;
    PORT
      LAYER M5 ;
        RECT  37.536 17.196 37.56 17.28 ;
    END
  END o_x1[35]
  PIN o_x1[36]
    DIRECTION OUTPUT ;
    USE SIGNAL ;
    PORT
      LAYER M3 ;
        RECT  37.62 17.242 37.638 17.28 ;
    END
  END o_x1[36]
  PIN o_x1[37]
    DIRECTION OUTPUT ;
    USE SIGNAL ;
    PORT
      LAYER M5 ;
        RECT  37.728 17.196 37.752 17.28 ;
    END
  END o_x1[37]
  PIN o_x1[38]
    DIRECTION OUTPUT ;
    USE SIGNAL ;
    PORT
      LAYER M3 ;
        RECT  37.836 17.242 37.854 17.28 ;
    END
  END o_x1[38]
  PIN o_x1[39]
    DIRECTION OUTPUT ;
    USE SIGNAL ;
    PORT
      LAYER M5 ;
        RECT  37.92 17.196 37.944 17.28 ;
    END
  END o_x1[39]
  PIN o_x1[3]
    DIRECTION OUTPUT ;
    USE SIGNAL ;
    PORT
      LAYER M5 ;
        RECT  34.56 17.196 34.584 17.28 ;
    END
  END o_x1[3]
  PIN o_x1[40]
    DIRECTION OUTPUT ;
    USE SIGNAL ;
    PORT
      LAYER M3 ;
        RECT  37.98 17.242 37.998 17.28 ;
    END
  END o_x1[40]
  PIN o_x1[41]
    DIRECTION OUTPUT ;
    USE SIGNAL ;
    PORT
      LAYER M5 ;
        RECT  38.064 17.196 38.088 17.28 ;
    END
  END o_x1[41]
  PIN o_x1[42]
    DIRECTION OUTPUT ;
    USE SIGNAL ;
    PORT
      LAYER M3 ;
        RECT  38.16 17.242 38.178 17.28 ;
    END
  END o_x1[42]
  PIN o_x1[43]
    DIRECTION OUTPUT ;
    USE SIGNAL ;
    PORT
      LAYER M5 ;
        RECT  38.256 17.196 38.28 17.28 ;
    END
  END o_x1[43]
  PIN o_x1[44]
    DIRECTION OUTPUT ;
    USE SIGNAL ;
    PORT
      LAYER M3 ;
        RECT  38.34 17.242 38.358 17.28 ;
    END
  END o_x1[44]
  PIN o_x1[45]
    DIRECTION OUTPUT ;
    USE SIGNAL ;
    PORT
      LAYER M5 ;
        RECT  38.448 17.196 38.472 17.28 ;
    END
  END o_x1[45]
  PIN o_x1[46]
    DIRECTION OUTPUT ;
    USE SIGNAL ;
    PORT
      LAYER M3 ;
        RECT  38.556 17.242 38.574 17.28 ;
    END
  END o_x1[46]
  PIN o_x1[47]
    DIRECTION OUTPUT ;
    USE SIGNAL ;
    PORT
      LAYER M5 ;
        RECT  38.64 17.196 38.664 17.28 ;
    END
  END o_x1[47]
  PIN o_x1[48]
    DIRECTION OUTPUT ;
    USE SIGNAL ;
    PORT
      LAYER M3 ;
        RECT  38.736 17.242 38.754 17.28 ;
    END
  END o_x1[48]
  PIN o_x1[49]
    DIRECTION OUTPUT ;
    USE SIGNAL ;
    PORT
      LAYER M5 ;
        RECT  38.832 17.196 38.856 17.28 ;
    END
  END o_x1[49]
  PIN o_x1[4]
    DIRECTION OUTPUT ;
    USE SIGNAL ;
    PORT
      LAYER M3 ;
        RECT  34.668 17.242 34.686 17.28 ;
    END
  END o_x1[4]
  PIN o_x1[50]
    DIRECTION OUTPUT ;
    USE SIGNAL ;
    PORT
      LAYER M3 ;
        RECT  38.916 17.242 38.934 17.28 ;
    END
  END o_x1[50]
  PIN o_x1[51]
    DIRECTION OUTPUT ;
    USE SIGNAL ;
    PORT
      LAYER M5 ;
        RECT  39.024 17.196 39.048 17.28 ;
    END
  END o_x1[51]
  PIN o_x1[52]
    DIRECTION OUTPUT ;
    USE SIGNAL ;
    PORT
      LAYER M3 ;
        RECT  39.132 17.242 39.15 17.28 ;
    END
  END o_x1[52]
  PIN o_x1[53]
    DIRECTION OUTPUT ;
    USE SIGNAL ;
    PORT
      LAYER M5 ;
        RECT  39.216 17.196 39.24 17.28 ;
    END
  END o_x1[53]
  PIN o_x1[54]
    DIRECTION OUTPUT ;
    USE SIGNAL ;
    PORT
      LAYER M3 ;
        RECT  39.312 17.242 39.33 17.28 ;
    END
  END o_x1[54]
  PIN o_x1[55]
    DIRECTION OUTPUT ;
    USE SIGNAL ;
    PORT
      LAYER M5 ;
        RECT  39.408 17.196 39.432 17.28 ;
    END
  END o_x1[55]
  PIN o_x1[56]
    DIRECTION OUTPUT ;
    USE SIGNAL ;
    PORT
      LAYER M3 ;
        RECT  39.456 17.242 39.474 17.28 ;
    END
  END o_x1[56]
  PIN o_x1[57]
    DIRECTION OUTPUT ;
    USE SIGNAL ;
    PORT
      LAYER M5 ;
        RECT  39.552 17.196 39.576 17.28 ;
    END
  END o_x1[57]
  PIN o_x1[58]
    DIRECTION OUTPUT ;
    USE SIGNAL ;
    PORT
      LAYER M3 ;
        RECT  39.636 17.242 39.654 17.28 ;
    END
  END o_x1[58]
  PIN o_x1[59]
    DIRECTION OUTPUT ;
    USE SIGNAL ;
    PORT
      LAYER M5 ;
        RECT  39.744 17.196 39.768 17.28 ;
    END
  END o_x1[59]
  PIN o_x1[5]
    DIRECTION OUTPUT ;
    USE SIGNAL ;
    PORT
      LAYER M5 ;
        RECT  34.752 17.196 34.776 17.28 ;
    END
  END o_x1[5]
  PIN o_x1[60]
    DIRECTION OUTPUT ;
    USE SIGNAL ;
    PORT
      LAYER M3 ;
        RECT  39.852 17.242 39.87 17.28 ;
    END
  END o_x1[60]
  PIN o_x1[61]
    DIRECTION OUTPUT ;
    USE SIGNAL ;
    PORT
      LAYER M5 ;
        RECT  39.936 17.196 39.96 17.28 ;
    END
  END o_x1[61]
  PIN o_x1[62]
    DIRECTION OUTPUT ;
    USE SIGNAL ;
    PORT
      LAYER M3 ;
        RECT  40.032 17.242 40.05 17.28 ;
    END
  END o_x1[62]
  PIN o_x1[63]
    DIRECTION OUTPUT ;
    USE SIGNAL ;
    PORT
      LAYER M5 ;
        RECT  40.128 17.196 40.152 17.28 ;
    END
  END o_x1[63]
  PIN o_x1[64]
    DIRECTION OUTPUT ;
    USE SIGNAL ;
    PORT
      LAYER M3 ;
        RECT  40.212 17.242 40.23 17.28 ;
    END
  END o_x1[64]
  PIN o_x1[65]
    DIRECTION OUTPUT ;
    USE SIGNAL ;
    PORT
      LAYER M5 ;
        RECT  40.32 17.196 40.344 17.28 ;
    END
  END o_x1[65]
  PIN o_x1[66]
    DIRECTION OUTPUT ;
    USE SIGNAL ;
    PORT
      LAYER M3 ;
        RECT  40.428 17.242 40.446 17.28 ;
    END
  END o_x1[66]
  PIN o_x1[67]
    DIRECTION OUTPUT ;
    USE SIGNAL ;
    PORT
      LAYER M5 ;
        RECT  40.512 17.196 40.536 17.28 ;
    END
  END o_x1[67]
  PIN o_x1[68]
    DIRECTION OUTPUT ;
    USE SIGNAL ;
    PORT
      LAYER M3 ;
        RECT  40.608 17.242 40.626 17.28 ;
    END
  END o_x1[68]
  PIN o_x1[69]
    DIRECTION OUTPUT ;
    USE SIGNAL ;
    PORT
      LAYER M5 ;
        RECT  40.704 17.196 40.728 17.28 ;
    END
  END o_x1[69]
  PIN o_x1[6]
    DIRECTION OUTPUT ;
    USE SIGNAL ;
    PORT
      LAYER M3 ;
        RECT  34.848 17.242 34.866 17.28 ;
    END
  END o_x1[6]
  PIN o_x1[70]
    DIRECTION OUTPUT ;
    USE SIGNAL ;
    PORT
      LAYER M3 ;
        RECT  40.788 17.242 40.806 17.28 ;
    END
  END o_x1[70]
  PIN o_x1[71]
    DIRECTION OUTPUT ;
    USE SIGNAL ;
    PORT
      LAYER M5 ;
        RECT  40.896 17.196 40.92 17.28 ;
    END
  END o_x1[71]
  PIN o_x1[72]
    DIRECTION OUTPUT ;
    USE SIGNAL ;
    PORT
      LAYER M3 ;
        RECT  40.932 17.242 40.95 17.28 ;
    END
  END o_x1[72]
  PIN o_x1[73]
    DIRECTION OUTPUT ;
    USE SIGNAL ;
    PORT
      LAYER M5 ;
        RECT  41.04 17.196 41.064 17.28 ;
    END
  END o_x1[73]
  PIN o_x1[74]
    DIRECTION OUTPUT ;
    USE SIGNAL ;
    PORT
      LAYER M3 ;
        RECT  41.148 17.242 41.166 17.28 ;
    END
  END o_x1[74]
  PIN o_x1[75]
    DIRECTION OUTPUT ;
    USE SIGNAL ;
    PORT
      LAYER M5 ;
        RECT  41.232 17.196 41.256 17.28 ;
    END
  END o_x1[75]
  PIN o_x1[76]
    DIRECTION OUTPUT ;
    USE SIGNAL ;
    PORT
      LAYER M3 ;
        RECT  41.328 17.242 41.346 17.28 ;
    END
  END o_x1[76]
  PIN o_x1[77]
    DIRECTION OUTPUT ;
    USE SIGNAL ;
    PORT
      LAYER M5 ;
        RECT  41.424 17.196 41.448 17.28 ;
    END
  END o_x1[77]
  PIN o_x1[78]
    DIRECTION OUTPUT ;
    USE SIGNAL ;
    PORT
      LAYER M3 ;
        RECT  41.508 17.242 41.526 17.28 ;
    END
  END o_x1[78]
  PIN o_x1[79]
    DIRECTION OUTPUT ;
    USE SIGNAL ;
    PORT
      LAYER M5 ;
        RECT  41.616 17.196 41.64 17.28 ;
    END
  END o_x1[79]
  PIN o_x1[7]
    DIRECTION OUTPUT ;
    USE SIGNAL ;
    PORT
      LAYER M5 ;
        RECT  34.944 17.196 34.968 17.28 ;
    END
  END o_x1[7]
  PIN o_x1[80]
    DIRECTION OUTPUT ;
    USE SIGNAL ;
    PORT
      LAYER M3 ;
        RECT  41.724 17.242 41.742 17.28 ;
    END
  END o_x1[80]
  PIN o_x1[81]
    DIRECTION OUTPUT ;
    USE SIGNAL ;
    PORT
      LAYER M5 ;
        RECT  41.808 17.196 41.832 17.28 ;
    END
  END o_x1[81]
  PIN o_x1[82]
    DIRECTION OUTPUT ;
    USE SIGNAL ;
    PORT
      LAYER M3 ;
        RECT  41.904 17.242 41.922 17.28 ;
    END
  END o_x1[82]
  PIN o_x1[83]
    DIRECTION OUTPUT ;
    USE SIGNAL ;
    PORT
      LAYER M5 ;
        RECT  42 17.196 42.024 17.28 ;
    END
  END o_x1[83]
  PIN o_x1[84]
    DIRECTION OUTPUT ;
    USE SIGNAL ;
    PORT
      LAYER M3 ;
        RECT  42.084 17.242 42.102 17.28 ;
    END
  END o_x1[84]
  PIN o_x1[85]
    DIRECTION OUTPUT ;
    USE SIGNAL ;
    PORT
      LAYER M5 ;
        RECT  42.192 17.196 42.216 17.28 ;
    END
  END o_x1[85]
  PIN o_x1[86]
    DIRECTION OUTPUT ;
    USE SIGNAL ;
    PORT
      LAYER M3 ;
        RECT  42.3 17.242 42.318 17.28 ;
    END
  END o_x1[86]
  PIN o_x1[87]
    DIRECTION OUTPUT ;
    USE SIGNAL ;
    PORT
      LAYER M5 ;
        RECT  42.384 17.196 42.408 17.28 ;
    END
  END o_x1[87]
  PIN o_x1[88]
    DIRECTION OUTPUT ;
    USE SIGNAL ;
    PORT
      LAYER M3 ;
        RECT  42.444 17.242 42.462 17.28 ;
    END
  END o_x1[88]
  PIN o_x1[89]
    DIRECTION OUTPUT ;
    USE SIGNAL ;
    PORT
      LAYER M5 ;
        RECT  42.528 17.196 42.552 17.28 ;
    END
  END o_x1[89]
  PIN o_x1[8]
    DIRECTION OUTPUT ;
    USE SIGNAL ;
    PORT
      LAYER M3 ;
        RECT  35.028 17.242 35.046 17.28 ;
    END
  END o_x1[8]
  PIN o_x1[90]
    DIRECTION OUTPUT ;
    USE SIGNAL ;
    PORT
      LAYER M3 ;
        RECT  42.624 17.242 42.642 17.28 ;
    END
  END o_x1[90]
  PIN o_x1[91]
    DIRECTION OUTPUT ;
    USE SIGNAL ;
    PORT
      LAYER M5 ;
        RECT  42.72 17.196 42.744 17.28 ;
    END
  END o_x1[91]
  PIN o_x1[92]
    DIRECTION OUTPUT ;
    USE SIGNAL ;
    PORT
      LAYER M3 ;
        RECT  42.804 17.242 42.822 17.28 ;
    END
  END o_x1[92]
  PIN o_x1[93]
    DIRECTION OUTPUT ;
    USE SIGNAL ;
    PORT
      LAYER M5 ;
        RECT  42.912 17.196 42.936 17.28 ;
    END
  END o_x1[93]
  PIN o_x1[94]
    DIRECTION OUTPUT ;
    USE SIGNAL ;
    PORT
      LAYER M3 ;
        RECT  43.02 17.242 43.038 17.28 ;
    END
  END o_x1[94]
  PIN o_x1[95]
    DIRECTION OUTPUT ;
    USE SIGNAL ;
    PORT
      LAYER M5 ;
        RECT  43.104 17.196 43.128 17.28 ;
    END
  END o_x1[95]
  PIN o_x1[96]
    DIRECTION OUTPUT ;
    USE SIGNAL ;
    PORT
      LAYER M3 ;
        RECT  43.2 17.242 43.218 17.28 ;
    END
  END o_x1[96]
  PIN o_x1[97]
    DIRECTION OUTPUT ;
    USE SIGNAL ;
    PORT
      LAYER M5 ;
        RECT  43.296 17.196 43.32 17.28 ;
    END
  END o_x1[97]
  PIN o_x1[98]
    DIRECTION OUTPUT ;
    USE SIGNAL ;
    PORT
      LAYER M3 ;
        RECT  43.38 17.242 43.398 17.28 ;
    END
  END o_x1[98]
  PIN o_x1[99]
    DIRECTION OUTPUT ;
    USE SIGNAL ;
    PORT
      LAYER M5 ;
        RECT  43.488 17.196 43.512 17.28 ;
    END
  END o_x1[99]
  PIN o_x1[9]
    DIRECTION OUTPUT ;
    USE SIGNAL ;
    PORT
      LAYER M5 ;
        RECT  35.088 17.196 35.112 17.28 ;
    END
  END o_x1[9]
  PIN rs[0]
    DIRECTION INPUT ;
    USE SIGNAL ;
    PORT
      LAYER M4 ;
        RECT  0 8.736 0.084 8.76 ;
    END
  END rs[0]
  PIN VDD
    DIRECTION INOUT ;
    USE POWER ;
    PORT
      LAYER M5 ;
        RECT  56.592 2.151 56.712 15.129 ;
        RECT  53.892 2.151 54.012 15.129 ;
        RECT  51.192 2.151 51.312 15.129 ;
        RECT  48.492 2.151 48.612 15.129 ;
        RECT  45.792 2.151 45.912 15.129 ;
        RECT  43.092 2.151 43.212 15.129 ;
        RECT  40.392 2.151 40.512 15.129 ;
        RECT  37.692 2.151 37.812 15.129 ;
        RECT  34.992 2.151 35.112 15.129 ;
        RECT  32.292 2.151 32.412 15.129 ;
        RECT  29.592 2.151 29.712 15.129 ;
        RECT  26.892 2.151 27.012 15.129 ;
        RECT  24.192 2.151 24.312 15.129 ;
        RECT  21.492 2.151 21.612 15.129 ;
        RECT  18.792 2.151 18.912 15.129 ;
        RECT  16.092 2.151 16.212 15.129 ;
        RECT  13.392 2.151 13.512 15.129 ;
        RECT  10.692 2.151 10.812 15.129 ;
        RECT  7.992 2.151 8.112 15.129 ;
        RECT  5.292 2.151 5.412 15.129 ;
        RECT  2.592 2.151 2.712 15.129 ;
    END
  END VDD
  PIN VSS
    DIRECTION INOUT ;
    USE GROUND ;
    PORT
      LAYER M5 ;
        RECT  56.4 2.137 56.52 15.143 ;
        RECT  53.7 2.137 53.82 15.143 ;
        RECT  51 2.137 51.12 15.143 ;
        RECT  48.3 2.137 48.42 15.143 ;
        RECT  45.6 2.137 45.72 15.143 ;
        RECT  42.9 2.137 43.02 15.143 ;
        RECT  40.2 2.137 40.32 15.143 ;
        RECT  37.5 2.137 37.62 15.143 ;
        RECT  34.8 2.137 34.92 15.143 ;
        RECT  32.1 2.137 32.22 15.143 ;
        RECT  29.4 2.137 29.52 15.143 ;
        RECT  26.7 2.137 26.82 15.143 ;
        RECT  24 2.137 24.12 15.143 ;
        RECT  21.3 2.137 21.42 15.143 ;
        RECT  18.6 2.137 18.72 15.143 ;
        RECT  15.9 2.137 16.02 15.143 ;
        RECT  13.2 2.137 13.32 15.143 ;
        RECT  10.5 2.137 10.62 15.143 ;
        RECT  7.8 2.137 7.92 15.143 ;
        RECT  5.1 2.137 5.22 15.143 ;
        RECT  2.4 2.137 2.52 15.143 ;
    END
  END VSS
  # OT_OBS_CLOSED layer=M5 d_um=1.536 added=4
  OBS
    LAYER RVTN ;
     RECT  2.16 2.16 58.32 2.295 ;
     RECT  2.16 2.565 58.32 2.835 ;
     RECT  2.16 3.105 58.32 3.375 ;
     RECT  2.16 3.645 58.32 3.915 ;
     RECT  2.16 4.185 58.32 4.455 ;
     RECT  2.16 4.725 58.32 4.995 ;
     RECT  2.16 5.265 58.32 5.535 ;
     RECT  2.16 5.805 58.32 6.075 ;
     RECT  2.16 6.345 58.32 6.615 ;
     RECT  2.16 6.885 58.32 7.155 ;
     RECT  2.16 7.425 58.32 7.695 ;
     RECT  2.16 7.965 58.32 8.235 ;
     RECT  2.16 8.505 58.32 8.775 ;
     RECT  2.16 9.045 58.32 9.315 ;
     RECT  2.16 9.585 58.32 9.855 ;
     RECT  2.16 10.125 58.32 10.395 ;
     RECT  2.16 10.665 58.32 10.935 ;
     RECT  2.16 11.205 58.32 11.475 ;
     RECT  2.16 11.745 58.32 12.015 ;
     RECT  2.16 12.285 58.32 12.555 ;
     RECT  2.16 12.825 58.32 13.095 ;
     RECT  2.16 13.365 58.32 13.635 ;
     RECT  2.16 13.905 58.32 14.175 ;
     RECT  2.16 14.445 58.32 14.715 ;
     RECT  2.16 14.985 58.32 15.12 ;
    LAYER RVTP ;
     RECT  2.16 2.295 58.32 2.565 ;
     RECT  2.16 2.835 58.32 3.105 ;
     RECT  2.16 3.375 58.32 3.645 ;
     RECT  2.16 3.915 58.32 4.185 ;
     RECT  2.16 4.455 58.32 4.725 ;
     RECT  2.16 4.995 58.32 5.265 ;
     RECT  2.16 5.535 58.32 5.805 ;
     RECT  2.16 6.075 58.32 6.345 ;
     RECT  2.16 6.615 58.32 6.885 ;
     RECT  2.16 7.155 58.32 7.425 ;
     RECT  2.16 7.695 58.32 7.965 ;
     RECT  2.16 8.235 58.32 8.505 ;
     RECT  2.16 8.775 58.32 9.045 ;
     RECT  2.16 9.315 58.32 9.585 ;
     RECT  2.16 9.855 58.32 10.125 ;
     RECT  2.16 10.395 58.32 10.665 ;
     RECT  2.16 10.935 58.32 11.205 ;
     RECT  2.16 11.475 58.32 11.745 ;
     RECT  2.16 12.015 58.32 12.285 ;
     RECT  2.16 12.555 58.32 12.825 ;
     RECT  2.16 13.095 58.32 13.365 ;
     RECT  2.16 13.635 58.32 13.905 ;
     RECT  2.16 14.175 58.32 14.445 ;
     RECT  2.16 14.715 58.32 14.985 ;
    LAYER M1 ;
     RECT  2.16 2.151 58.32 15.129 ;
    LAYER M2 ;
     RECT  2.16 2.151 2.479 15.129 ;
     RECT  2.479 2.151 2.623 15.21 ;
     RECT  2.299 16.542 2.623 16.56 ;
     RECT  2.623 1.8 2.795 15.21 ;
     RECT  2.623 16.542 2.839 16.632 ;
     RECT  2.795 1.8 2.867 15.129 ;
     RECT  2.839 16.542 3.335 17.244 ;
     RECT  3.335 16.542 4.307 16.56 ;
     RECT  2.867 2.151 4.495 15.129 ;
     RECT  4.495 1.728 4.631 15.129 ;
     RECT  4.891 0.036 4.991 0.054 ;
     RECT  5.611 16.542 6.683 16.56 ;
     RECT  4.631 2.151 7.231 15.129 ;
     RECT  6.511 0.036 7.295 0.054 ;
     RECT  7.231 1.692 7.367 15.129 ;
     RECT  7.483 16.308 7.987 16.326 ;
     RECT  7.303 17.226 8.015 17.244 ;
     RECT  8.059 0.036 8.159 0.054 ;
     RECT  7.367 2.151 8.455 15.129 ;
     RECT  7.987 16.236 8.455 16.326 ;
     RECT  8.455 2.151 8.959 16.326 ;
     RECT  8.779 0.576 9.383 0.594 ;
     RECT  8.959 1.728 9.635 16.326 ;
     RECT  9.635 2.151 11.227 16.326 ;
     RECT  11.227 1.728 11.759 16.326 ;
     RECT  11.759 1.8 12.083 16.326 ;
     RECT  12.083 2.151 12.415 16.326 ;
     RECT  12.415 0.036 12.551 0.054 ;
     RECT  12.415 2.151 12.631 16.56 ;
     RECT  12.631 2.151 12.731 17.244 ;
     RECT  12.731 2.151 13.451 16.56 ;
     RECT  13.451 2.151 13.639 16.326 ;
     RECT  13.639 1.728 14.027 16.326 ;
     RECT  13.999 0.036 14.567 0.054 ;
     RECT  14.027 2.151 15.763 16.326 ;
     RECT  15.763 2.151 17.195 16.56 ;
     RECT  17.195 2.151 18.031 16.326 ;
     RECT  17.887 1.152 18.167 1.17 ;
     RECT  18.031 2.151 18.491 16.56 ;
     RECT  18.679 0.036 18.959 0.054 ;
     RECT  18.823 17.226 18.995 17.244 ;
     RECT  20.587 17.226 20.723 17.244 ;
     RECT  18.491 2.151 21.271 16.326 ;
     RECT  21.271 1.728 21.379 16.326 ;
     RECT  21.379 1.728 21.479 16.668 ;
     RECT  21.479 1.728 21.875 16.326 ;
     RECT  21.875 1.8 21.911 16.326 ;
     RECT  26.815 0.036 27.095 0.054 ;
     RECT  21.911 2.151 27.383 16.326 ;
     RECT  29.983 17.226 30.947 17.244 ;
     RECT  30.955 17.154 31.127 17.172 ;
     RECT  27.383 2.151 31.171 16.29 ;
     RECT  31.171 2.151 32.243 16.56 ;
     RECT  32.395 17.226 32.495 17.244 ;
     RECT  32.243 2.151 34.475 16.29 ;
     RECT  34.447 17.226 34.547 17.244 ;
     RECT  34.475 2.151 34.727 15.75 ;
     RECT  34.727 2.151 36.419 15.21 ;
     RECT  36.859 16.002 36.959 16.02 ;
     RECT  36.419 2.151 37.615 15.174 ;
     RECT  37.615 2.151 37.751 15.399 ;
     RECT  37.751 2.151 38.155 15.129 ;
     RECT  38.335 16.542 38.767 16.56 ;
     RECT  38.155 1.728 39.011 15.129 ;
     RECT  38.767 16.236 39.199 16.56 ;
     RECT  39.199 16.236 39.299 17.244 ;
     RECT  39.299 17.226 40.127 17.244 ;
     RECT  40.207 0.036 40.379 0.054 ;
     RECT  39.011 2.151 40.423 15.129 ;
     RECT  40.423 2.151 41.323 15.174 ;
     RECT  40.927 17.226 41.495 17.244 ;
     RECT  41.323 1.728 41.503 15.174 ;
     RECT  41.467 0.036 41.531 0.054 ;
     RECT  41.503 1.728 41.963 15.399 ;
     RECT  41.963 2.151 42.179 15.399 ;
     RECT  42.179 2.151 43.807 15.129 ;
     RECT  43.807 2.151 44.311 15.174 ;
     RECT  44.311 1.728 44.375 15.174 ;
     RECT  44.375 1.728 44.663 15.129 ;
     RECT  39.299 16.236 44.887 16.254 ;
     RECT  44.887 16.236 45.023 16.56 ;
     RECT  44.663 2.151 45.607 15.129 ;
     RECT  45.607 2.151 45.787 15.21 ;
     RECT  45.787 2.151 46.067 15.282 ;
     RECT  46.067 2.151 46.355 15.174 ;
     RECT  45.391 0.036 46.463 0.054 ;
     RECT  47.191 0.036 47.291 0.054 ;
     RECT  45.023 16.236 48.055 16.254 ;
     RECT  48.163 0.036 48.271 0.054 ;
     RECT  48.055 16.236 48.379 16.56 ;
     RECT  48.271 0.036 48.407 0.126 ;
     RECT  48.407 0.036 50.099 0.054 ;
     RECT  48.379 16.236 50.135 16.632 ;
     RECT  46.355 2.151 50.935 15.129 ;
     RECT  50.935 2.151 51.035 15.399 ;
     RECT  50.135 16.236 51.223 16.254 ;
     RECT  51.223 16.236 52.079 16.596 ;
     RECT  51.035 2.151 52.123 15.129 ;
     RECT  52.123 2.151 52.439 15.399 ;
     RECT  52.079 16.236 53.051 16.56 ;
     RECT  53.599 17.19 53.843 17.244 ;
     RECT  52.439 2.151 53.995 15.129 ;
     RECT  53.843 17.226 54.059 17.244 ;
     RECT  53.995 2.151 54.095 15.399 ;
     RECT  54.095 2.151 55.111 15.129 ;
     RECT  55.111 2.151 55.211 15.399 ;
     RECT  55.471 0.036 55.535 0.054 ;
     RECT  55.211 2.151 56.047 15.129 ;
     RECT  56.299 0.036 56.435 0.054 ;
     RECT  56.047 2.151 56.435 15.21 ;
     RECT  56.435 2.151 56.983 15.129 ;
     RECT  56.983 1.728 57.515 15.129 ;
     RECT  53.051 16.236 57.883 16.254 ;
     RECT  57.703 0.036 58.019 0.054 ;
     RECT  57.883 15.921 58.019 16.254 ;
     RECT  58.019 16.236 58.091 16.254 ;
     RECT  57.515 2.151 58.32 15.129 ;
    LAYER M3 ;
     RECT  2.304 0.012 58.302 0.125 ;
     RECT  2.304 0.125 51.966 0.173 ;
     RECT  52.704 0.125 57.006 0.173 ;
     RECT  12.42 0.173 27.954 0.221 ;
     RECT  28.692 0.173 33.894 0.221 ;
     RECT  35.964 0.173 44.514 0.221 ;
     RECT  12.42 0.221 24.786 0.269 ;
     RECT  45.252 0.173 51.57 0.269 ;
     RECT  16.812 0.269 24.786 0.317 ;
     RECT  30.708 0.221 33.894 0.317 ;
     RECT  36.324 0.221 44.514 0.365 ;
     RECT  36.54 0.365 44.514 0.461 ;
     RECT  19.98 0.317 24.786 0.509 ;
     RECT  10.26 0.173 11.574 0.557 ;
     RECT  12.42 0.269 15.858 0.557 ;
     RECT  19.98 0.509 22.194 0.557 ;
     RECT  22.932 0.509 24.786 0.557 ;
     RECT  28.692 0.221 29.826 0.557 ;
     RECT  31.5 0.317 33.894 0.557 ;
     RECT  35.028 0.173 35.19 0.557 ;
     RECT  36.54 0.461 43.038 0.557 ;
     RECT  43.776 0.461 44.514 0.557 ;
     RECT  53.604 0.173 54.558 0.557 ;
     RECT  55.296 0.173 57.006 0.557 ;
     RECT  57.996 0.125 58.086 0.557 ;
     RECT  2.304 0.173 9.378 0.599 ;
     RECT  16.812 0.317 18.954 1.099 ;
     RECT  2.304 0.599 9.198 1.723 ;
     RECT  10.836 0.557 11.574 1.723 ;
     RECT  12.42 0.557 12.438 1.723 ;
     RECT  19.98 0.557 21.654 1.723 ;
     RECT  24.444 0.557 24.786 1.723 ;
     RECT  25.524 0.221 27.954 1.723 ;
     RECT  29.088 0.557 29.826 1.723 ;
     RECT  30.708 0.317 30.726 1.723 ;
     RECT  31.86 0.557 33.174 1.723 ;
     RECT  36.684 0.557 37.062 1.723 ;
     RECT  37.836 0.557 39.474 1.723 ;
     RECT  40.356 0.557 42.462 1.723 ;
     RECT  43.776 0.557 44.334 1.723 ;
     RECT  45.252 0.269 50.67 1.723 ;
     RECT  51.552 0.269 51.57 1.723 ;
     RECT  52.848 0.173 52.866 1.723 ;
     RECT  55.512 0.557 57.006 1.723 ;
     RECT  57.996 0.557 58.014 1.723 ;
     RECT  19.98 1.723 21.87 1.795 ;
     RECT  13.644 0.557 15.714 2.011 ;
     RECT  22.932 0.557 23.67 2.011 ;
     RECT  24.444 1.723 30.87 2.011 ;
     RECT  35.172 0.557 35.19 2.011 ;
     RECT  10.836 1.723 12.438 2.143 ;
     RECT  13.356 2.011 15.714 2.143 ;
     RECT  16.632 1.099 18.954 2.143 ;
     RECT  31.86 1.723 34.182 2.143 ;
     RECT  35.172 2.011 35.226 2.143 ;
     RECT  36.684 1.723 50.67 2.143 ;
     RECT  51.552 1.723 52.866 2.143 ;
     RECT  53.64 2.011 53.658 2.143 ;
     RECT  10.515 2.143 12.438 2.155 ;
     RECT  13.215 2.143 18.954 2.155 ;
     RECT  19.98 1.795 21.906 2.155 ;
     RECT  22.932 2.011 30.87 2.155 ;
     RECT  36.684 2.143 52.866 2.155 ;
     RECT  53.64 2.143 53.805 2.155 ;
     RECT  2.232 1.723 9.63 2.191 ;
     RECT  10.515 2.155 18.954 2.191 ;
     RECT  19.98 2.155 30.87 2.191 ;
     RECT  31.86 2.143 35.226 2.191 ;
     RECT  36.684 2.155 53.805 2.191 ;
     RECT  54.54 0.557 54.558 2.191 ;
     RECT  55.512 1.723 58.014 2.191 ;
     RECT  2.232 2.191 9.666 2.203 ;
     RECT  10.515 2.191 53.805 2.203 ;
     RECT  54.54 2.191 58.014 2.251 ;
     RECT  2.232 2.203 53.805 2.335 ;
     RECT  54.54 2.251 58.194 2.335 ;
     RECT  2.232 2.335 58.194 2.795 ;
     RECT  2.304 2.795 58.194 3.065 ;
     RECT  2.34 3.065 58.194 3.181 ;
     RECT  2.34 3.181 58.23 3.335 ;
     RECT  2.376 3.335 58.23 4.117 ;
     RECT  2.34 4.117 58.23 4.531 ;
     RECT  2.34 4.531 58.266 4.651 ;
     RECT  2.304 4.651 58.266 4.685 ;
     RECT  2.34 4.685 58.266 5.131 ;
     RECT  2.34 5.131 58.302 5.459 ;
     RECT  2.34 5.459 58.266 6.179 ;
     RECT  2.376 6.179 58.266 6.889 ;
     RECT  2.376 6.889 58.302 7.501 ;
     RECT  2.34 7.501 58.302 7.771 ;
     RECT  0.108 8.539 0.126 8.544 ;
     RECT  0.105 8.544 0.129 8.664 ;
     RECT  0.108 8.664 0.126 8.669 ;
     RECT  2.304 7.771 58.302 9.005 ;
     RECT  2.34 9.005 58.302 9.581 ;
     RECT  2.34 9.581 58.23 10.589 ;
     RECT  2.376 10.589 58.23 10.895 ;
     RECT  2.412 10.895 58.23 11.165 ;
     RECT  2.415 11.165 58.23 14.251 ;
     RECT  2.415 14.251 58.302 14.669 ;
     RECT  2.415 14.669 58.194 14.717 ;
     RECT  2.415 14.717 58.158 14.909 ;
     RECT  2.415 14.909 57.978 14.945 ;
     RECT  2.415 14.945 55.206 14.981 ;
     RECT  56.016 14.945 57.942 15.089 ;
     RECT  2.415 14.981 6.966 15.137 ;
     RECT  7.815 14.981 55.206 15.137 ;
     RECT  56.016 15.089 56.505 15.137 ;
     RECT  8.244 15.137 55.206 15.389 ;
     RECT  47.844 15.389 55.206 15.404 ;
     RECT  57.312 15.089 57.942 15.883 ;
     RECT  8.46 15.389 47.106 16.231 ;
     RECT  57.312 15.883 58.014 16.231 ;
     RECT  2.484 15.137 6.966 16.303 ;
     RECT  7.992 16.231 47.106 16.303 ;
     RECT  2.484 16.303 47.106 16.537 ;
     RECT  47.844 15.404 52.218 16.537 ;
     RECT  53.028 15.404 55.134 16.537 ;
     RECT  2.304 16.537 47.106 16.555 ;
     RECT  47.844 16.537 55.134 16.555 ;
     RECT  56.016 15.137 56.43 16.555 ;
     RECT  57.312 16.231 58.086 16.555 ;
     RECT  2.304 16.555 58.086 16.939 ;
     RECT  2.304 16.939 58.302 17.261 ;
    LAYER M4 ;
     RECT  0.06 8.64 0.097 8.76 ;
     RECT  0.097 8.544 2.197 8.76 ;
     RECT  2.197 8.4 2.293 8.76 ;
     RECT  2.293 2.88 2.329 2.904 ;
     RECT  2.293 4.512 2.329 4.68 ;
     RECT  2.293 10.32 2.329 10.344 ;
     RECT  2.293 7.776 2.365 8.76 ;
     RECT  2.329 4.128 2.401 4.68 ;
     RECT  2.197 1.728 2.408 1.752 ;
     RECT  2.329 2.784 2.408 2.904 ;
     RECT  2.401 4.128 2.408 4.968 ;
     RECT  2.365 6.816 2.408 8.76 ;
     RECT  2.329 9.792 2.408 10.344 ;
     RECT  2.293 0.096 2.473 0.12 ;
     RECT  2.389 17.136 2.533 17.16 ;
     RECT  2.408 1.728 2.704 15.132 ;
     RECT  2.533 17.088 2.725 17.16 ;
     RECT  2.725 16.56 2.771 17.16 ;
     RECT  2.771 16.896 2.873 17.16 ;
     RECT  2.473 0.096 3.013 0.216 ;
     RECT  3.013 0.048 3.059 0.216 ;
     RECT  2.873 16.896 3.107 17.112 ;
     RECT  3.107 17.088 3.155 17.112 ;
     RECT  3.059 0.144 3.349 0.216 ;
     RECT  2.704 1.728 3.685 10.872 ;
     RECT  3.349 0.144 4.021 0.552 ;
     RECT  4.021 0.096 4.163 0.552 ;
     RECT  3.685 1.728 4.163 11.064 ;
     RECT  3.301 15.36 4.277 15.384 ;
     RECT  4.309 17.184 4.405 17.208 ;
     RECT  4.163 2.148 4.453 11.064 ;
     RECT  4.405 17.136 4.453 17.208 ;
     RECT  4.453 2.148 4.597 11.976 ;
     RECT  4.597 2.148 4.741 12.168 ;
     RECT  4.453 16.56 5.105 17.208 ;
     RECT  4.741 2.148 5.108 12.504 ;
     RECT  5.108 2.148 5.173 15.132 ;
     RECT  4.163 0.528 5.281 0.552 ;
     RECT  5.281 0.336 5.365 0.552 ;
     RECT  5.173 1.728 5.365 15.132 ;
     RECT  5.365 1.728 5.404 15.384 ;
     RECT  5.365 0.24 5.509 0.552 ;
     RECT  5.404 1.728 5.699 13.08 ;
     RECT  5.509 0.096 5.825 0.552 ;
     RECT  5.825 0.096 5.987 0.36 ;
     RECT  5.987 0.096 6.181 0.168 ;
     RECT  5.699 1.728 6.185 12.6 ;
     RECT  5.404 15.312 6.257 15.384 ;
     RECT  5.105 16.56 6.361 17.16 ;
     RECT  6.361 16.56 6.419 17.208 ;
     RECT  6.419 16.56 6.469 17.112 ;
     RECT  6.185 2.16 6.803 12.6 ;
     RECT  6.803 2.16 7.189 12.552 ;
     RECT  7.189 1.728 7.225 12.552 ;
     RECT  7.225 1.68 7.337 12.552 ;
     RECT  6.257 15.36 7.573 15.384 ;
     RECT  6.469 16.512 7.573 17.112 ;
     RECT  7.573 15.36 7.657 17.112 ;
     RECT  7.657 15.36 7.715 17.208 ;
     RECT  7.337 1.728 7.733 12.552 ;
     RECT  7.733 2.148 7.808 12.552 ;
     RECT  6.373 13.632 7.808 13.656 ;
     RECT  7.715 15.36 7.808 17.16 ;
     RECT  7.808 2.148 7.912 17.16 ;
     RECT  6.181 0.048 8.149 0.168 ;
     RECT  7.912 2.256 8.273 17.16 ;
     RECT  8.149 0.048 8.557 0.216 ;
     RECT  8.557 0.048 8.723 0.6 ;
     RECT  8.273 15.648 8.773 17.16 ;
     RECT  8.273 2.256 9.253 14.424 ;
     RECT  9.253 1.728 9.389 14.424 ;
     RECT  9.389 2.208 9.541 14.424 ;
     RECT  9.541 2.208 9.637 14.472 ;
     RECT  8.773 15.648 9.637 17.208 ;
     RECT  8.723 0.048 9.877 0.312 ;
     RECT  9.877 0.048 10.115 0.504 ;
     RECT  10.115 0.096 10.213 0.504 ;
     RECT  10.213 0.096 10.289 0.552 ;
     RECT  9.637 2.208 10.508 17.208 ;
     RECT  10.508 2.148 10.612 17.208 ;
     RECT  10.289 0.096 10.685 0.504 ;
     RECT  10.685 0.096 11.941 0.36 ;
     RECT  10.612 2.208 11.941 17.208 ;
     RECT  11.941 0.048 12.181 0.36 ;
     RECT  12.181 0.048 13.097 0.552 ;
     RECT  13.097 0.048 13.667 0.312 ;
     RECT  11.941 1.728 14.105 17.208 ;
     RECT  13.667 0.048 14.435 0.216 ;
     RECT  14.105 2.208 14.609 17.208 ;
     RECT  14.435 0.048 14.723 0.168 ;
     RECT  14.723 0.048 15.155 0.072 ;
     RECT  14.609 2.256 15.733 17.208 ;
     RECT  15.733 2.016 15.971 17.208 ;
     RECT  15.971 2.148 16.012 17.208 ;
     RECT  15.685 0.144 16.225 0.552 ;
     RECT  16.012 2.256 16.451 17.208 ;
     RECT  16.225 0.096 16.585 0.552 ;
     RECT  16.585 0.048 16.621 0.552 ;
     RECT  16.621 0.048 16.841 1.128 ;
     RECT  17.077 1.152 17.461 1.368 ;
     RECT  16.451 2.736 17.461 17.208 ;
     RECT  16.841 0.048 17.845 0.072 ;
     RECT  17.461 1.152 17.845 17.208 ;
     RECT  17.845 0.048 18.137 17.208 ;
     RECT  18.137 1.152 18.227 17.208 ;
     RECT  18.137 0.048 19.525 0.168 ;
     RECT  19.525 0.048 19.573 0.264 ;
     RECT  19.573 0.048 19.715 0.312 ;
     RECT  18.227 1.728 19.763 17.208 ;
     RECT  19.763 2.208 19.811 17.208 ;
     RECT  19.715 0.048 20.339 0.264 ;
     RECT  19.811 2.208 20.965 17.16 ;
     RECT  20.965 1.728 21.017 17.16 ;
     RECT  21.017 2.016 21.731 17.16 ;
     RECT  20.339 0.048 21.973 0.216 ;
     RECT  21.973 0.048 22.117 0.504 ;
     RECT  22.117 0.048 22.205 0.552 ;
     RECT  21.731 2.16 22.345 17.16 ;
     RECT  22.345 2.16 22.403 17.208 ;
     RECT  22.205 0.048 22.781 0.504 ;
     RECT  22.781 0.048 22.835 0.168 ;
     RECT  22.403 2.16 22.931 17.16 ;
     RECT  22.931 2.256 23.411 17.16 ;
     RECT  22.835 0.048 23.845 0.072 ;
     RECT  23.845 0.048 23.897 0.552 ;
     RECT  23.411 2.256 23.941 17.112 ;
     RECT  23.941 2.016 24.185 17.112 ;
     RECT  24.185 2.256 24.517 17.112 ;
     RECT  24.517 2.256 24.937 17.16 ;
     RECT  24.937 2.256 25.237 17.208 ;
     RECT  25.237 1.728 25.373 17.208 ;
     RECT  23.897 0.048 26.197 0.216 ;
     RECT  25.373 2.208 26.708 17.208 ;
     RECT  26.708 2.148 26.812 17.208 ;
     RECT  26.197 0.048 27.155 0.552 ;
     RECT  27.155 0.048 27.251 0.312 ;
     RECT  27.251 0.048 27.299 0.216 ;
     RECT  27.299 0.048 28.163 0.072 ;
     RECT  26.812 2.16 28.213 17.208 ;
     RECT  28.321 0.144 28.501 0.168 ;
     RECT  28.213 1.728 28.505 17.208 ;
     RECT  28.501 0.144 29.221 0.552 ;
     RECT  29.221 0.096 29.441 0.552 ;
     RECT  28.505 1.776 29.509 17.208 ;
     RECT  29.441 0.096 29.617 0.312 ;
     RECT  29.509 1.728 30.197 17.208 ;
     RECT  29.617 0.048 30.469 0.312 ;
     RECT  30.469 0.048 30.805 0.408 ;
     RECT  30.197 1.728 30.805 17.16 ;
     RECT  30.805 0.048 30.947 17.16 ;
     RECT  30.947 0.048 31.139 0.552 ;
     RECT  30.947 1.728 31.489 17.16 ;
     RECT  31.489 1.728 32.285 17.208 ;
     RECT  31.139 0.096 32.389 0.552 ;
     RECT  32.389 0.048 32.485 0.552 ;
     RECT  32.285 1.728 32.485 14.952 ;
     RECT  32.485 0.048 32.627 14.952 ;
     RECT  32.285 15.984 32.825 17.208 ;
     RECT  32.627 0.048 33.011 0.552 ;
     RECT  33.011 0.096 33.203 0.552 ;
     RECT  32.627 1.728 33.469 14.952 ;
     RECT  32.825 15.984 33.469 17.112 ;
     RECT  33.469 1.728 33.725 17.112 ;
     RECT  33.203 0.144 33.905 0.552 ;
     RECT  33.725 1.728 34.019 16.008 ;
     RECT  34.019 1.728 34.193 15.384 ;
     RECT  33.905 0.144 34.261 0.504 ;
     RECT  33.725 17.088 34.261 17.112 ;
     RECT  34.261 17.088 34.739 17.208 ;
     RECT  34.261 0.048 35.017 0.504 ;
     RECT  34.193 2.016 35.237 15.384 ;
     RECT  35.017 0.048 35.315 0.552 ;
     RECT  34.739 17.136 35.603 17.208 ;
     RECT  35.603 17.136 35.737 17.16 ;
     RECT  35.737 17.04 35.741 17.16 ;
     RECT  35.741 17.04 35.795 17.064 ;
     RECT  36.133 16.656 36.229 16.872 ;
     RECT  35.315 0.048 36.371 0.504 ;
     RECT  36.371 0.336 36.373 0.504 ;
     RECT  36.229 16.56 36.565 16.872 ;
     RECT  35.237 2.208 36.757 14.856 ;
     RECT  36.565 15.936 36.757 16.872 ;
     RECT  36.757 15.84 36.893 16.872 ;
     RECT  36.893 16.848 37.141 16.872 ;
     RECT  37.141 16.848 37.189 16.968 ;
     RECT  36.757 1.728 37.361 14.856 ;
     RECT  37.361 2.148 37.465 14.856 ;
     RECT  36.373 0.336 37.469 0.552 ;
     RECT  37.469 0.336 37.525 0.36 ;
     RECT  37.465 2.148 37.612 15.384 ;
     RECT  37.189 16.848 37.717 17.112 ;
     RECT  37.525 0.096 37.955 0.36 ;
     RECT  37.717 16.848 37.969 17.16 ;
     RECT  37.612 2.208 38.081 15.384 ;
     RECT  37.969 16.56 38.099 17.16 ;
     RECT  38.081 2.256 38.195 15.384 ;
     RECT  38.195 2.256 38.291 14.28 ;
     RECT  37.955 0.096 38.329 0.312 ;
     RECT  38.329 0.048 38.387 0.312 ;
     RECT  38.387 0.096 38.579 0.312 ;
     RECT  38.195 15.36 39.205 15.384 ;
     RECT  38.291 2.256 39.265 14.232 ;
     RECT  38.579 0.144 39.349 0.312 ;
     RECT  39.265 2.208 39.541 14.232 ;
     RECT  38.099 16.944 39.541 17.16 ;
     RECT  39.541 16.512 39.593 17.16 ;
     RECT  39.349 0.144 39.625 0.552 ;
     RECT  39.593 16.56 39.625 17.16 ;
     RECT  39.625 0.048 39.683 0.552 ;
     RECT  39.625 16.56 39.683 17.208 ;
     RECT  39.683 0.096 39.881 0.552 ;
     RECT  39.541 1.728 40.208 14.232 ;
     RECT  39.205 15.312 40.208 15.384 ;
     RECT  39.683 16.56 40.241 17.16 ;
     RECT  40.208 1.728 40.493 15.384 ;
     RECT  40.493 1.728 40.504 15.336 ;
     RECT  40.241 16.848 40.745 17.16 ;
     RECT  39.881 0.096 40.777 0.216 ;
     RECT  40.777 0.048 40.835 0.216 ;
     RECT  40.835 0.096 40.921 0.216 ;
     RECT  40.504 1.728 41.075 14.28 ;
     RECT  40.921 0.096 41.171 0.264 ;
     RECT  41.171 0.144 41.269 0.264 ;
     RECT  41.075 1.776 41.537 14.28 ;
     RECT  41.537 2.256 41.557 14.28 ;
     RECT  40.504 15.312 41.557 15.336 ;
     RECT  40.745 16.944 42.073 17.16 ;
     RECT  41.269 0.144 42.181 0.552 ;
     RECT  41.557 2.256 42.181 15.336 ;
     RECT  42.181 0.096 42.613 0.552 ;
     RECT  42.613 0.048 42.659 0.552 ;
     RECT  42.181 2.256 42.661 15.384 ;
     RECT  42.661 1.776 42.793 15.384 ;
     RECT  42.073 16.944 43.009 17.208 ;
     RECT  42.659 0.096 43.049 0.552 ;
     RECT  42.793 1.728 43.265 15.384 ;
     RECT  43.049 0.096 43.331 0.456 ;
     RECT  43.009 16.56 43.331 17.208 ;
     RECT  43.331 0.144 43.409 0.456 ;
     RECT  43.331 16.944 43.811 17.208 ;
     RECT  43.265 2.208 44.389 15.384 ;
     RECT  43.409 0.144 44.437 0.168 ;
     RECT  44.437 0.144 44.525 0.552 ;
     RECT  44.525 0.144 44.665 0.168 ;
     RECT  43.811 16.944 44.741 17.16 ;
     RECT  44.741 16.944 44.773 17.112 ;
     RECT  44.389 1.728 45.011 15.384 ;
     RECT  45.011 2.148 45.685 15.384 ;
     RECT  44.773 16.512 45.685 17.112 ;
     RECT  45.685 2.148 45.712 17.112 ;
     RECT  44.665 0.048 45.877 0.168 ;
     RECT  45.877 0.048 45.961 0.216 ;
     RECT  45.712 2.208 45.961 17.112 ;
     RECT  45.961 0.048 46.177 0.264 ;
     RECT  46.177 0.048 46.259 0.36 ;
     RECT  45.961 2.208 46.505 17.208 ;
     RECT  46.505 2.208 46.717 15.384 ;
     RECT  46.505 16.512 46.901 17.208 ;
     RECT  46.717 2.16 47.027 15.384 ;
     RECT  47.027 2.208 47.045 15.384 ;
     RECT  46.901 16.56 47.297 17.208 ;
     RECT  46.259 0.048 47.363 0.264 ;
     RECT  47.045 2.256 48.308 15.384 ;
     RECT  48.308 2.148 48.445 15.384 ;
     RECT  47.297 16.944 48.803 17.208 ;
     RECT  48.445 2.016 48.949 15.384 ;
     RECT  48.803 16.944 49.129 17.16 ;
     RECT  47.363 0.048 49.333 0.168 ;
     RECT  48.949 1.728 49.349 15.384 ;
     RECT  49.129 16.896 49.379 17.16 ;
     RECT  49.333 0.048 49.565 0.552 ;
     RECT  49.349 2.208 49.669 15.384 ;
     RECT  49.379 16.896 49.669 17.112 ;
     RECT  49.669 2.208 50.003 17.112 ;
     RECT  49.565 0.048 50.291 0.168 ;
     RECT  50.003 16.512 50.425 17.112 ;
     RECT  50.003 2.208 50.677 15.384 ;
     RECT  50.291 0.144 50.869 0.168 ;
     RECT  50.869 0.144 51.253 0.264 ;
     RECT  50.425 16.512 51.257 17.208 ;
     RECT  51.253 0.144 51.361 0.312 ;
     RECT  51.257 16.56 51.587 17.208 ;
     RECT  50.677 1.728 51.761 15.384 ;
     RECT  51.361 0.048 51.827 0.312 ;
     RECT  51.761 1.728 52.115 14.952 ;
     RECT  52.115 1.728 52.229 14.856 ;
     RECT  52.229 1.824 52.265 14.856 ;
     RECT  51.587 16.56 53.129 17.16 ;
     RECT  52.265 2.16 53.221 14.856 ;
     RECT  51.827 0.048 53.317 0.216 ;
     RECT  53.129 16.8 53.413 17.16 ;
     RECT  53.317 0.048 53.459 0.264 ;
     RECT  53.413 16.8 53.459 17.208 ;
     RECT  53.459 0.096 53.557 0.264 ;
     RECT  53.221 2.16 53.629 15 ;
     RECT  53.629 2.016 53.699 15 ;
     RECT  53.699 2.148 53.708 15 ;
     RECT  53.708 2.148 53.812 15.132 ;
     RECT  53.812 2.256 54.037 15.132 ;
     RECT  53.459 16.8 54.229 17.16 ;
     RECT  54.229 16.752 54.277 17.16 ;
     RECT  54.037 2.256 54.613 15.24 ;
     RECT  53.557 0.096 54.709 0.552 ;
     RECT  54.613 2.256 54.781 15.384 ;
     RECT  54.781 2.208 54.785 15.384 ;
     RECT  54.785 2.208 55.753 15 ;
     RECT  54.709 0.048 55.865 0.552 ;
     RECT  55.753 1.728 56.101 15 ;
     RECT  54.277 16.56 56.621 17.16 ;
     RECT  56.621 16.608 56.761 17.16 ;
     RECT  56.761 16.608 57.017 17.208 ;
     RECT  57.017 16.944 57.539 17.208 ;
     RECT  56.101 1.728 57.557 15.384 ;
     RECT  57.557 2.256 57.589 15.384 ;
     RECT  57.539 16.944 57.875 17.112 ;
     RECT  57.589 2.256 57.881 15.96 ;
     RECT  55.865 0.048 57.923 0.168 ;
     RECT  57.923 0.096 58.021 0.168 ;
     RECT  57.881 2.256 58.025 15.912 ;
     RECT  58.021 0.096 58.097 0.552 ;
     RECT  58.025 2.256 58.115 15 ;
     RECT  58.115 2.256 58.205 14.712 ;
     RECT  58.205 2.256 58.211 7.08 ;
     RECT  58.205 8.496 58.211 14.664 ;
     RECT  58.211 2.256 58.259 2.904 ;
     RECT  58.211 8.496 58.259 9.096 ;
     RECT  58.211 3.936 58.277 7.08 ;
     RECT  58.211 11.472 58.313 14.664 ;
     RECT  57.875 16.944 58.313 16.968 ;
     RECT  58.277 3.936 58.355 6.888 ;
     RECT  58.313 11.472 58.355 13.944 ;
     RECT  58.259 2.256 58.403 2.856 ;
     RECT  58.355 11.76 58.403 13.944 ;
     RECT  58.403 2.256 58.451 2.28 ;
     RECT  58.403 11.76 58.451 11.784 ;
     RECT  58.355 3.936 58.499 4.728 ;
     RECT  58.355 6.624 58.499 6.888 ;
     RECT  58.259 8.496 58.499 8.52 ;
     RECT  58.403 13.296 58.499 13.944 ;
     RECT  58.097 0.096 58.547 0.12 ;
     RECT  58.499 4.704 58.547 4.728 ;
     RECT  58.499 6.864 58.547 6.888 ;
     RECT  58.499 13.296 58.547 13.32 ;
    LAYER M5 ;
     RECT  2.208 0.016 58.2 0.085 ;
     RECT  2.208 0.085 58.536 1.763 ;
     RECT  2.304 1.763 58.536 2.915 ;
     RECT  2.4 2.915 58.536 4.501 ;
     RECT  2.304 4.501 58.536 4.739 ;
     RECT  2.304 4.739 58.488 6.853 ;
     RECT  2.304 6.853 58.536 8.389 ;
     RECT  2.208 8.389 58.536 11.507 ;
     RECT  2.208 11.507 9.096 12.611 ;
     RECT  6.816 12.611 9.096 12.757 ;
     RECT  10.128 11.507 58.536 12.757 ;
     RECT  6.816 12.757 58.536 13.139 ;
     RECT  15.312 13.139 58.536 13.331 ;
     RECT  2.208 12.611 5.688 13.621 ;
     RECT  6.816 13.139 14.232 13.621 ;
     RECT  15.312 13.331 58.488 13.715 ;
     RECT  15.408 13.715 58.488 13.955 ;
     RECT  2.208 13.621 14.232 15.973 ;
     RECT  15.408 13.955 58.2 15.973 ;
     RECT  2.208 15.973 58.2 17.232 ;
     RECT  9.096 11.507 10.128 12.757 ;
     RECT  5.688 12.611 6.816 13.621 ;
     RECT  14.232 13.139 15.312 13.715 ;
     RECT  14.232 13.715 15.408 15.973 ;
  END
END dsfd_qbank_S
END LIBRARY
